VERSION 5.8 ;
BUSBITCHARS "[]" ;

UNITS
  DATABASE MICRONS 1000 ;
END UNITS

MANUFACTURINGGRID 0.005 ;

PROPERTYDEFINITIONS
  MACRO expanded_util REAL ;
END PROPERTYDEFINITIONS

LAYER POLY1
  TYPE MASTERSLICE ;
END POLY1

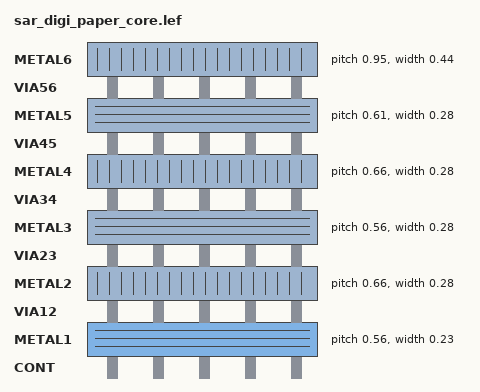
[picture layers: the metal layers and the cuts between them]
LAYER CONT
  TYPE CUT ;
END CONT

LAYER METAL1
  TYPE ROUTING ;
  DIRECTION HORIZONTAL ;
  PITCH 0.56 ;
  WIDTH 0.23 ;
  PROPERTY LEF58_WIDTH "WIDTH 0.23 WRONGDIRECTION ;" ;
END METAL1

LAYER VIA12
  TYPE CUT ;
END VIA12

LAYER METAL2
  TYPE ROUTING ;
  DIRECTION VERTICAL ;
  PITCH 0.66 ;
  WIDTH 0.28 ;
  PROPERTY LEF58_WIDTH "WIDTH 0.28 WRONGDIRECTION ;" ;
END METAL2

LAYER VIA23
  TYPE CUT ;
END VIA23

LAYER METAL3
  TYPE ROUTING ;
  DIRECTION HORIZONTAL ;
  PITCH 0.56 ;
  WIDTH 0.28 ;
  PROPERTY LEF58_WIDTH "WIDTH 0.28 WRONGDIRECTION ;" ;
END METAL3

LAYER VIA34
  TYPE CUT ;
END VIA34

LAYER METAL4
  TYPE ROUTING ;
  DIRECTION VERTICAL ;
  PITCH 0.66 ;
  WIDTH 0.28 ;
  PROPERTY LEF58_WIDTH "WIDTH 0.28 WRONGDIRECTION ;" ;
END METAL4

LAYER VIA45
  TYPE CUT ;
END VIA45

LAYER METAL5
  TYPE ROUTING ;
  DIRECTION HORIZONTAL ;
  PITCH 0.61 ;
  WIDTH 0.28 ;
  PROPERTY LEF58_WIDTH "WIDTH 0.28 WRONGDIRECTION ;" ;
END METAL5

LAYER VIA56
  TYPE CUT ;
END VIA56

LAYER METAL6
  TYPE ROUTING ;
  DIRECTION VERTICAL ;
  PITCH 0.95 ;
  WIDTH 0.44 ;
  PROPERTY LEF58_WIDTH "WIDTH 0.44 WRONGDIRECTION ;" ;
END METAL6

LAYER TEXT1
  TYPE MASTERSLICE ;
END TEXT1

LAYER TEXT2
  TYPE MASTERSLICE ;
END TEXT2

LAYER TEXT3
  TYPE MASTERSLICE ;
END TEXT3

LAYER TEXT4
  TYPE MASTERSLICE ;
END TEXT4

LAYER TEXT5
  TYPE MASTERSLICE ;
END TEXT5

LAYER TEXT6
  TYPE MASTERSLICE ;
END TEXT6

LAYER NWELL
  TYPE MASTERSLICE ;
END NWELL

LAYER PIMP
  TYPE MASTERSLICE ;
END PIMP

LAYER NIMP
  TYPE MASTERSLICE ;
END NIMP

LAYER DIFF
  TYPE MASTERSLICE ;
END DIFF

LAYER DIODE
  TYPE MASTERSLICE ;
END DIODE

LAYER PAD
  TYPE MASTERSLICE ;
END PAD

VIA CONT1
  LAYER POLY1 ;
    RECT -0.21 -0.21 0.21 0.21 ;
  LAYER CONT ;
    RECT -0.11 -0.11 0.11 0.11 ;
  LAYER METAL1 ;
    RECT -0.17 -0.12 0.17 0.12 ;
END CONT1

VIA via1
  LAYER METAL1 ;
    RECT -0.19 -0.14 0.19 0.14 ;
  LAYER VIA12 ;
    RECT -0.13 -0.13 0.13 0.13 ;
  LAYER METAL2 ;
    RECT -0.19 -0.14 0.19 0.14 ;
END via1

VIA via2
  LAYER METAL2 ;
    RECT -0.19 -0.14 0.19 0.14 ;
  LAYER VIA23 ;
    RECT -0.13 -0.13 0.13 0.13 ;
  LAYER METAL3 ;
    RECT -0.19 -0.14 0.19 0.14 ;
END via2

VIA via3
  LAYER METAL3 ;
    RECT -0.19 -0.14 0.19 0.14 ;
  LAYER VIA34 ;
    RECT -0.13 -0.13 0.13 0.13 ;
  LAYER METAL4 ;
    RECT -0.19 -0.14 0.19 0.14 ;
END via3

VIA via4
  LAYER METAL4 ;
    RECT -0.19 -0.14 0.19 0.14 ;
  LAYER VIA45 ;
    RECT -0.13 -0.13 0.13 0.13 ;
  LAYER METAL5 ;
    RECT -0.19 -0.14 0.19 0.14 ;
END via4

VIA via5
  LAYER METAL5 ;
    RECT -0.24 -0.19 0.24 0.19 ;
  LAYER VIA56 ;
    RECT -0.18 -0.18 0.18 0.18 ;
  LAYER METAL6 ;
    RECT -0.27 -0.27 0.27 0.27 ;
END via5

VIA via2ts
  LAYER METAL2 ;
    RECT -0.14 -0.37 0.14 0.37 ;
  LAYER VIA23 ;
    RECT -0.13 -0.13 0.13 0.13 ;
  LAYER METAL3 ;
    RECT -0.19 -0.14 0.19 0.14 ;
END via2ts

VIA via3ts
  LAYER METAL3 ;
    RECT -0.37 -0.14 0.37 0.14 ;
  LAYER VIA34 ;
    RECT -0.13 -0.13 0.13 0.13 ;
  LAYER METAL4 ;
    RECT -0.19 -0.14 0.19 0.14 ;
END via3ts

VIA via4ts
  LAYER METAL4 ;
    RECT -0.14 -0.37 0.14 0.37 ;
  LAYER VIA45 ;
    RECT -0.13 -0.13 0.13 0.13 ;
  LAYER METAL5 ;
    RECT -0.19 -0.14 0.19 0.14 ;
END via4ts

VIA via5ts
  LAYER METAL5 ;
    RECT -0.27 -0.19 0.27 0.19 ;
  LAYER VIA56 ;
    RECT -0.18 -0.18 0.18 0.18 ;
  LAYER METAL6 ;
    RECT -0.27 -0.27 0.27 0.27 ;
END via5ts

SITE unit
  CLASS CORE ;
  SYMMETRY Y ;
  SIZE 0.66 BY 5.04 ;
END unit

SITE smic18site
  CLASS CORE ;
  SYMMETRY Y ;
  SIZE 0.66 BY 5.04 ;
END smic18site

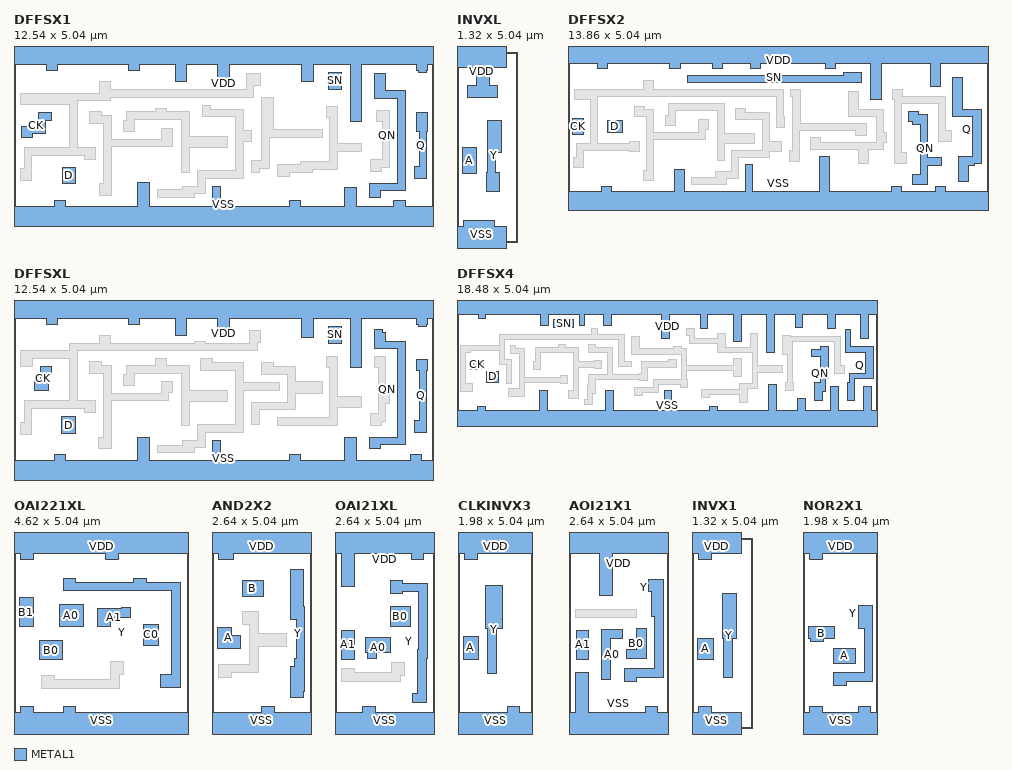
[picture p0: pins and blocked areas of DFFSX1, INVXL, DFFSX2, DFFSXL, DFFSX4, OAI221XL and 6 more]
MACRO DFFSX1
  CLASS CORE ;
  FOREIGN DFFSX1 ;
  ORIGIN 0 0 ;
  SIZE 12.54 BY 5.04 ;
  SYMMETRY X Y ;
  SITE unit ;
  PIN D
    DIRECTION INPUT ;
    USE SIGNAL ;
    PORT
      LAYER METAL1 ;
        RECT 1.435 1.08 1.845 1.58 ;
    END
  END D
  PIN CK
    DIRECTION INPUT ;
    USE SIGNAL ;
    PORT
      LAYER METAL1 ;
        POLYGON 1.105 3.195 1.105 2.965 0.955 2.965 0.955 2.575 0.555 2.575 0.555 2.465 0.215 2.465 0.215 2.805 0.725 2.805 0.725 3.195 ;
    END
  END CK
  PIN SN
    DIRECTION INPUT ;
    USE SIGNAL ;
    PORT
      LAYER METAL1 ;
        RECT 9.38 3.9 9.79 4.41 ;
    END
  END SN
  PIN Q
    DIRECTION OUTPUT ;
    USE SIGNAL ;
    PORT
      LAYER METAL1 ;
        POLYGON 12.36 3.21 12.36 2.63 12.325 2.63 12.325 1.25 11.96 1.25 11.96 1.59 12.095 1.59 12.095 2.63 12.02 2.63 12.02 3.21 ;
    END
  END Q
  PIN QN
    DIRECTION OUTPUT ;
    USE SIGNAL ;
    PORT
      LAYER METAL1 ;
        POLYGON 11.1 4.37 11.1 3.87 11.69 3.87 11.69 0.87 10.945 0.87 10.945 0.67 10.605 0.67 10.605 1.1 11.46 1.1 11.46 3.64 10.76 3.64 10.76 4.37 ;
    END
  END QN
  PIN VDD
    DIRECTION INPUT ;
    USE POWER ;
    PORT
      LAYER METAL1 ;
        POLYGON 12.54 5.44 12.54 4.64 12.36 4.64 12.36 4.465 12.305 4.465 12.305 4.41 12.075 4.41 12.075 4.465 12.02 4.465 12.02 4.64 10.38 4.64 10.38 2.94 10.04 2.94 10.04 4.64 8.93 4.64 8.93 4.14 8.59 4.14 8.59 4.64 6.42 4.64 6.42 4.14 6.08 4.14 6.08 4.64 5.16 4.64 5.16 4.14 4.82 4.14 4.82 4.64 3.76 4.64 3.76 4.465 3.42 4.465 3.42 4.64 1.3 4.64 1.3 4.465 0.96 4.465 0.96 4.64 0 4.64 0 5.44 ;
    END
  END VDD
  PIN VSS
    DIRECTION INPUT ;
    USE GROUND ;
    PORT
      LAYER METAL1 ;
        POLYGON 4.04 1.11 4.04 0.4 5.935 0.4 5.935 1.01 6.165 1.01 6.165 0.4 8.22 0.4 8.22 0.575 8.56 0.575 8.56 0.4 9.88 0.4 9.88 0.96 10.22 0.96 10.22 0.4 11.345 0.4 11.345 0.575 11.685 0.575 11.685 0.4 12.54 0.4 12.54 -0.4 0 -0.4 0 0.4 1.205 0.4 1.205 0.575 1.545 0.575 1.545 0.4 3.7 0.4 3.7 1.11 ;
    END
  END VSS
  OBS
    LAYER METAL1 ;
      POLYGON 7.37 4.36 7.37 4.02 7.165 4.02 7.165 3.67 2.88 3.67 2.88 3.56 1.905 3.56 1.905 2.16 2.445 2.16 2.445 1.82 2.105 1.82 2.105 1.93 0.53 1.93 0.53 1.19 0.19 1.19 0.19 1.53 0.3 1.53 0.3 2.16 1.655 2.16 1.655 3.45 0.195 3.45 0.195 3.79 2.54 3.79 2.54 4.14 2.88 4.14 2.88 3.9 6.935 3.9 6.935 4.36 ;
      POLYGON 7.74 3.65 7.74 2.695 9.2 2.695 9.2 2.465 7.63 2.465 7.63 1.54 7.325 1.54 7.325 1.43 7.095 1.43 7.095 1.77 7.4 1.77 7.4 3.65 ;
      POLYGON 5.865 3.42 5.865 3.31 6.84 3.31 6.84 2.675 7.1 2.675 7.1 2.335 6.84 2.335 6.84 1.24 5.705 1.24 5.705 0.78 5.385 0.78 5.385 0.675 5.38 0.675 5.38 0.67 5.04 0.67 5.04 0.675 4.27 0.675 4.27 0.905 5.04 0.905 5.04 1.01 5.475 1.01 5.475 1.47 6.61 1.47 6.61 3.08 5.635 3.08 5.635 3.42 ;
      POLYGON 9.66 3.4 9.66 2.27 10.37 2.27 10.37 2.04 9.66 2.04 9.66 1.52 8.9 1.52 8.9 1.405 8.22 1.405 8.22 1.305 7.88 1.305 7.88 1.645 8.56 1.645 8.56 1.75 9.43 1.75 9.43 3.06 9.32 3.06 9.32 3.4 ;
      POLYGON 4.56 3.34 4.56 3.23 5.245 3.23 5.245 2.505 6.375 2.505 6.375 2.165 5.245 2.165 5.245 1.42 5.015 1.42 5.015 3 3.6 3 3.6 2.64 3.26 2.64 3.26 2.98 3.37 2.98 3.37 3.23 4.22 3.23 4.22 3.34 ;
      POLYGON 11.225 3.28 11.225 1.57 10.985 1.57 10.985 1.46 10.645 1.46 10.645 1.8 10.995 1.8 10.995 2.94 10.815 2.94 10.815 3.28 ;
      POLYGON 2.6 3.225 2.6 3.115 2.91 3.115 2.91 2.41 4.39 2.41 4.39 2.735 4.73 2.735 4.73 2.395 4.725 2.395 4.725 2.18 2.91 2.18 2.91 0.74 2.565 0.74 2.565 1.08 2.68 1.08 2.68 2.885 2.26 2.885 2.26 3.225 ;
  END
END DFFSX1

MACRO INVXL
  CLASS CORE ;
  FOREIGN INVXL ;
  ORIGIN 0 0 ;
  SIZE 1.32 BY 5.04 ;
  SYMMETRY X Y ;
  SITE unit ;
  PIN A
    DIRECTION INPUT ;
    USE SIGNAL ;
    PORT
      LAYER METAL1 ;
        RECT 0.14 1.82 0.52 2.51 ;
    END
  END A
  PIN Y
    DIRECTION OUTPUT ;
    USE SIGNAL ;
    PORT
      LAYER METAL1 ;
        POLYGON 1.18 3.225 1.18 2.38 1.03 2.38 1.03 1.845 1.12 1.845 1.12 1.35 0.78 1.35 0.78 1.845 0.8 1.845 0.8 3.225 ;
    END
  END Y
  PIN VDD
    DIRECTION INPUT ;
    USE POWER ;
    PORT
      LAYER METAL1 ;
        POLYGON 1.32 5.44 1.32 4.64 0.85 4.64 0.85 4.16 1.085 4.16 1.085 3.82 0.275 3.82 0.275 4.16 0.51 4.16 0.51 4.64 0 4.64 0 5.44 ;
    END
  END VDD
  PIN VSS
    DIRECTION INPUT ;
    USE GROUND ;
    PORT
      LAYER METAL1 ;
        POLYGON 0.99 0.575 0.99 0.4 1.32 0.4 1.32 -0.4 0 -0.4 0 0.4 0.18 0.4 0.18 0.575 ;
    END
  END VSS
END INVXL

MACRO DFFSX2
  CLASS CORE ;
  FOREIGN DFFSX2 ;
  ORIGIN 0 0 ;
  SIZE 13.86 BY 5.04 ;
  SYMMETRY X Y ;
  SITE unit ;
  PIN D
    DIRECTION INPUT ;
    USE SIGNAL ;
    PORT
      LAYER METAL1 ;
        RECT 1.29 2.36 1.805 2.755 ;
    END
  END D
  PIN CK
    DIRECTION INPUT ;
    USE SIGNAL ;
    PORT
      LAYER METAL1 ;
        RECT 0.135 2.295 0.515 2.83 ;
    END
  END CK
  PIN SN
    DIRECTION INPUT ;
    USE SIGNAL ;
    PORT
      LAYER METAL1 ;
        POLYGON 9.685 4.355 9.685 4.005 3.93 4.005 3.93 4.235 9.085 4.235 9.085 4.355 ;
    END
  END SN
  PIN Q
    DIRECTION OUTPUT ;
    USE SIGNAL ;
    PORT
      LAYER METAL1 ;
        POLYGON 13.02 4.165 13.02 3.115 13.645 3.115 13.645 1.325 13.415 1.325 13.415 1.26 13.23 1.26 13.23 0.745 12.89 0.745 12.89 1.555 13.34 1.555 13.34 2.885 12.68 2.885 12.68 4.165 ;
    END
  END Q
  PIN QN
    DIRECTION OUTPUT ;
    USE SIGNAL ;
    PORT
      LAYER METAL1 ;
        POLYGON 11.58 3.05 11.58 2.94 11.86 2.94 11.86 1.54 12.325 1.54 12.325 1.26 11.86 1.26 11.86 0.63 11.37 0.63 11.37 0.97 11.63 0.97 11.63 2.635 11.36 2.635 11.36 2.71 11.24 2.71 11.24 3.05 ;
    END
  END QN
  PIN VDD
    DIRECTION INPUT ;
    USE POWER ;
    PORT
      LAYER METAL1 ;
        POLYGON 13.86 5.44 13.86 4.64 12.3 4.64 12.3 3.865 11.96 3.865 11.96 4.64 10.33 4.64 10.33 3.445 9.98 3.445 9.98 3.785 9.99 3.785 9.99 4.64 8.84 4.64 8.84 4.465 8.5 4.465 8.5 4.64 6.36 4.64 6.36 4.465 6.02 4.465 6.02 4.64 5.1 4.64 5.1 4.465 4.76 4.465 4.76 4.64 3.7 4.64 3.7 4.465 3.36 4.465 3.36 4.64 1.31 4.64 1.31 4.465 0.97 4.465 0.97 4.64 0 4.64 0 5.44 ;
    END
  END VDD
  PIN VSS
    DIRECTION INPUT ;
    USE GROUND ;
    PORT
      LAYER METAL1 ;
        POLYGON 8.63 1.565 8.63 0.4 10.67 0.4 10.67 0.575 11.01 0.575 11.01 0.4 12.13 0.4 12.13 0.575 12.47 0.575 12.47 0.4 13.86 0.4 13.86 -0.4 0 -0.4 0 0.4 1.11 0.4 1.11 0.575 1.45 0.575 1.45 0.4 3.52 0.4 3.52 1.13 3.86 1.13 3.86 0.4 5.855 0.4 5.855 1.3 6.085 1.3 6.085 0.4 8.29 0.4 8.29 1.565 ;
    END
  END VSS
  OBS
    LAYER METAL1 ;
      POLYGON 2.82 4.06 2.82 3.775 7.11 3.775 7.11 2.88 7.145 2.88 7.145 2.54 6.88 2.54 6.88 3.545 0.98 3.545 0.98 2.01 2.03 2.01 2.03 2.065 2.37 2.065 2.37 1.725 2.03 1.725 2.03 1.78 0.525 1.78 0.525 1.19 0.185 1.19 0.185 1.53 0.295 1.53 0.295 2.01 0.75 2.01 0.75 3.45 0.21 3.45 0.21 3.79 0.55 3.79 0.55 3.775 2.48 3.775 2.48 4.06 ;
      POLYGON 11.04 3.78 11.04 3.545 12.45 3.545 12.45 2.41 12.67 2.41 12.67 2.07 12.22 2.07 12.22 3.315 11.01 3.315 11.01 1.685 11.17 1.685 11.17 1.345 10.78 1.345 10.78 3.44 10.7 3.44 10.7 3.78 ;
      POLYGON 7.68 3.775 7.68 2.665 9.84 2.665 9.84 2.255 9.5 2.255 9.5 2.435 7.625 2.435 7.625 1.405 7.305 1.405 7.305 1.75 7.395 1.75 7.395 3.545 7.34 3.545 7.34 3.775 ;
      POLYGON 9.6 3.705 9.6 3.125 10.405 3.125 10.405 2.355 10.515 2.355 10.515 2.015 10.405 2.015 10.405 1.795 9.91 1.795 9.91 1.335 9.57 1.335 9.57 1.795 7.99 1.795 7.99 2.205 8.33 2.205 8.33 2.025 10.175 2.025 10.175 2.895 9.26 2.895 9.26 3.705 ;
      POLYGON 5.165 3.315 5.165 2.33 6.17 2.33 6.17 1.99 5.165 1.99 5.165 1.44 4.935 1.44 4.935 3.085 3.55 3.085 3.55 2.59 3.21 2.59 3.21 2.93 3.32 2.93 3.32 3.315 ;
      POLYGON 2.54 3.225 2.54 3.115 2.83 3.115 2.83 2.355 4.31 2.355 4.31 2.785 4.65 2.785 4.65 2.445 4.54 2.445 4.54 2.125 2.83 2.125 2.83 0.815 2.825 0.815 2.825 0.76 2.485 0.76 2.485 1.1 2.6 1.1 2.6 2.885 2.2 2.885 2.2 3.225 ;
      POLYGON 5.86 3.14 5.86 3.03 6.645 3.03 6.645 2.075 7.06 2.075 7.06 1.735 6.645 1.735 6.645 1.53 5.625 1.53 5.625 0.84 5.22 0.84 5.22 0.635 4.09 0.635 4.09 0.865 4.88 0.865 4.88 1.07 5.395 1.07 5.395 1.76 6.415 1.76 6.415 2.8 5.52 2.8 5.52 3.14 ;
  END
END DFFSX2

MACRO DFFSXL
  CLASS CORE ;
  FOREIGN DFFSXL ;
  ORIGIN 0 0 ;
  SIZE 12.54 BY 5.04 ;
  SYMMETRY X Y ;
  SITE unit ;
  PIN D
    DIRECTION INPUT ;
    USE SIGNAL ;
    PORT
      LAYER METAL1 ;
        RECT 1.425 1.205 1.835 1.705 ;
    END
  END D
  PIN CK
    DIRECTION INPUT ;
    USE SIGNAL ;
    PORT
      LAYER METAL1 ;
        POLYGON 1.105 3.195 1.105 2.965 1.03 2.965 1.03 2.48 0.605 2.48 0.605 2.82 0.8 2.82 0.8 3.195 ;
    END
  END CK
  PIN SN
    DIRECTION INPUT ;
    USE SIGNAL ;
    PORT
      LAYER METAL1 ;
        RECT 9.38 3.9 9.79 4.41 ;
    END
  END SN
  PIN Q
    DIRECTION OUTPUT ;
    USE SIGNAL ;
    PORT
      LAYER METAL1 ;
        POLYGON 12.36 3.43 12.36 3.09 12.325 3.09 12.325 1.25 11.96 1.25 11.96 1.59 12.095 1.59 12.095 3.09 12.02 3.09 12.02 3.43 ;
    END
  END Q
  PIN QN
    DIRECTION OUTPUT ;
    USE SIGNAL ;
    PORT
      LAYER METAL1 ;
        POLYGON 11.005 4.315 11.005 4.21 11.1 4.21 11.1 3.97 11.69 3.97 11.69 0.87 10.945 0.87 10.945 0.755 10.605 0.755 10.605 1.1 11.46 1.1 11.46 3.74 10.76 3.74 10.76 4.315 ;
    END
  END QN
  PIN VDD
    DIRECTION INPUT ;
    USE POWER ;
    PORT
      LAYER METAL1 ;
        POLYGON 12.54 5.44 12.54 4.64 12.36 4.64 12.36 4.465 12.305 4.465 12.305 4.41 12.075 4.41 12.075 4.465 12.02 4.465 12.02 4.64 10.38 4.64 10.38 3.17 10.04 3.17 10.04 4.64 8.93 4.64 8.93 4.08 8.59 4.08 8.59 4.64 6.42 4.64 6.42 4.135 6.08 4.135 6.08 4.64 5.16 4.64 5.16 4.135 4.82 4.135 4.82 4.64 3.76 4.64 3.76 4.465 3.42 4.465 3.42 4.64 1.3 4.64 1.3 4.465 0.96 4.465 0.96 4.64 0 4.64 0 5.44 ;
    END
  END VDD
  PIN VSS
    DIRECTION INPUT ;
    USE GROUND ;
    PORT
      LAYER METAL1 ;
        POLYGON 10.22 1.095 10.22 0.4 11.825 0.4 11.825 0.575 12.165 0.575 12.165 0.4 12.54 0.4 12.54 -0.4 0 -0.4 0 0.4 1.195 0.4 1.195 0.575 1.535 0.575 1.535 0.4 3.7 0.4 3.7 1.09 4.04 1.09 4.04 0.4 5.935 0.4 5.935 1.01 6.165 1.01 6.165 0.4 8.22 0.4 8.22 0.575 8.56 0.575 8.56 0.4 9.88 0.4 9.88 1.095 ;
    END
  END VSS
  OBS
    LAYER METAL1 ;
      POLYGON 7.37 4.27 7.37 3.93 7.26 3.93 7.26 3.675 1.905 3.675 1.905 2.19 2.435 2.19 2.435 1.85 2.095 1.85 2.095 1.96 0.53 1.96 0.53 1.19 0.19 1.19 0.19 1.53 0.3 1.53 0.3 2.19 1.655 2.19 1.655 3.45 0.54 3.45 0.54 3.22 0.2 3.22 0.2 3.68 1.655 3.68 1.655 3.905 2.54 3.905 2.54 4.14 2.88 4.14 2.88 3.905 5.39 3.905 5.39 3.945 5.73 3.945 5.73 3.905 7.03 3.905 7.03 4.27 ;
      POLYGON 11.1 3.51 11.1 2.45 11.225 2.45 11.225 2.11 11.1 2.11 11.1 1.57 10.985 1.57 10.985 1.46 10.645 1.46 10.645 1.8 10.87 1.8 10.87 3.17 10.76 3.17 10.76 3.51 ;
      POLYGON 9.66 3.51 9.66 2.325 10.37 2.325 10.37 1.985 9.66 1.985 9.66 1.455 7.88 1.455 7.88 1.685 9.43 1.685 9.43 3.17 9.32 3.17 9.32 3.51 ;
      POLYGON 5.92 3.44 5.92 3.33 6.84 3.33 6.84 2.73 7.93 2.73 7.93 2.5 6.84 2.5 6.84 1.24 5.705 1.24 5.705 0.78 5.385 0.78 5.385 0.63 4.27 0.63 4.27 0.86 5.04 0.86 5.04 1.01 5.475 1.01 5.475 1.47 6.61 1.47 6.61 3.1 5.58 3.1 5.58 3.44 ;
      POLYGON 4.56 3.44 4.56 3.235 5.245 3.235 5.245 2.505 6.375 2.505 6.375 2.165 5.245 2.165 5.245 1.46 5.015 1.46 5.015 3.005 3.6 3.005 3.6 2.64 3.26 2.64 3.26 2.98 3.37 2.98 3.37 3.235 4.22 3.235 4.22 3.44 ;
      POLYGON 2.6 3.35 2.6 3.24 2.9 3.24 2.9 2.41 4.39 2.41 4.39 2.77 4.73 2.77 4.73 2.43 4.62 2.43 4.62 2.18 2.91 2.18 2.91 0.76 2.9 0.76 2.9 0.75 2.515 0.75 2.515 1.09 2.67 1.09 2.67 3.01 2.26 3.01 2.26 3.35 ;
      POLYGON 7.74 3.32 7.74 3.21 8.39 3.21 8.39 2.75 9.2 2.75 9.2 2.41 8.39 2.41 8.39 1.915 7.325 1.915 7.325 1.47 7.095 1.47 7.095 2.145 8.16 2.145 8.16 2.98 7.4 2.98 7.4 3.32 ;
  END
END DFFSXL

MACRO DFFSX4
  CLASS CORE ;
  FOREIGN DFFSX4 ;
  ORIGIN 0 0 ;
  SIZE 18.48 BY 5.04 ;
  SYMMETRY X Y ;
  SITE unit ;
  PIN D
    DIRECTION INPUT ;
    USE SIGNAL ;
    PORT
      LAYER METAL1 ;
        POLYGON 1.84 2.14 1.84 2.1 1.845 2.1 1.845 1.82 1.84 1.82 1.84 1.67 1.305 1.67 1.305 2.14 ;
    END
  END D
  PIN CK
    DIRECTION INPUT ;
    USE SIGNAL ;
    PORT
      LAYER METAL1 ;
        POLYGON 1.18 2.66 1.18 2.38 0.945 2.38 0.945 2.21 0.605 2.21 0.605 2.66 ;
    END
  END CK
  PIN SN
    DIRECTION INPUT ;
    USE SIGNAL ;
    PORT
      LAYER METAL1 ;
        RECT 4.26 4.05 5.14 4.41 ;
    END
  END SN
  PIN Q
    DIRECTION OUTPUT ;
    USE SIGNAL ;
    PORT
      LAYER METAL1 ;
        POLYGON 17.325 3.975 17.325 3.215 17.96 3.215 17.96 3.22 18.34 3.22 18.34 1.82 17.5 1.82 17.5 0.855 17.16 0.855 17.16 1.665 17.27 1.665 17.27 2.05 17.96 2.05 17.96 2.985 17.095 2.985 17.095 3.975 ;
    END
  END Q
  PIN QN
    DIRECTION OUTPUT ;
    USE SIGNAL ;
    PORT
      LAYER METAL1 ;
        POLYGON 16.36 3.22 16.36 1.82 16.21 1.82 16.21 1.26 16.06 1.26 16.06 0.855 15.72 0.855 15.72 1.665 15.98 1.665 15.98 2.78 15.6 2.78 15.6 3.12 15.98 3.12 15.98 3.22 ;
    END
  END QN
  PIN VDD
    DIRECTION INPUT ;
    USE POWER ;
    PORT
      LAYER METAL1 ;
        POLYGON 18.48 5.44 18.48 4.64 18.1 4.64 18.1 3.605 17.76 3.605 17.76 4.64 16.66 4.64 16.66 4.03 16.32 4.03 16.32 4.64 15.22 4.64 15.22 4.09 14.88 4.09 14.88 4.64 13.96 4.64 13.96 2.975 13.62 2.975 13.62 4.64 12.52 4.64 12.52 3.435 12.18 3.435 12.18 4.64 11.04 4.64 11.04 4.04 10.7 4.04 10.7 4.64 9.33 4.64 9.33 3.6 8.99 3.6 8.99 4.64 6.78 4.64 6.78 4.14 6.44 4.14 6.44 4.64 5.6 4.64 5.6 4.14 5.37 4.14 5.37 4.64 4.03 4.64 4.03 4.15 3.69 4.15 3.69 4.64 1.265 4.64 1.265 4.465 0.925 4.465 0.925 4.64 0 4.64 0 5.44 ;
    END
  END VDD
  PIN VSS
    DIRECTION INPUT ;
    USE GROUND ;
    PORT
      LAYER METAL1 ;
        POLYGON 14.04 1.55 14.04 0.4 15 0.4 15 0.95 15.34 0.95 15.34 0.4 16.44 0.4 16.44 1.485 16.78 1.485 16.78 0.4 17.88 0.4 17.88 1.485 18.22 1.485 18.22 0.4 18.48 0.4 18.48 -0.4 0 -0.4 0 0.4 0.91 0.4 0.91 0.575 1.25 0.575 1.25 0.4 3.63 0.4 3.63 1.28 3.97 1.28 3.97 0.4 6.55 0.4 6.55 1.32 6.89 1.32 6.89 0.4 9.11 0.4 9.11 1.32 9.45 1.32 9.45 0.4 11.1 0.4 11.1 0.575 11.44 0.575 11.44 0.4 13.7 0.4 13.7 1.55 ;
    END
  END VSS
  OBS
    LAYER METAL1 ;
      POLYGON 10.45 4.04 10.45 3.595 11.46 3.595 11.46 3.785 11.8 3.785 11.8 3.205 12.9 3.205 12.9 3.785 13.24 3.785 13.24 2.42 14.3 2.42 14.3 2.08 13.24 2.08 13.24 1.375 12.76 1.375 12.76 0.79 12.42 0.79 12.42 1.11 11.11 1.11 11.11 1 10.77 1 10.77 1.34 12.42 1.34 12.42 1.605 13.01 1.605 13.01 2.975 11.46 2.975 11.46 3.365 10.22 3.365 10.22 3.7 10.11 3.7 10.11 4.04 ;
      POLYGON 6.165 4.025 6.165 3.78 7.355 3.78 7.355 2.595 7.69 2.595 7.69 2.365 7.125 2.365 7.125 3.55 2.105 3.55 2.105 2.66 2.405 2.66 2.405 1.61 2.175 1.61 2.175 2.43 1.875 2.43 1.875 3.07 0.61 3.07 0.61 2.96 0.375 2.96 0.375 1.595 0.69 1.595 0.69 1.255 0.145 1.255 0.145 3.3 1.875 3.3 1.875 3.78 5.935 3.78 5.935 4.025 ;
      POLYGON 14.68 3.71 14.68 3.685 16.86 3.685 16.86 2.38 17.03 2.38 17.03 2.04 16.63 2.04 16.63 3.455 14.76 3.455 14.76 1.65 14.8 1.65 14.8 1.31 14.46 1.31 14.46 1.65 14.53 1.65 14.53 2.9 14.34 2.9 14.34 3.71 ;
      POLYGON 8.01 3.675 8.01 3.13 9.54 3.13 9.54 3.24 9.88 3.24 9.88 3.13 10.105 3.13 10.105 2.415 12.18 2.415 12.18 2.705 12.52 2.705 12.52 1.895 12.18 1.895 12.18 2.185 10.105 2.185 10.105 1.77 10.16 1.77 10.16 1.43 9.82 1.43 9.82 1.55 8.875 1.55 8.875 1.19 8.17 1.19 8.17 1.08 7.83 1.08 7.83 1.42 8.645 1.42 8.645 1.78 9.875 1.78 9.875 2.9 8.01 2.9 8.01 2.865 7.67 2.865 7.67 3.675 ;
      POLYGON 6.11 3.32 6.11 3.21 6.835 3.21 6.835 2.005 8.02 2.005 8.02 2.06 8.13 2.06 8.13 2.56 9.305 2.56 9.305 2.67 9.645 2.67 9.645 2.33 8.36 2.33 8.36 1.72 8.02 1.72 8.02 1.775 6.835 1.775 6.835 1.765 6.09 1.765 6.09 1.16 5.98 1.16 5.98 0.685 5.6 0.685 5.6 0.915 5.75 0.915 5.75 1.5 5.805 1.5 5.805 2.005 6.605 2.005 6.605 2.98 5.77 2.98 5.77 3.32 ;
      POLYGON 4.79 3.32 4.79 3.21 5.34 3.21 5.34 2.555 6.035 2.555 6.035 2.61 6.375 2.61 6.375 2.27 6.035 2.27 6.035 2.325 5.34 2.325 5.34 0.955 4.91 0.955 4.91 1.3 5.11 1.3 5.11 2.98 3.695 2.98 3.695 2.325 3.69 2.325 3.69 2.215 3.35 2.215 3.35 2.555 3.465 2.555 3.465 3.21 4.45 3.21 4.45 3.32 ;
      POLYGON 2.565 3.3 2.565 3.135 2.98 3.135 2.98 1.89 4.54 1.89 4.54 1.945 4.88 1.945 4.88 1.605 4.54 1.605 4.54 1.66 2.98 1.66 2.98 1.04 2.27 1.04 2.27 1.38 2.75 1.38 2.75 2.905 2.335 2.905 2.335 3.3 ;
  END
END DFFSX4

MACRO OAI221XL
  CLASS CORE ;
  FOREIGN OAI221XL ;
  ORIGIN 0 0 ;
  SIZE 4.62 BY 5.04 ;
  SYMMETRY X Y ;
  SITE unit ;
  PIN A0
    DIRECTION INPUT ;
    USE SIGNAL ;
    PORT
      LAYER METAL1 ;
        POLYGON 1.845 3.27 1.845 2.695 1.835 2.695 1.835 2.69 1.495 2.69 1.495 2.695 1.195 2.695 1.195 3.27 ;
    END
  END A0
  PIN A1
    DIRECTION INPUT ;
    USE SIGNAL ;
    PORT
      LAYER METAL1 ;
        POLYGON 3.085 3.195 3.085 2.94 2.55 2.94 2.55 2.685 2.21 2.685 2.21 3.17 2.855 3.17 2.855 3.195 ;
    END
  END A1
  PIN B0
    DIRECTION INPUT ;
    USE SIGNAL ;
    PORT
      LAYER METAL1 ;
        RECT 0.665 1.82 1.275 2.31 ;
    END
  END B0
  PIN B1
    DIRECTION INPUT ;
    USE SIGNAL ;
    PORT
      LAYER METAL1 ;
        RECT 0.14 2.69 0.52 3.45 ;
    END
  END B1
  PIN C0
    DIRECTION INPUT ;
    USE SIGNAL ;
    PORT
      LAYER METAL1 ;
        RECT 3.44 2.19 3.82 2.745 ;
    END
  END C0
  PIN Y
    DIRECTION OUTPUT ;
    USE SIGNAL ;
    PORT
      LAYER METAL1 ;
        POLYGON 3.52 3.975 3.52 3.865 4.405 3.865 4.405 1.085 3.89 1.085 3.89 1.425 4.175 1.425 4.175 3.635 1.3 3.635 1.3 3.975 1.64 3.975 1.64 3.865 3.18 3.865 3.18 3.975 ;
    END
  END Y
  PIN VDD
    DIRECTION INPUT ;
    USE POWER ;
    PORT
      LAYER METAL1 ;
        POLYGON 4.62 5.44 4.62 4.64 2.76 4.64 2.76 4.465 2.42 4.465 2.42 4.64 0.52 4.64 0.52 4.465 0.18 4.465 0.18 4.64 0 4.64 0 5.44 ;
    END
  END VDD
  PIN VSS
    DIRECTION INPUT ;
    USE GROUND ;
    PORT
      LAYER METAL1 ;
        POLYGON 1.64 0.575 1.64 0.4 4.62 0.4 4.62 -0.4 0 -0.4 0 0.4 0.18 0.4 0.18 0.575 0.52 0.575 0.52 0.4 1.3 0.4 1.3 0.575 ;
    END
  END VSS
  OBS
    LAYER METAL1 ;
      POLYGON 2.905 1.765 2.905 1.425 2.795 1.425 2.795 1.06 0.74 1.06 0.74 1.4 1.08 1.4 1.08 1.29 2.565 1.29 2.565 1.765 ;
  END
END OAI221XL

MACRO AND2X2
  CLASS CORE ;
  FOREIGN AND2X2 ;
  ORIGIN 0 0 ;
  SIZE 2.64 BY 5.04 ;
  SYMMETRY X Y ;
  SITE unit ;
  PIN A
    DIRECTION INPUT ;
    USE SIGNAL ;
    PORT
      LAYER METAL1 ;
        POLYGON 0.52 2.66 0.52 2.455 0.76 2.455 0.76 2.115 0.14 2.115 0.14 2.66 ;
    END
  END A
  PIN B
    DIRECTION INPUT ;
    USE SIGNAL ;
    PORT
      LAYER METAL1 ;
        RECT 0.8 3.5 1.36 3.925 ;
    END
  END B
  PIN Y
    DIRECTION OUTPUT ;
    USE SIGNAL ;
    PORT
      LAYER METAL1 ;
        POLYGON 2.42 4.21 2.42 3.22 2.465 3.22 2.465 0.955 2.42 0.955 2.42 0.82 2.08 0.82 2.08 1.64 2.195 1.64 2.195 1.845 2.235 1.845 2.235 2.89 2.08 2.89 2.08 4.21 ;
    END
  END Y
  PIN VDD
    DIRECTION INPUT ;
    USE POWER ;
    PORT
      LAYER METAL1 ;
        POLYGON 2.64 5.44 2.64 4.64 0.57 4.64 0.57 4.465 0.18 4.465 0.18 4.64 0 4.64 0 5.44 ;
    END
  END VDD
  PIN VSS
    DIRECTION INPUT ;
    USE GROUND ;
    PORT
      LAYER METAL1 ;
        POLYGON 1.66 0.575 1.66 0.4 2.64 0.4 2.64 -0.4 0 -0.4 0 0.4 1.32 0.4 1.32 0.575 ;
    END
  END VSS
  OBS
    LAYER METAL1 ;
      POLYGON 1.225 3.095 1.225 2.495 1.965 2.495 1.965 2.15 1.225 2.15 1.225 1.46 0.52 1.46 0.52 1.35 0.18 1.35 0.18 1.69 0.995 1.69 0.995 2.745 0.815 2.745 0.815 3.095 ;
  END
END AND2X2

MACRO OAI21XL
  CLASS CORE ;
  FOREIGN OAI21XL ;
  ORIGIN 0 0 ;
  SIZE 2.64 BY 5.04 ;
  SYMMETRY X Y ;
  SITE unit ;
  PIN A0
    DIRECTION INPUT ;
    USE SIGNAL ;
    PORT
      LAYER METAL1 ;
        POLYGON 1.465 2.4 1.465 2.01 1.105 2.01 1.105 1.845 0.875 1.845 0.875 2.01 0.8 2.01 0.8 2.4 ;
    END
  END A0
  PIN A1
    DIRECTION INPUT ;
    USE SIGNAL ;
    PORT
      LAYER METAL1 ;
        RECT 0.18 1.82 0.52 2.595 ;
    END
  END A1
  PIN B0
    DIRECTION INPUT ;
    USE SIGNAL ;
    PORT
      LAYER METAL1 ;
        RECT 1.46 2.69 1.99 3.22 ;
    END
  END B0
  PIN Y
    DIRECTION OUTPUT ;
    USE SIGNAL ;
    PORT
      LAYER METAL1 ;
        POLYGON 1.8 3.9 1.8 3.845 2.45 3.845 2.45 1.845 2.425 1.845 2.425 0.675 2.06 0.675 2.06 0.905 2.195 0.905 2.195 2.075 2.22 2.075 2.22 3.615 1.8 3.615 1.8 3.56 1.46 3.56 1.46 3.9 ;
    END
  END Y
  PIN VDD
    DIRECTION INPUT ;
    USE POWER ;
    PORT
      LAYER METAL1 ;
        POLYGON 2.64 5.44 2.64 4.64 2.36 4.64 2.36 4.465 2.02 4.465 2.02 4.64 0.52 4.64 0.52 3.76 0.18 3.76 0.18 4.64 0 4.64 0 5.44 ;
    END
  END VDD
  PIN VSS
    DIRECTION INPUT ;
    USE GROUND ;
    PORT
      LAYER METAL1 ;
        POLYGON 1.08 0.575 1.08 0.4 2.64 0.4 2.64 -0.4 0 -0.4 0 0.4 0.74 0.4 0.74 0.575 ;
    END
  END VSS
  OBS
    LAYER METAL1 ;
      POLYGON 1.84 1.735 1.84 1.395 1.73 1.395 1.73 1.245 0.18 1.245 0.18 1.585 0.52 1.585 0.52 1.475 1.5 1.475 1.5 1.735 ;
  END
END OAI21XL

MACRO CLKINVX3
  CLASS CORE ;
  FOREIGN CLKINVX3 ;
  ORIGIN 0 0 ;
  SIZE 1.98 BY 5.04 ;
  SYMMETRY X Y ;
  SITE unit ;
  PIN A
    DIRECTION INPUT ;
    USE SIGNAL ;
    PORT
      LAYER METAL1 ;
        RECT 0.14 1.82 0.535 2.44 ;
    END
  END A
  PIN Y
    DIRECTION OUTPUT ;
    USE SIGNAL ;
    PORT
      LAYER METAL1 ;
        POLYGON 1.18 3.78 1.18 2.63 1.025 2.63 1.025 1.435 0.795 1.435 0.795 2.635 0.735 2.635 0.735 3.78 ;
    END
  END Y
  PIN VDD
    DIRECTION INPUT ;
    USE POWER ;
    PORT
      LAYER METAL1 ;
        POLYGON 1.98 5.44 1.98 4.64 0.52 4.64 0.52 4.465 0.18 4.465 0.18 4.64 0 4.64 0 5.44 ;
    END
  END VDD
  PIN VSS
    DIRECTION INPUT ;
    USE GROUND ;
    PORT
      LAYER METAL1 ;
        POLYGON 1.64 0.575 1.64 0.4 1.98 0.4 1.98 -0.4 0 -0.4 0 0.4 1.3 0.4 1.3 0.575 ;
    END
  END VSS
END CLKINVX3

MACRO AOI21X1
  CLASS CORE ;
  FOREIGN AOI21X1 ;
  ORIGIN 0 0 ;
  SIZE 2.64 BY 5.04 ;
  SYMMETRY X Y ;
  SITE unit ;
  PIN A0
    DIRECTION INPUT ;
    USE SIGNAL ;
    PORT
      LAYER METAL1 ;
        POLYGON 1.43 2.615 1.43 2.385 1.105 2.385 1.105 1.285 0.875 1.285 0.875 2.615 ;
    END
  END A0
  PIN A1
    DIRECTION INPUT ;
    USE SIGNAL ;
    PORT
      LAYER METAL1 ;
        POLYGON 0.53 2.585 0.53 2.065 0.52 2.065 0.52 1.82 0.19 1.82 0.19 2.585 ;
    END
  END A1
  PIN B0
    DIRECTION INPUT ;
    USE SIGNAL ;
    PORT
      LAYER METAL1 ;
        POLYGON 2.045 2.635 2.045 1.845 1.535 1.845 1.535 2.075 1.8 2.075 1.8 2.635 ;
    END
  END B0
  PIN Y
    DIRECTION OUTPUT ;
    USE SIGNAL ;
    PORT
      LAYER METAL1 ;
        POLYGON 2.505 3.95 2.505 1.35 1.8 1.35 1.8 1.24 1.46 1.24 1.46 1.58 2.275 1.58 2.275 2.965 2.195 2.965 2.195 3.61 2.1 3.61 2.1 3.95 ;
    END
  END Y
  PIN VDD
    DIRECTION INPUT ;
    USE POWER ;
    PORT
      LAYER METAL1 ;
        POLYGON 2.64 5.44 2.64 4.64 1.16 4.64 1.16 3.515 0.82 3.515 0.82 4.64 0 4.64 0 5.44 ;
    END
  END VDD
  PIN VSS
    DIRECTION INPUT ;
    USE GROUND ;
    PORT
      LAYER METAL1 ;
        POLYGON 0.52 1.465 0.52 0.4 2.02 0.4 2.02 0.575 2.36 0.575 2.36 0.4 2.64 0.4 2.64 -0.4 0 -0.4 0 0.4 0.18 0.4 0.18 1.465 ;
    END
  END VSS
  OBS
    LAYER METAL1 ;
      RECT 0.18 2.925 1.8 3.155 ;
  END
END AOI21X1

MACRO INVX1
  CLASS CORE ;
  FOREIGN INVX1 ;
  ORIGIN 0 0 ;
  SIZE 1.32 BY 5.04 ;
  SYMMETRY X Y ;
  SITE unit ;
  PIN A
    DIRECTION INPUT ;
    USE SIGNAL ;
    PORT
      LAYER METAL1 ;
        RECT 0.14 1.82 0.57 2.385 ;
    END
  END A
  PIN Y
    DIRECTION OUTPUT ;
    USE SIGNAL ;
    PORT
      LAYER METAL1 ;
        POLYGON 1.18 3.56 1.18 2.37 1.065 2.37 1.065 1.35 0.835 1.35 0.835 2.37 0.8 2.37 0.8 3.56 ;
    END
  END Y
  PIN VDD
    DIRECTION INPUT ;
    USE POWER ;
    PORT
      LAYER METAL1 ;
        POLYGON 1.32 5.44 1.32 4.64 0.52 4.64 0.52 4.465 0.18 4.465 0.18 4.64 0 4.64 0 5.44 ;
    END
  END VDD
  PIN VSS
    DIRECTION INPUT ;
    USE GROUND ;
    PORT
      LAYER METAL1 ;
        POLYGON 0.52 0.575 0.52 0.4 1.32 0.4 1.32 -0.4 0 -0.4 0 0.4 0.18 0.4 0.18 0.575 ;
    END
  END VSS
END INVX1

MACRO NOR2X1
  CLASS CORE ;
  FOREIGN NOR2X1 ;
  ORIGIN 0 0 ;
  SIZE 1.98 BY 5.04 ;
  SYMMETRY X Y ;
  SITE unit ;
  PIN A
    DIRECTION INPUT ;
    USE SIGNAL ;
    PORT
      LAYER METAL1 ;
        RECT 0.8 1.71 1.39 2.11 ;
    END
  END A
  PIN B
    DIRECTION INPUT ;
    USE SIGNAL ;
    PORT
      LAYER METAL1 ;
        POLYGON 0.84 2.7 0.84 2.38 0.54 2.38 0.54 2.3 0.2 2.3 0.2 2.38 0.14 2.38 0.14 2.7 ;
    END
  END B
  PIN Y
    DIRECTION OUTPUT ;
    USE SIGNAL ;
    PORT
      LAYER METAL1 ;
        POLYGON 1.85 3.25 1.85 1.24 1.16 1.24 1.16 1.13 0.82 1.13 0.82 1.47 1.62 1.47 1.62 2.63 1.46 2.63 1.46 3.25 ;
    END
  END Y
  PIN VDD
    DIRECTION INPUT ;
    USE POWER ;
    PORT
      LAYER METAL1 ;
        POLYGON 1.98 5.44 1.98 4.64 0.52 4.64 0.52 4.465 0.18 4.465 0.18 4.64 0 4.64 0 5.44 ;
    END
  END VDD
  PIN VSS
    DIRECTION INPUT ;
    USE GROUND ;
    PORT
      LAYER METAL1 ;
        POLYGON 1.8 0.575 1.8 0.4 1.98 0.4 1.98 -0.4 0 -0.4 0 0.4 0.18 0.4 0.18 0.575 0.52 0.575 0.52 0.4 1.46 0.4 1.46 0.575 ;
    END
  END VSS
END NOR2X1

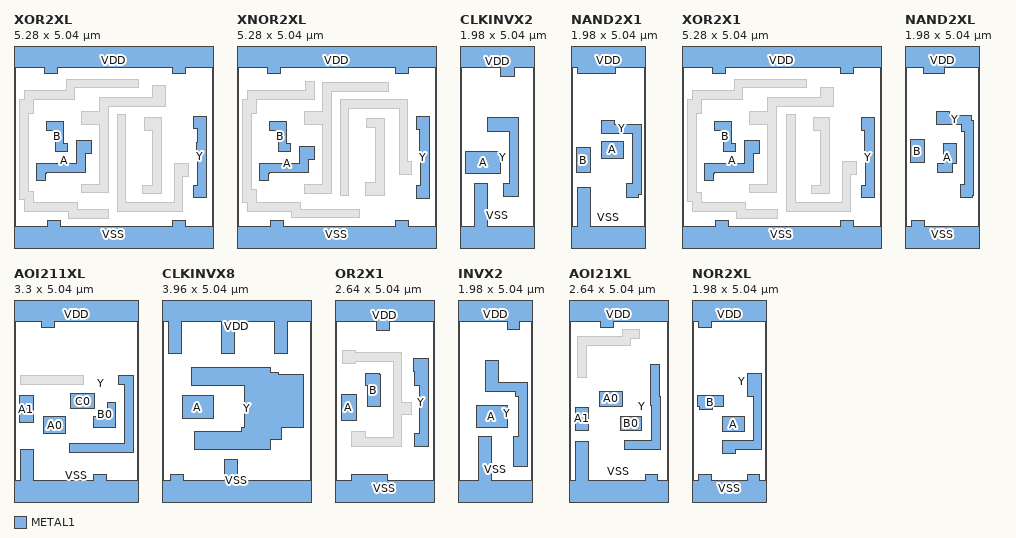
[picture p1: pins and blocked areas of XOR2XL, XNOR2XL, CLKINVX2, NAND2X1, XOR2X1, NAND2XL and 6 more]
MACRO XOR2XL
  CLASS CORE ;
  FOREIGN XOR2XL ;
  ORIGIN 0 0 ;
  SIZE 5.28 BY 5.04 ;
  SYMMETRY X Y ;
  SITE unit ;
  PIN A
    DIRECTION INPUT ;
    USE SIGNAL ;
    PORT
      LAYER METAL1 ;
        POLYGON 2.045 2.68 2.045 2.34 1.89 2.34 1.89 1.845 1.535 1.845 1.535 1.855 0.875 1.855 0.875 1.82 0.84 1.82 0.84 1.63 0.61 1.63 0.61 2.085 1.66 2.085 1.66 2.68 ;
    END
  END A
  PIN B
    DIRECTION INPUT ;
    USE SIGNAL ;
    PORT
      LAYER METAL1 ;
        POLYGON 1.32 3.195 1.32 2.625 1.43 2.625 1.43 2.395 1.09 2.395 1.09 2.965 0.875 2.965 0.875 3.195 ;
    END
  END B
  PIN Y
    DIRECTION OUTPUT ;
    USE SIGNAL ;
    PORT
      LAYER METAL1 ;
        POLYGON 5.1 3.34 5.1 1.17 4.76 1.17 4.76 1.51 4.87 1.51 4.87 2.405 4.835 2.405 4.835 2.635 4.87 2.635 4.87 3 4.76 3 4.76 3.34 ;
    END
  END Y
  PIN VDD
    DIRECTION INPUT ;
    USE POWER ;
    PORT
      LAYER METAL1 ;
        POLYGON 5.28 5.44 5.28 4.64 4.54 4.64 4.54 4.465 4.2 4.465 4.2 4.64 1.15 4.64 1.15 4.465 0.81 4.465 0.81 4.64 0 4.64 0 5.44 ;
    END
  END VDD
  PIN VSS
    DIRECTION INPUT ;
    USE GROUND ;
    PORT
      LAYER METAL1 ;
        POLYGON 4.54 0.575 4.54 0.4 5.28 0.4 5.28 -0.4 0 -0.4 0 0.4 0.885 0.4 0.885 0.575 1.225 0.575 1.225 0.4 4.2 0.4 4.2 0.575 ;
    END
  END VSS
  OBS
    LAYER METAL1 ;
      POLYGON 3.3 4.32 3.3 4.09 1.61 4.09 1.61 3.79 0.52 3.79 0.52 3.4 0.38 3.4 0.38 1.345 0.52 1.345 0.52 1.035 1.685 1.035 1.685 0.86 2.505 0.86 2.505 0.63 1.455 0.63 1.455 0.805 0.29 0.805 0.29 1.115 0.15 1.115 0.15 3.785 0.29 3.785 0.29 4.02 1.38 4.02 1.38 4.32 ;
      POLYGON 4.01 4.16 4.01 3.605 2.505 3.605 2.505 1.305 1.8 1.305 1.8 1.535 2.275 1.535 2.275 3.13 1.8 3.13 1.8 3.47 2.275 3.47 2.275 3.835 3.67 3.835 3.67 4.16 ;
      POLYGON 2.965 3.37 2.965 1.045 4.245 1.045 4.245 2.08 4.635 2.08 4.635 1.74 4.475 1.74 4.475 0.815 2.735 0.815 2.735 3.37 ;
      POLYGON 3.905 3.315 3.905 1.275 3.4 1.275 3.4 1.505 3.675 1.505 3.675 2.95 3.455 2.95 3.455 3.315 ;
  END
END XOR2XL

MACRO XNOR2XL
  CLASS CORE ;
  FOREIGN XNOR2XL ;
  ORIGIN 0 0 ;
  SIZE 5.28 BY 5.04 ;
  SYMMETRY X Y ;
  SITE unit ;
  PIN A
    DIRECTION INPUT ;
    USE SIGNAL ;
    PORT
      LAYER METAL1 ;
        POLYGON 2.045 2.54 2.045 2.18 1.89 2.18 1.89 1.845 1.535 1.845 1.535 1.855 0.875 1.855 0.875 1.82 0.84 1.82 0.84 1.63 0.61 1.63 0.61 2.085 1.66 2.085 1.66 2.54 ;
    END
  END A
  PIN B
    DIRECTION INPUT ;
    USE SIGNAL ;
    PORT
      LAYER METAL1 ;
        POLYGON 1.32 3.195 1.32 2.625 1.43 2.625 1.43 2.395 1.09 2.395 1.09 2.965 0.875 2.965 0.875 3.195 ;
    END
  END B
  PIN Y
    DIRECTION OUTPUT ;
    USE SIGNAL ;
    PORT
      LAYER METAL1 ;
        POLYGON 5.1 3.32 5.1 1.15 4.76 1.15 4.76 1.49 4.87 1.49 4.87 2.405 4.835 2.405 4.835 2.975 4.815 2.975 4.815 2.98 4.76 2.98 4.76 3.32 ;
    END
  END Y
  PIN VDD
    DIRECTION INPUT ;
    USE POWER ;
    PORT
      LAYER METAL1 ;
        POLYGON 5.28 5.44 5.28 4.64 4.54 4.64 4.54 4.465 4.2 4.465 4.2 4.64 1.15 4.64 1.15 4.465 0.81 4.465 0.81 4.64 0 4.64 0 5.44 ;
    END
  END VDD
  PIN VSS
    DIRECTION INPUT ;
    USE GROUND ;
    PORT
      LAYER METAL1 ;
        POLYGON 4.54 0.575 4.54 0.4 5.28 0.4 5.28 -0.4 0 -0.4 0 0.4 0.885 0.4 0.885 0.575 1.225 0.575 1.225 0.4 4.2 0.4 4.2 0.575 ;
    END
  END VSS
  OBS
    LAYER METAL1 ;
      POLYGON 2.045 4.27 2.045 3.79 0.52 3.79 0.52 3.4 0.38 3.4 0.38 1.4 0.52 1.4 0.52 1.035 1.685 1.035 1.685 0.875 3.26 0.875 3.26 0.645 1.455 0.645 1.455 0.805 0.29 0.805 0.29 1.06 0.15 1.06 0.15 3.785 0.29 3.785 0.29 4.02 1.815 4.02 1.815 4.27 ;
      POLYGON 4.01 4.235 4.01 4.005 2.505 4.005 2.505 1.295 1.8 1.295 1.8 1.525 2.275 1.525 2.275 3.13 1.8 3.13 1.8 3.47 2.275 3.47 2.275 4.235 ;
      POLYGON 4.53 3.775 4.53 2.13 4.635 2.13 4.635 1.79 4.3 1.79 4.3 3.545 2.965 3.545 2.965 1.225 2.735 1.225 2.735 3.775 ;
      POLYGON 3.905 3.265 3.905 1.24 3.4 1.24 3.4 1.58 3.675 1.58 3.675 3.035 3.44 3.035 3.44 3.265 ;
  END
END XNOR2XL

MACRO CLKINVX2
  CLASS CORE ;
  FOREIGN CLKINVX2 ;
  ORIGIN 0 0 ;
  SIZE 1.98 BY 5.04 ;
  SYMMETRY X Y ;
  SITE unit ;
  PIN A
    DIRECTION INPUT ;
    USE SIGNAL ;
    PORT
      LAYER METAL1 ;
        RECT 0.14 1.82 1.085 2.41 ;
    END
  END A
  PIN Y
    DIRECTION OUTPUT ;
    USE SIGNAL ;
    PORT
      LAYER METAL1 ;
        POLYGON 1.55 3.305 1.55 1.2 1.155 1.2 1.155 1.54 1.32 1.54 1.32 2.94 0.74 2.94 0.74 3.305 ;
    END
  END Y
  PIN VDD
    DIRECTION INPUT ;
    USE POWER ;
    PORT
      LAYER METAL1 ;
        POLYGON 1.98 5.44 1.98 4.64 1.45 4.64 1.45 4.395 1.07 4.395 1.07 4.64 0 4.64 0 5.44 ;
    END
  END VDD
  PIN VSS
    DIRECTION INPUT ;
    USE GROUND ;
    PORT
      LAYER METAL1 ;
        POLYGON 0.725 1.54 0.725 0.4 1.98 0.4 1.98 -0.4 0 -0.4 0 0.4 0.385 0.4 0.385 1.54 ;
    END
  END VSS
END CLKINVX2

MACRO NAND2X1
  CLASS CORE ;
  FOREIGN NAND2X1 ;
  ORIGIN 0 0 ;
  SIZE 1.98 BY 5.04 ;
  SYMMETRY X Y ;
  SITE unit ;
  PIN A
    DIRECTION INPUT ;
    USE SIGNAL ;
    PORT
      LAYER METAL1 ;
        RECT 0.8 2.225 1.39 2.66 ;
    END
  END A
  PIN B
    DIRECTION INPUT ;
    USE SIGNAL ;
    PORT
      LAYER METAL1 ;
        RECT 0.14 1.84 0.52 2.51 ;
    END
  END B
  PIN Y
    DIRECTION OUTPUT ;
    USE SIGNAL ;
    PORT
      LAYER METAL1 ;
        POLYGON 1.16 3.23 1.16 3.12 1.86 3.12 1.86 1.26 1.8 1.26 1.8 1.185 1.46 1.185 1.46 1.54 1.63 1.54 1.63 2.89 0.82 2.89 0.82 3.23 ;
    END
  END Y
  PIN VDD
    DIRECTION INPUT ;
    USE POWER ;
    PORT
      LAYER METAL1 ;
        POLYGON 1.98 5.44 1.98 4.64 1.185 4.64 1.185 4.465 0.18 4.465 0.18 4.64 0 4.64 0 5.44 ;
    END
  END VDD
  PIN VSS
    DIRECTION INPUT ;
    USE GROUND ;
    PORT
      LAYER METAL1 ;
        POLYGON 0.52 1.44 0.52 0.4 1.98 0.4 1.98 -0.4 0 -0.4 0 0.4 0.18 0.4 0.18 1.44 ;
    END
  END VSS
END NAND2X1

MACRO XOR2X1
  CLASS CORE ;
  FOREIGN XOR2X1 ;
  ORIGIN 0 0 ;
  SIZE 5.28 BY 5.04 ;
  SYMMETRY X Y ;
  SITE unit ;
  PIN A
    DIRECTION INPUT ;
    USE SIGNAL ;
    PORT
      LAYER METAL1 ;
        POLYGON 2.045 2.68 2.045 2.34 1.89 2.34 1.89 1.845 1.535 1.845 1.535 1.855 0.875 1.855 0.875 1.82 0.84 1.82 0.84 1.63 0.61 1.63 0.61 2.085 1.66 2.085 1.66 2.68 ;
    END
  END A
  PIN B
    DIRECTION INPUT ;
    USE SIGNAL ;
    PORT
      LAYER METAL1 ;
        POLYGON 1.32 3.195 1.32 2.625 1.43 2.625 1.43 2.395 1.09 2.395 1.09 2.965 0.875 2.965 0.875 3.195 ;
    END
  END B
  PIN Y
    DIRECTION OUTPUT ;
    USE SIGNAL ;
    PORT
      LAYER METAL1 ;
        POLYGON 5.1 3.31 5.1 1.17 4.76 1.17 4.76 1.51 4.87 1.51 4.87 2.405 4.835 2.405 4.835 2.97 4.76 2.97 4.76 3.31 ;
    END
  END Y
  PIN VDD
    DIRECTION INPUT ;
    USE POWER ;
    PORT
      LAYER METAL1 ;
        POLYGON 5.28 5.44 5.28 4.64 4.54 4.64 4.54 4.465 4.2 4.465 4.2 4.64 1.15 4.64 1.15 4.465 0.81 4.465 0.81 4.64 0 4.64 0 5.44 ;
    END
  END VDD
  PIN VSS
    DIRECTION INPUT ;
    USE GROUND ;
    PORT
      LAYER METAL1 ;
        POLYGON 4.54 0.575 4.54 0.4 5.28 0.4 5.28 -0.4 0 -0.4 0 0.4 0.885 0.4 0.885 0.575 1.225 0.575 1.225 0.4 4.2 0.4 4.2 0.575 ;
    END
  END VSS
  OBS
    LAYER METAL1 ;
      POLYGON 3.3 4.32 3.3 4.09 1.61 4.09 1.61 3.79 0.52 3.79 0.52 3.4 0.38 3.4 0.38 1.315 0.52 1.315 0.52 1.035 1.685 1.035 1.685 0.86 2.545 0.86 2.545 0.63 1.455 0.63 1.455 0.805 0.29 0.805 0.29 1.085 0.15 1.085 0.15 3.785 0.29 3.785 0.29 4.02 1.38 4.02 1.38 4.32 ;
      POLYGON 4.01 4.09 4.01 3.605 2.505 3.605 2.505 1.305 1.8 1.305 1.8 1.535 2.275 1.535 2.275 3.13 1.8 3.13 1.8 3.47 2.275 3.47 2.275 3.835 3.67 3.835 3.67 4.09 ;
      POLYGON 3.005 3.37 3.005 1.045 4.245 1.045 4.245 2.13 4.635 2.13 4.635 1.79 4.475 1.79 4.475 0.815 2.775 0.815 2.775 3.37 ;
      POLYGON 3.905 3.315 3.905 1.275 3.44 1.275 3.44 1.505 3.675 1.505 3.675 2.95 3.495 2.95 3.495 3.315 ;
  END
END XOR2X1

MACRO NAND2XL
  CLASS CORE ;
  FOREIGN NAND2XL ;
  ORIGIN 0 0 ;
  SIZE 1.98 BY 5.04 ;
  SYMMETRY X Y ;
  SITE unit ;
  PIN A
    DIRECTION INPUT ;
    USE SIGNAL ;
    PORT
      LAYER METAL1 ;
        POLYGON 1.36 2.62 1.36 2.075 1.25 2.075 1.25 1.845 0.875 1.845 0.875 2.075 1.02 2.075 1.02 2.62 ;
    END
  END A
  PIN B
    DIRECTION INPUT ;
    USE SIGNAL ;
    PORT
      LAYER METAL1 ;
        RECT 0.14 2.1 0.52 2.71 ;
    END
  END B
  PIN Y
    DIRECTION OUTPUT ;
    USE SIGNAL ;
    PORT
      LAYER METAL1 ;
        POLYGON 1.17 3.46 1.17 3.35 1.765 3.35 1.765 3.235 1.82 3.235 1.82 1.235 1.8 1.235 1.8 1.18 1.46 1.18 1.46 1.52 1.59 1.52 1.59 2.92 1.49 2.92 1.49 3.12 0.83 3.12 0.83 3.46 ;
    END
  END Y
  PIN VDD
    DIRECTION INPUT ;
    USE POWER ;
    PORT
      LAYER METAL1 ;
        POLYGON 1.98 5.44 1.98 4.64 1.06 4.64 1.06 4.465 0.49 4.465 0.49 4.64 0 4.64 0 5.44 ;
    END
  END VDD
  PIN VSS
    DIRECTION INPUT ;
    USE GROUND ;
    PORT
      LAYER METAL1 ;
        POLYGON 0.52 0.575 0.52 0.4 1.98 0.4 1.98 -0.4 0 -0.4 0 0.4 0.18 0.4 0.18 0.575 ;
    END
  END VSS
END NAND2XL

MACRO AOI211XL
  CLASS CORE ;
  FOREIGN AOI211XL ;
  ORIGIN 0 0 ;
  SIZE 3.3 BY 5.04 ;
  SYMMETRY X Y ;
  SITE unit ;
  PIN A0
    DIRECTION INPUT ;
    USE SIGNAL ;
    PORT
      LAYER METAL1 ;
        RECT 0.795 1.65 1.375 2.1 ;
    END
  END A0
  PIN A1
    DIRECTION INPUT ;
    USE SIGNAL ;
    PORT
      LAYER METAL1 ;
        RECT 0.14 1.955 0.52 2.66 ;
    END
  END A1
  PIN B0
    DIRECTION INPUT ;
    USE SIGNAL ;
    PORT
      LAYER METAL1 ;
        POLYGON 2.7 2.485 2.7 1.82 2.115 1.82 2.115 2.1 2.47 2.1 2.47 2.485 ;
    END
  END B0
  PIN C0
    DIRECTION INPUT ;
    USE SIGNAL ;
    PORT
      LAYER METAL1 ;
        RECT 1.51 2.33 2.125 2.71 ;
    END
  END C0
  PIN Y
    DIRECTION OUTPUT ;
    USE SIGNAL ;
    PORT
      LAYER METAL1 ;
        POLYGON 3.16 3.195 3.16 1.15 1.46 1.15 1.46 1.38 2.93 1.38 2.93 2.965 2.78 2.965 2.78 3.195 ;
    END
  END Y
  PIN VDD
    DIRECTION INPUT ;
    USE POWER ;
    PORT
      LAYER METAL1 ;
        POLYGON 3.3 5.44 3.3 4.64 1.08 4.64 1.08 4.465 0.74 4.465 0.74 4.64 0 4.64 0 5.44 ;
    END
  END VDD
  PIN VSS
    DIRECTION INPUT ;
    USE GROUND ;
    PORT
      LAYER METAL1 ;
        POLYGON 0.52 1.24 0.52 0.4 2.12 0.4 2.12 0.575 2.46 0.575 2.46 0.4 3.3 0.4 3.3 -0.4 0 -0.4 0 0.4 0.18 0.4 0.18 1.24 ;
    END
  END VSS
  OBS
    LAYER METAL1 ;
      RECT 0.18 2.955 1.84 3.185 ;
  END
END AOI211XL

MACRO CLKINVX8
  CLASS CORE ;
  FOREIGN CLKINVX8 ;
  ORIGIN 0 0 ;
  SIZE 3.96 BY 5.04 ;
  SYMMETRY X Y ;
  SITE unit ;
  PIN A
    DIRECTION INPUT ;
    USE SIGNAL ;
    PORT
      LAYER METAL1 ;
        RECT 0.54 2.045 1.355 2.66 ;
    END
  END A
  PIN Y
    DIRECTION OUTPUT ;
    USE SIGNAL ;
    PORT
      LAYER METAL1 ;
        POLYGON 2.88 3.41 2.88 3.275 3.085 3.275 3.085 3.22 3.745 3.22 3.745 1.82 3.16 1.82 3.16 1.51 2.88 1.51 2.88 1.235 0.87 1.235 0.87 1.715 2.12 1.715 2.12 1.82 2.195 1.82 2.195 2.93 0.78 2.93 0.78 3.41 ;
    END
  END Y
  PIN VDD
    DIRECTION INPUT ;
    USE POWER ;
    PORT
      LAYER METAL1 ;
        POLYGON 3.96 5.44 3.96 4.64 3.32 4.64 3.32 3.79 2.98 3.79 2.98 4.64 1.915 4.64 1.915 3.79 1.575 3.79 1.575 4.64 0.52 4.64 0.52 3.79 0.18 3.79 0.18 4.64 0 4.64 0 5.44 ;
    END
  END VDD
  PIN VSS
    DIRECTION INPUT ;
    USE GROUND ;
    PORT
      LAYER METAL1 ;
        POLYGON 2.005 0.98 2.005 0.4 3.96 0.4 3.96 -0.4 0 -0.4 0 0.4 0.22 0.4 0.22 0.575 0.56 0.575 0.56 0.4 1.665 0.4 1.665 0.98 ;
    END
  END VSS
END CLKINVX8

MACRO OR2X1
  CLASS CORE ;
  FOREIGN OR2X1 ;
  ORIGIN 0 0 ;
  SIZE 2.64 BY 5.04 ;
  SYMMETRY X Y ;
  SITE unit ;
  PIN A
    DIRECTION INPUT ;
    USE SIGNAL ;
    PORT
      LAYER METAL1 ;
        RECT 0.16 1.99 0.58 2.68 ;
    END
  END A
  PIN B
    DIRECTION INPUT ;
    USE SIGNAL ;
    PORT
      LAYER METAL1 ;
        POLYGON 1.18 3.24 1.18 3.22 1.22 3.22 1.22 2.38 0.86 2.38 0.86 2.94 0.8 2.94 0.8 3.24 ;
    END
  END B
  PIN Y
    DIRECTION OUTPUT ;
    USE SIGNAL ;
    PORT
      LAYER METAL1 ;
        POLYGON 2.48 3.64 2.48 1.32 2.12 1.32 2.12 1.66 2.25 1.66 2.25 2.92 2.12 2.92 2.12 3.3 2.085 3.3 2.085 3.64 ;
    END
  END Y
  PIN VDD
    DIRECTION INPUT ;
    USE POWER ;
    PORT
      LAYER METAL1 ;
        POLYGON 2.64 5.44 2.64 4.64 1.45 4.64 1.45 4.385 1.095 4.385 1.095 4.64 0 4.64 0 5.44 ;
    END
  END VDD
  PIN VSS
    DIRECTION INPUT ;
    USE GROUND ;
    PORT
      LAYER METAL1 ;
        POLYGON 1.39 0.575 1.39 0.4 2.64 0.4 2.64 -0.4 0 -0.4 0 0.4 0.45 0.4 0.45 0.575 ;
    END
  END VSS
  OBS
    LAYER METAL1 ;
      POLYGON 0.54 3.86 0.54 3.805 1.775 3.805 1.775 2.49 2.02 2.49 2.02 2.15 1.775 2.15 1.775 1.315 0.445 1.315 0.445 1.7 0.81 1.7 0.81 1.545 1.545 1.545 1.545 3.575 0.54 3.575 0.54 3.52 0.2 3.52 0.2 3.86 ;
  END
END OR2X1

MACRO INVX2
  CLASS CORE ;
  FOREIGN INVX2 ;
  ORIGIN 0 0 ;
  SIZE 1.98 BY 5.04 ;
  SYMMETRY X Y ;
  SITE unit ;
  PIN A
    DIRECTION INPUT ;
    USE SIGNAL ;
    PORT
      LAYER METAL1 ;
        RECT 0.495 1.82 1.305 2.41 ;
    END
  END A
  PIN Y
    DIRECTION OUTPUT ;
    USE SIGNAL ;
    PORT
      LAYER METAL1 ;
        POLYGON 1.08 3.585 1.08 3.005 1.84 3.005 1.84 0.77 1.46 0.77 1.46 1.58 1.61 1.58 1.61 2.635 1.535 2.635 1.535 2.775 0.74 2.775 0.74 3.585 ;
    END
  END Y
  PIN VDD
    DIRECTION INPUT ;
    USE POWER ;
    PORT
      LAYER METAL1 ;
        POLYGON 1.98 5.44 1.98 4.64 1.64 4.64 1.64 4.465 1.635 4.465 1.635 4.405 1.305 4.405 1.305 4.465 1.3 4.465 1.3 4.64 0 4.64 0 5.44 ;
    END
  END VDD
  PIN VSS
    DIRECTION INPUT ;
    USE GROUND ;
    PORT
      LAYER METAL1 ;
        POLYGON 0.88 1.58 0.88 0.4 1.98 0.4 1.98 -0.4 0 -0.4 0 0.4 0.54 0.4 0.54 1.58 ;
    END
  END VSS
END INVX2

MACRO AOI21XL
  CLASS CORE ;
  FOREIGN AOI21XL ;
  ORIGIN 0 0 ;
  SIZE 2.64 BY 5.04 ;
  SYMMETRY X Y ;
  SITE unit ;
  PIN A0
    DIRECTION INPUT ;
    USE SIGNAL ;
    PORT
      LAYER METAL1 ;
        RECT 0.8 2.38 1.43 2.78 ;
    END
  END A0
  PIN A1
    DIRECTION INPUT ;
    USE SIGNAL ;
    PORT
      LAYER METAL1 ;
        RECT 0.17 1.75 0.52 2.36 ;
    END
  END A1
  PIN B0
    DIRECTION INPUT ;
    USE SIGNAL ;
    PORT
      LAYER METAL1 ;
        RECT 1.365 1.725 1.935 2.1 ;
    END
  END B0
  PIN Y
    DIRECTION OUTPUT ;
    USE SIGNAL ;
    PORT
      LAYER METAL1 ;
        POLYGON 2.39 3.485 2.39 2.635 2.425 2.635 2.425 1.24 1.46 1.24 1.46 1.47 2.195 1.47 2.195 2.405 2.16 2.405 2.16 3.485 ;
    END
  END Y
  PIN VDD
    DIRECTION INPUT ;
    USE POWER ;
    PORT
      LAYER METAL1 ;
        POLYGON 2.64 5.44 2.64 4.64 1.18 4.64 1.18 4.465 0.84 4.465 0.84 4.64 0 4.64 0 5.44 ;
    END
  END VDD
  PIN VSS
    DIRECTION INPUT ;
    USE GROUND ;
    PORT
      LAYER METAL1 ;
        POLYGON 0.52 1.455 0.52 0.4 2.02 0.4 2.02 0.575 2.36 0.575 2.36 0.4 2.64 0.4 2.64 -0.4 0 -0.4 0 0.4 0.18 0.4 0.18 1.455 ;
    END
  END VSS
  OBS
    LAYER METAL1 ;
      POLYGON 1.88 4.41 1.88 4.18 1.64 4.18 1.64 4 0.465 4 0.465 3.145 0.235 3.145 0.235 4.23 1.41 4.23 1.41 4.41 ;
  END
END AOI21XL

MACRO NOR2XL
  CLASS CORE ;
  FOREIGN NOR2XL ;
  ORIGIN 0 0 ;
  SIZE 1.98 BY 5.04 ;
  SYMMETRY X Y ;
  SITE unit ;
  PIN A
    DIRECTION INPUT ;
    USE SIGNAL ;
    PORT
      LAYER METAL1 ;
        RECT 0.8 1.705 1.39 2.11 ;
    END
  END A
  PIN B
    DIRECTION INPUT ;
    USE SIGNAL ;
    PORT
      LAYER METAL1 ;
        POLYGON 0.84 2.66 0.84 2.38 0.54 2.38 0.54 2.3 0.2 2.3 0.2 2.38 0.14 2.38 0.14 2.66 ;
    END
  END B
  PIN Y
    DIRECTION OUTPUT ;
    USE SIGNAL ;
    PORT
      LAYER METAL1 ;
        POLYGON 1.85 3.25 1.85 1.24 1.16 1.24 1.16 1.13 0.82 1.13 0.82 1.47 1.62 1.47 1.62 2.63 1.46 2.63 1.46 3.25 ;
    END
  END Y
  PIN VDD
    DIRECTION INPUT ;
    USE POWER ;
    PORT
      LAYER METAL1 ;
        POLYGON 1.98 5.44 1.98 4.64 0.52 4.64 0.52 4.465 0.18 4.465 0.18 4.64 0 4.64 0 5.44 ;
    END
  END VDD
  PIN VSS
    DIRECTION INPUT ;
    USE GROUND ;
    PORT
      LAYER METAL1 ;
        POLYGON 1.8 0.575 1.8 0.4 1.98 0.4 1.98 -0.4 0 -0.4 0 0.4 0.18 0.4 0.18 0.575 0.52 0.575 0.52 0.4 1.46 0.4 1.46 0.575 ;
    END
  END VSS
END NOR2XL

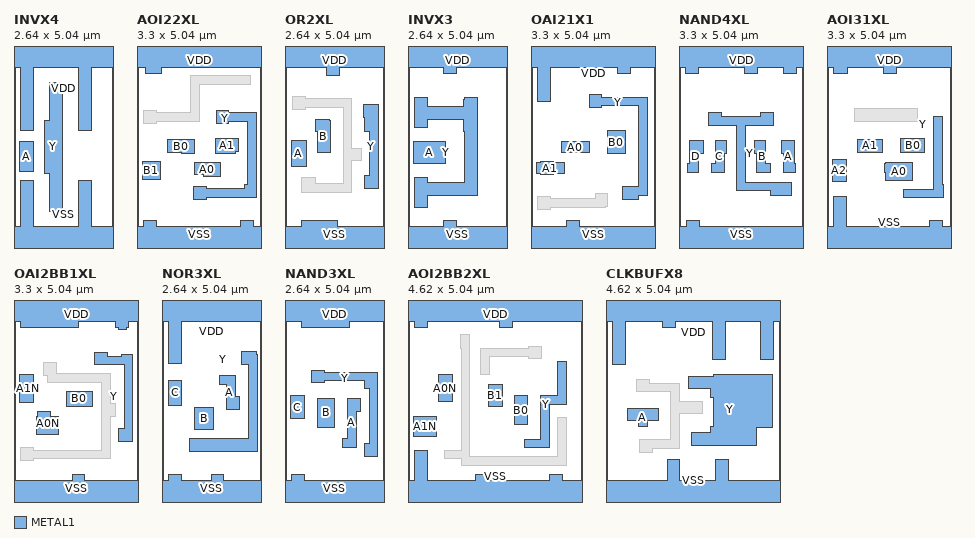
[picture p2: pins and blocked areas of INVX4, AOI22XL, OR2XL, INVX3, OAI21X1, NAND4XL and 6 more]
MACRO INVX4
  CLASS CORE ;
  FOREIGN INVX4 ;
  ORIGIN 0 0 ;
  SIZE 2.64 BY 5.04 ;
  SYMMETRY X Y ;
  SITE unit ;
  PIN A
    DIRECTION INPUT ;
    USE SIGNAL ;
    PORT
      LAYER METAL1 ;
        RECT 0.14 1.875 0.52 2.66 ;
    END
  END A
  PIN Y
    DIRECTION OUTPUT ;
    USE SIGNAL ;
    PORT
      LAYER METAL1 ;
        POLYGON 1.285 4.24 1.285 0.815 0.945 0.815 0.945 1.82 0.8 1.82 0.8 3.22 0.945 3.22 0.945 4.24 ;
    END
  END Y
  PIN VDD
    DIRECTION INPUT ;
    USE POWER ;
    PORT
      LAYER METAL1 ;
        POLYGON 2.64 5.44 2.64 4.64 2.045 4.64 2.045 2.96 1.705 2.96 1.705 4.64 0.52 4.64 0.52 2.96 0.18 2.96 0.18 4.64 0 4.64 0 5.44 ;
    END
  END VDD
  PIN VSS
    DIRECTION INPUT ;
    USE GROUND ;
    PORT
      LAYER METAL1 ;
        POLYGON 2.045 1.625 2.045 0.4 2.64 0.4 2.64 -0.4 0 -0.4 0 0.4 0.18 0.4 0.18 1.625 0.52 1.625 0.52 0.4 1.705 0.4 1.705 1.625 ;
    END
  END VSS
END INVX4

MACRO AOI22XL
  CLASS CORE ;
  FOREIGN AOI22XL ;
  ORIGIN 0 0 ;
  SIZE 3.3 BY 5.04 ;
  SYMMETRY X Y ;
  SITE unit ;
  PIN A0
    DIRECTION INPUT ;
    USE SIGNAL ;
    PORT
      LAYER METAL1 ;
        POLYGON 2.21 2.1 2.21 1.785 2.205 1.785 2.205 1.73 1.765 1.73 1.765 1.785 1.53 1.785 1.53 2.1 ;
    END
  END A0
  PIN A1
    DIRECTION INPUT ;
    USE SIGNAL ;
    PORT
      LAYER METAL1 ;
        POLYGON 2.68 2.74 2.68 2.4 2.625 2.4 2.625 2.36 2.08 2.36 2.08 2.74 ;
    END
  END A1
  PIN B0
    DIRECTION INPUT ;
    USE SIGNAL ;
    PORT
      LAYER METAL1 ;
        POLYGON 1.53 2.725 1.53 2.35 1.19 2.35 1.19 2.38 0.8 2.38 0.8 2.725 ;
    END
  END B0
  PIN B1
    DIRECTION INPUT ;
    USE SIGNAL ;
    PORT
      LAYER METAL1 ;
        RECT 0.14 1.665 0.62 2.145 ;
    END
  END B1
  PIN Y
    DIRECTION OUTPUT ;
    USE SIGNAL ;
    PORT
      LAYER METAL1 ;
        POLYGON 2.44 3.48 2.44 3.425 3.16 3.425 3.16 1.185 1.84 1.185 1.84 1.13 1.5 1.13 1.5 1.47 1.84 1.47 1.84 1.415 2.855 1.415 2.855 1.515 2.93 1.515 2.93 3.195 2.44 3.195 2.44 3.14 2.1 3.14 2.1 3.48 ;
    END
  END Y
  PIN VDD
    DIRECTION INPUT ;
    USE POWER ;
    PORT
      LAYER METAL1 ;
        POLYGON 3.3 5.44 3.3 4.64 0.645 4.64 0.645 4.465 0.23 4.465 0.23 4.64 0 4.64 0 5.44 ;
    END
  END VDD
  PIN VSS
    DIRECTION INPUT ;
    USE GROUND ;
    PORT
      LAYER METAL1 ;
        POLYGON 3.08 0.575 3.08 0.4 3.3 0.4 3.3 -0.4 0 -0.4 0 0.4 0.18 0.4 0.18 0.575 0.52 0.575 0.52 0.4 2.74 0.4 2.74 0.575 ;
    END
  END VSS
  OBS
    LAYER METAL1 ;
      POLYGON 3.01 4.405 3.01 4.175 1.66 4.175 1.66 3.2 0.52 3.2 0.52 3.145 0.18 3.145 0.18 3.485 0.52 3.485 0.52 3.43 1.43 3.43 1.43 4.405 ;
  END
END AOI22XL

MACRO OR2XL
  CLASS CORE ;
  FOREIGN OR2XL ;
  ORIGIN 0 0 ;
  SIZE 2.64 BY 5.04 ;
  SYMMETRY X Y ;
  SITE unit ;
  PIN A
    DIRECTION INPUT ;
    USE SIGNAL ;
    PORT
      LAYER METAL1 ;
        RECT 0.16 1.99 0.58 2.68 ;
    END
  END A
  PIN B
    DIRECTION INPUT ;
    USE SIGNAL ;
    PORT
      LAYER METAL1 ;
        POLYGON 1.18 3.24 1.18 3.22 1.22 3.22 1.22 2.38 0.86 2.38 0.86 2.94 0.8 2.94 0.8 3.24 ;
    END
  END B
  PIN Y
    DIRECTION OUTPUT ;
    USE SIGNAL ;
    PORT
      LAYER METAL1 ;
        POLYGON 2.48 3.64 2.48 1.43 2.12 1.43 2.12 1.77 2.25 1.77 2.25 2.92 2.12 2.92 2.12 3.3 2.085 3.3 2.085 3.64 ;
    END
  END Y
  PIN VDD
    DIRECTION INPUT ;
    USE POWER ;
    PORT
      LAYER METAL1 ;
        POLYGON 2.64 5.44 2.64 4.64 1.45 4.64 1.45 4.41 1.11 4.41 1.11 4.64 0 4.64 0 5.44 ;
    END
  END VDD
  PIN VSS
    DIRECTION INPUT ;
    USE GROUND ;
    PORT
      LAYER METAL1 ;
        POLYGON 1.39 0.575 1.39 0.4 2.64 0.4 2.64 -0.4 0 -0.4 0 0.4 0.45 0.4 0.45 0.575 ;
    END
  END VSS
  OBS
    LAYER METAL1 ;
      POLYGON 0.54 3.86 0.54 3.805 1.775 3.805 1.775 2.49 2.02 2.49 2.02 2.15 1.775 2.15 1.775 1.315 0.445 1.315 0.445 1.7 0.81 1.7 0.81 1.545 1.545 1.545 1.545 3.575 0.54 3.575 0.54 3.52 0.2 3.52 0.2 3.86 ;
  END
END OR2XL

MACRO INVX3
  CLASS CORE ;
  FOREIGN INVX3 ;
  ORIGIN 0 0 ;
  SIZE 2.64 BY 5.04 ;
  SYMMETRY X Y ;
  SITE unit ;
  PIN A
    DIRECTION INPUT ;
    USE SIGNAL ;
    PORT
      LAYER METAL1 ;
        RECT 0.14 2.07 1.005 2.66 ;
    END
  END A
  PIN Y
    DIRECTION OUTPUT ;
    USE SIGNAL ;
    PORT
      LAYER METAL1 ;
        POLYGON 1.845 3.835 1.845 1.24 0.525 1.24 0.525 0.905 0.185 0.905 0.185 1.715 0.525 1.715 0.525 1.58 1.505 1.58 1.505 2.94 1.46 2.94 1.46 3.245 0.525 3.245 0.525 3.025 0.185 3.025 0.185 3.835 0.525 3.835 0.525 3.585 1.46 3.585 1.46 3.78 1.505 3.78 1.505 3.835 ;
    END
  END Y
  PIN VDD
    DIRECTION INPUT ;
    USE POWER ;
    PORT
      LAYER METAL1 ;
        POLYGON 2.64 5.44 2.64 4.64 1.285 4.64 1.285 4.465 0.945 4.465 0.945 4.64 0 4.64 0 5.44 ;
    END
  END VDD
  PIN VSS
    DIRECTION INPUT ;
    USE GROUND ;
    PORT
      LAYER METAL1 ;
        POLYGON 1.285 0.575 1.285 0.4 2.64 0.4 2.64 -0.4 0 -0.4 0 0.4 0.945 0.4 0.945 0.575 ;
    END
  END VSS
END INVX3

MACRO OAI21X1
  CLASS CORE ;
  FOREIGN OAI21X1 ;
  ORIGIN 0 0 ;
  SIZE 3.3 BY 5.04 ;
  SYMMETRY X Y ;
  SITE unit ;
  PIN A0
    DIRECTION INPUT ;
    USE SIGNAL ;
    PORT
      LAYER METAL1 ;
        RECT 0.8 2.38 1.56 2.66 ;
    END
  END A0
  PIN A1
    DIRECTION INPUT ;
    USE SIGNAL ;
    PORT
      LAYER METAL1 ;
        POLYGON 0.6 2.13 0.6 2.1 0.88 2.1 0.88 1.82 0.6 1.82 0.6 1.79 0.26 1.79 0.26 1.82 0.14 1.82 0.14 2.1 0.26 2.1 0.26 2.13 ;
    END
  END A1
  PIN B0
    DIRECTION INPUT ;
    USE SIGNAL ;
    PORT
      LAYER METAL1 ;
        POLYGON 2.5 2.955 2.5 2.35 2.02 2.35 2.02 2.69 2.03 2.69 2.03 2.955 ;
    END
  END B0
  PIN Y
    DIRECTION OUTPUT ;
    USE SIGNAL ;
    PORT
      LAYER METAL1 ;
        POLYGON 1.88 3.9 1.88 3.845 3.085 3.845 3.085 1.235 2.86 1.235 2.86 1.125 2.42 1.125 2.42 1.465 2.855 1.465 2.855 3.615 1.88 3.615 1.88 3.56 1.54 3.56 1.54 3.9 ;
    END
  END Y
  PIN VDD
    DIRECTION INPUT ;
    USE POWER ;
    PORT
      LAYER METAL1 ;
        POLYGON 3.3 5.44 3.3 4.64 2.64 4.64 2.64 4.465 2.3 4.465 2.3 4.64 0.52 4.64 0.52 3.74 0.18 3.74 0.18 4.64 0 4.64 0 5.44 ;
    END
  END VDD
  PIN VSS
    DIRECTION INPUT ;
    USE GROUND ;
    PORT
      LAYER METAL1 ;
        POLYGON 1.28 0.575 1.28 0.4 3.3 0.4 3.3 -0.4 0 -0.4 0 0.4 0.94 0.4 0.94 0.575 ;
    END
  END VSS
  OBS
    LAYER METAL1 ;
      POLYGON 2.04 1.275 2.04 0.935 1.985 0.935 1.985 0.915 0.52 0.915 0.52 0.86 0.18 0.86 0.18 1.2 0.52 1.2 0.52 1.145 1.7 1.145 1.7 1.275 ;
  END
END OAI21X1

MACRO NAND4XL
  CLASS CORE ;
  FOREIGN NAND4XL ;
  ORIGIN 0 0 ;
  SIZE 3.3 BY 5.04 ;
  SYMMETRY X Y ;
  SITE unit ;
  PIN A
    DIRECTION INPUT ;
    USE SIGNAL ;
    PORT
      LAYER METAL1 ;
        POLYGON 3.07 2.685 3.07 2.075 3.085 2.075 3.085 1.845 2.78 1.845 2.78 2.345 2.73 2.345 2.73 2.685 ;
    END
  END A
  PIN B
    DIRECTION INPUT ;
    USE SIGNAL ;
    PORT
      LAYER METAL1 ;
        POLYGON 2.285 2.685 2.285 2.075 2.425 2.075 2.425 1.845 2.055 1.845 2.055 2.345 1.995 2.345 1.995 2.685 ;
    END
  END B
  PIN C
    DIRECTION INPUT ;
    USE SIGNAL ;
    PORT
      LAYER METAL1 ;
        POLYGON 1.27 2.685 1.27 2.345 1.21 2.345 1.21 1.845 0.875 1.845 0.875 2.075 0.98 2.075 0.98 2.685 ;
    END
  END C
  PIN D
    DIRECTION INPUT ;
    USE SIGNAL ;
    PORT
      LAYER METAL1 ;
        POLYGON 0.645 2.685 0.645 2.345 0.52 2.345 0.52 1.845 0.215 1.845 0.215 2.075 0.29 2.075 0.29 2.685 ;
    END
  END D
  PIN Y
    DIRECTION OUTPUT ;
    USE SIGNAL ;
    PORT
      LAYER METAL1 ;
        POLYGON 2.51 3.435 2.51 3.095 1.765 3.095 1.765 1.585 2.975 1.585 2.975 1.245 2.42 1.245 2.42 1.355 1.535 1.355 1.535 3.095 0.79 3.095 0.79 3.435 1.13 3.435 1.13 3.325 2.17 3.325 2.17 3.435 ;
    END
  END Y
  PIN VDD
    DIRECTION INPUT ;
    USE POWER ;
    PORT
      LAYER METAL1 ;
        POLYGON 3.3 5.44 3.3 4.64 3.12 4.64 3.12 4.465 2.78 4.465 2.78 4.64 2.085 4.64 2.085 4.465 1.73 4.465 1.73 4.64 0.52 4.64 0.52 4.465 0.18 4.465 0.18 4.64 0 4.64 0 5.44 ;
    END
  END VDD
  PIN VSS
    DIRECTION INPUT ;
    USE GROUND ;
    PORT
      LAYER METAL1 ;
        POLYGON 0.535 0.575 0.535 0.4 3.3 0.4 3.3 -0.4 0 -0.4 0 0.4 0.195 0.4 0.195 0.575 ;
    END
  END VSS
END NAND4XL

MACRO AOI31XL
  CLASS CORE ;
  FOREIGN AOI31XL ;
  ORIGIN 0 0 ;
  SIZE 3.3 BY 5.04 ;
  SYMMETRY X Y ;
  SITE unit ;
  PIN A0
    DIRECTION INPUT ;
    USE SIGNAL ;
    PORT
      LAYER METAL1 ;
        POLYGON 2.28 2.1 2.28 1.64 1.54 1.64 1.54 1.845 1.535 1.845 1.535 2.075 1.54 2.075 1.54 2.1 ;
    END
  END A0
  PIN A1
    DIRECTION INPUT ;
    USE SIGNAL ;
    PORT
      LAYER METAL1 ;
        RECT 0.8 2.38 1.485 2.73 ;
    END
  END A1
  PIN A2
    DIRECTION INPUT ;
    USE SIGNAL ;
    PORT
      LAYER METAL1 ;
        RECT 0.14 1.6 0.52 2.185 ;
    END
  END A2
  PIN B0
    DIRECTION INPUT ;
    USE SIGNAL ;
    PORT
      LAYER METAL1 ;
        POLYGON 2.585 2.755 2.585 2.375 2.355 2.375 2.355 2.38 1.96 2.38 1.96 2.755 ;
    END
  END B0
  PIN Y
    DIRECTION OUTPUT ;
    USE SIGNAL ;
    PORT
      LAYER METAL1 ;
        POLYGON 3.065 3.32 3.065 1.515 3.085 1.515 3.085 1.175 2.02 1.175 2.02 1.405 2.835 1.405 2.835 3.32 ;
    END
  END Y
  PIN VDD
    DIRECTION INPUT ;
    USE POWER ;
    PORT
      LAYER METAL1 ;
        POLYGON 3.3 5.44 3.3 4.64 1.84 4.64 1.84 4.465 1.5 4.465 1.5 4.64 0.545 4.64 0.545 4.465 0.175 4.465 0.175 4.64 0 4.64 0 5.44 ;
    END
  END VDD
  PIN VSS
    DIRECTION INPUT ;
    USE GROUND ;
    PORT
      LAYER METAL1 ;
        POLYGON 0.52 1.22 0.52 0.4 2.725 0.4 2.725 0.575 3.065 0.575 3.065 0.4 3.3 0.4 3.3 -0.4 0 -0.4 0 0.4 0.18 0.4 0.18 1.22 ;
    END
  END VSS
  OBS
    LAYER METAL1 ;
      RECT 0.74 3.19 2.4 3.53 ;
  END
END AOI31XL

MACRO OAI2BB1XL
  CLASS CORE ;
  FOREIGN OAI2BB1XL ;
  ORIGIN 0 0 ;
  SIZE 3.3 BY 5.04 ;
  SYMMETRY X Y ;
  SITE unit ;
  PIN A0N
    DIRECTION INPUT ;
    USE SIGNAL ;
    PORT
      LAYER METAL1 ;
        POLYGON 0.955 2.235 0.955 2.1 1.18 2.1 1.18 1.63 0.61 1.63 0.61 2.1 0.615 2.1 0.615 2.235 ;
    END
  END A0N
  PIN A1N
    DIRECTION INPUT ;
    USE SIGNAL ;
    PORT
      LAYER METAL1 ;
        RECT 0.14 2.485 0.52 3.225 ;
    END
  END A1N
  PIN B0
    DIRECTION INPUT ;
    USE SIGNAL ;
    PORT
      LAYER METAL1 ;
        RECT 1.385 2.38 2.075 2.78 ;
    END
  END B0
  PIN Y
    DIRECTION OUTPUT ;
    USE SIGNAL ;
    PORT
      LAYER METAL1 ;
        POLYGON 2.485 3.815 2.485 3.705 2.855 3.705 2.855 3.755 3.155 3.755 3.155 1.44 2.78 1.44 2.78 1.78 2.925 1.78 2.925 3.475 2.145 3.475 2.145 3.815 ;
    END
  END Y
  PIN VDD
    DIRECTION INPUT ;
    USE POWER ;
    PORT
      LAYER METAL1 ;
        POLYGON 3.3 5.44 3.3 4.64 3.045 4.64 3.045 4.465 2.99 4.465 2.99 4.41 2.76 4.41 2.76 4.465 2.705 4.465 2.705 4.64 1.72 4.64 1.72 4.465 0.18 4.465 0.18 4.64 0 4.64 0 5.44 ;
    END
  END VDD
  PIN VSS
    DIRECTION INPUT ;
    USE GROUND ;
    PORT
      LAYER METAL1 ;
        POLYGON 1.88 0.575 1.88 0.4 3.3 0.4 3.3 -0.4 0 -0.4 0 0.4 1.54 0.4 1.54 0.575 ;
    END
  END VSS
  OBS
    LAYER METAL1 ;
      POLYGON 1.12 3.54 1.12 3.24 2.55 3.24 2.55 2.45 2.695 2.45 2.695 2.1 2.55 2.1 2.55 0.985 0.52 0.985 0.52 0.935 0.18 0.935 0.18 1.275 0.52 1.275 0.52 1.215 2.32 1.215 2.32 3.01 0.89 3.01 0.89 3.2 0.78 3.2 0.78 3.54 ;
  END
END OAI2BB1XL

MACRO NOR3XL
  CLASS CORE ;
  FOREIGN NOR3XL ;
  ORIGIN 0 0 ;
  SIZE 2.64 BY 5.04 ;
  SYMMETRY X Y ;
  SITE unit ;
  PIN A
    DIRECTION INPUT ;
    USE SIGNAL ;
    PORT
      LAYER METAL1 ;
        POLYGON 1.95 3.195 1.95 2.645 2.06 2.645 2.06 2.305 1.72 2.305 1.72 2.965 1.535 2.965 1.535 3.195 ;
    END
  END A
  PIN B
    DIRECTION INPUT ;
    USE SIGNAL ;
    PORT
      LAYER METAL1 ;
        RECT 0.875 1.77 1.36 2.355 ;
    END
  END B
  PIN C
    DIRECTION INPUT ;
    USE SIGNAL ;
    PORT
      LAYER METAL1 ;
        RECT 0.18 2.405 0.52 3.07 ;
    END
  END C
  PIN Y
    DIRECTION OUTPUT ;
    USE SIGNAL ;
    PORT
      LAYER METAL1 ;
        POLYGON 2.51 3.835 2.51 3.755 2.52 3.755 2.52 1.185 0.74 1.185 0.74 1.525 2.29 1.525 2.29 3.48 2.1 3.48 2.1 3.835 ;
    END
  END Y
  PIN VDD
    DIRECTION INPUT ;
    USE POWER ;
    PORT
      LAYER METAL1 ;
        POLYGON 2.64 5.44 2.64 4.64 0.52 4.64 0.52 3.505 0.18 3.505 0.18 4.64 0 4.64 0 5.44 ;
    END
  END VDD
  PIN VSS
    DIRECTION INPUT ;
    USE GROUND ;
    PORT
      LAYER METAL1 ;
        POLYGON 1.64 0.575 1.64 0.4 2.64 0.4 2.64 -0.4 0 -0.4 0 0.4 0.18 0.4 0.18 0.575 0.52 0.575 0.52 0.4 1.3 0.4 1.3 0.575 ;
    END
  END VSS
END NOR3XL

MACRO NAND3XL
  CLASS CORE ;
  FOREIGN NAND3XL ;
  ORIGIN 0 0 ;
  SIZE 2.64 BY 5.04 ;
  SYMMETRY X Y ;
  SITE unit ;
  PIN A
    DIRECTION INPUT ;
    USE SIGNAL ;
    PORT
      LAYER METAL1 ;
        POLYGON 1.995 2.59 1.995 2.25 1.885 2.25 1.885 1.285 1.535 1.285 1.535 1.515 1.655 1.515 1.655 2.59 ;
    END
  END A
  PIN B
    DIRECTION INPUT ;
    USE SIGNAL ;
    PORT
      LAYER METAL1 ;
        RECT 0.875 1.82 1.315 2.59 ;
    END
  END B
  PIN C
    DIRECTION INPUT ;
    USE SIGNAL ;
    PORT
      LAYER METAL1 ;
        RECT 0.14 2.045 0.52 2.66 ;
    END
  END C
  PIN Y
    DIRECTION OUTPUT ;
    USE SIGNAL ;
    PORT
      LAYER METAL1 ;
        POLYGON 1.05 3.34 1.05 3.285 2.46 3.285 2.46 1.055 2.12 1.055 2.12 1.395 2.23 1.395 2.23 2.86 2.12 2.86 2.12 3.055 1.05 3.055 1.05 3 0.71 3 0.71 3.34 ;
    END
  END Y
  PIN VDD
    DIRECTION INPUT ;
    USE POWER ;
    PORT
      LAYER METAL1 ;
        POLYGON 2.64 5.44 2.64 4.64 1.72 4.64 1.72 4.465 0.45 4.465 0.45 4.64 0 4.64 0 5.44 ;
    END
  END VDD
  PIN VSS
    DIRECTION INPUT ;
    USE GROUND ;
    PORT
      LAYER METAL1 ;
        POLYGON 0.52 0.575 0.52 0.4 2.64 0.4 2.64 -0.4 0 -0.4 0 0.4 0.18 0.4 0.18 0.575 ;
    END
  END VSS
END NAND3XL

MACRO AOI2BB2XL
  CLASS CORE ;
  FOREIGN AOI2BB2XL ;
  ORIGIN 0 0 ;
  SIZE 4.62 BY 5.04 ;
  SYMMETRY X Y ;
  SITE unit ;
  PIN B0
    DIRECTION INPUT ;
    USE SIGNAL ;
    PORT
      LAYER METAL1 ;
        RECT 2.815 1.885 3.16 2.66 ;
    END
  END B0
  PIN B1
    DIRECTION INPUT ;
    USE SIGNAL ;
    PORT
      LAYER METAL1 ;
        RECT 2.135 2.38 2.5 2.965 ;
    END
  END B1
  PIN A0N
    DIRECTION INPUT ;
    USE SIGNAL ;
    PORT
      LAYER METAL1 ;
        RECT 0.8 2.495 1.18 3.22 ;
    END
  END A0N
  PIN A1N
    DIRECTION INPUT ;
    USE SIGNAL ;
    PORT
      LAYER METAL1 ;
        RECT 0.14 1.59 0.755 2.1 ;
    END
  END A1N
  PIN Y
    DIRECTION OUTPUT ;
    USE SIGNAL ;
    PORT
      LAYER METAL1 ;
        POLYGON 4.205 3.555 4.205 2.43 3.745 2.43 3.745 1.275 3.09 1.275 3.09 1.505 3.515 1.505 3.515 2.66 3.975 2.66 3.975 3.555 ;
    END
  END Y
  PIN VDD
    DIRECTION INPUT ;
    USE POWER ;
    PORT
      LAYER METAL1 ;
        POLYGON 4.62 5.44 4.62 4.64 2.78 4.64 2.78 4.465 2.44 4.465 2.44 4.64 0.52 4.64 0.52 4.465 0.18 4.465 0.18 4.64 0 4.64 0 5.44 ;
    END
  END VDD
  PIN VSS
    DIRECTION INPUT ;
    USE GROUND ;
    PORT
      LAYER METAL1 ;
        POLYGON 0.52 1.22 0.52 0.4 1.78 0.4 1.78 0.575 2.12 0.575 2.12 0.4 3.76 0.4 3.76 0.575 4.1 0.575 4.1 0.4 4.62 0.4 4.62 -0.4 0 -0.4 0 0.4 0.18 0.4 0.18 1.22 ;
    END
  END VSS
  OBS
    LAYER METAL1 ;
      POLYGON 1.64 4.28 1.64 1.04 3.975 1.04 3.975 2.095 4.205 2.095 4.205 0.81 1.41 0.81 1.41 0.99 0.98 0.99 0.98 1.22 1.41 1.22 1.41 3.92 1.395 3.92 1.395 4.28 ;
      POLYGON 3.54 3.975 3.54 3.635 3.2 3.635 3.2 3.69 2.165 3.69 2.165 3.215 1.935 3.215 1.935 3.92 3.2 3.92 3.2 3.975 ;
  END
END AOI2BB2XL

MACRO CLKBUFX8
  CLASS CORE ;
  FOREIGN CLKBUFX8 ;
  ORIGIN 0 0 ;
  SIZE 4.62 BY 5.04 ;
  SYMMETRY X Y ;
  SITE unit ;
  PIN A
    DIRECTION INPUT ;
    USE SIGNAL ;
    PORT
      LAYER METAL1 ;
        POLYGON 1.39 2.33 1.39 1.99 1.105 1.99 1.105 1.845 0.875 1.845 0.875 1.99 0.57 1.99 0.57 2.33 ;
    END
  END A
  PIN Y
    DIRECTION OUTPUT ;
    USE SIGNAL ;
    PORT
      LAYER METAL1 ;
        POLYGON 4.405 3.22 4.405 1.82 4 1.82 4 1.35 2.26 1.35 2.26 1.69 2.78 1.69 2.78 1.85 2.855 1.85 2.855 2.625 2.78 2.625 2.78 2.84 2.18 2.84 2.18 3.18 2.855 3.18 2.855 3.22 ;
    END
  END Y
  PIN VDD
    DIRECTION INPUT ;
    USE POWER ;
    PORT
      LAYER METAL1 ;
        POLYGON 4.62 5.44 4.62 4.64 4.44 4.64 4.44 3.62 4.1 3.62 4.1 4.64 3.16 4.64 3.16 3.62 2.82 3.62 2.82 4.64 1.84 4.64 1.84 4.465 1.5 4.465 1.5 4.64 0.52 4.64 0.52 3.48 0.18 3.48 0.18 4.64 0 4.64 0 5.44 ;
    END
  END VDD
  PIN VSS
    DIRECTION INPUT ;
    USE GROUND ;
    PORT
      LAYER METAL1 ;
        POLYGON 3.24 0.965 3.24 0.4 4.62 0.4 4.62 -0.4 0 -0.4 0 0.4 1.62 0.4 1.62 0.965 1.96 0.965 1.96 0.4 2.9 0.4 2.9 0.965 ;
    END
  END VSS
  OBS
    LAYER METAL1 ;
      POLYGON 1.16 3.1 1.16 2.99 1.95 2.99 1.95 2.52 2.55 2.52 2.55 2.18 1.95 2.18 1.95 1.26 1.24 1.26 1.24 1.15 0.9 1.15 0.9 1.49 1.72 1.49 1.72 2.76 0.82 2.76 0.82 3.1 ;
  END
END CLKBUFX8

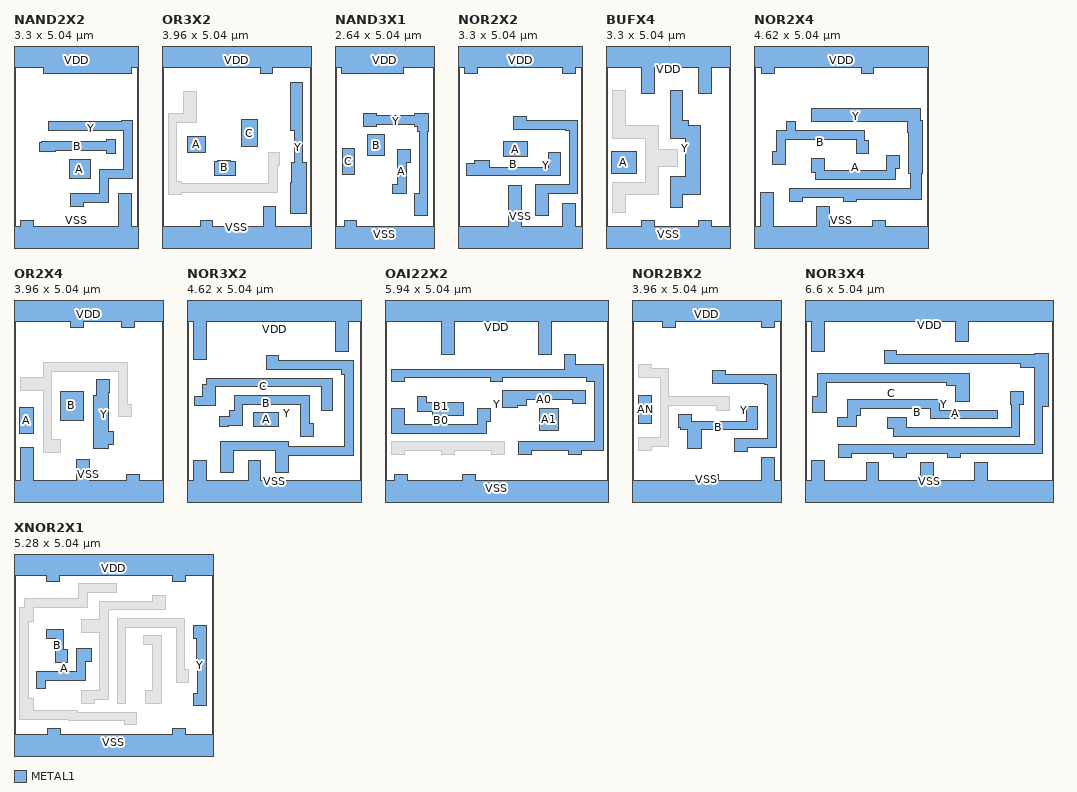
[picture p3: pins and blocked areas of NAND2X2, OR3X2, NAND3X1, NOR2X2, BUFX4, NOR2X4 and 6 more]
MACRO NAND2X2
  CLASS CORE ;
  FOREIGN NAND2X2 ;
  ORIGIN 0 0 ;
  SIZE 3.3 BY 5.04 ;
  SYMMETRY X Y ;
  SITE unit ;
  PIN A
    DIRECTION INPUT ;
    USE SIGNAL ;
    PORT
      LAYER METAL1 ;
        RECT 1.46 1.68 2.02 2.185 ;
    END
  END A
  PIN B
    DIRECTION INPUT ;
    USE SIGNAL ;
    PORT
      LAYER METAL1 ;
        POLYGON 2.68 2.71 2.68 2.345 2.45 2.345 2.45 2.425 1.105 2.425 1.105 2.405 0.68 2.405 0.68 2.635 0.735 2.635 0.735 2.655 2.45 2.655 2.45 2.71 ;
    END
  END B
  PIN Y
    DIRECTION OUTPUT ;
    USE SIGNAL ;
    PORT
      LAYER METAL1 ;
        POLYGON 3.145 3.235 3.145 1.69 2.495 1.69 2.495 1.045 1.84 1.045 1.84 0.935 1.5 0.935 1.5 1.275 2.195 1.275 2.195 1.285 2.265 1.285 2.265 1.92 2.915 1.92 2.915 2.955 0.92 2.955 0.92 3.185 2.855 3.185 2.855 3.235 ;
    END
  END Y
  PIN VDD
    DIRECTION INPUT ;
    USE POWER ;
    PORT
      LAYER METAL1 ;
        POLYGON 3.3 5.44 3.3 4.64 3.12 4.64 3.12 4.465 0.77 4.465 0.77 4.64 0 4.64 0 5.44 ;
    END
  END VDD
  PIN VSS
    DIRECTION INPUT ;
    USE GROUND ;
    PORT
      LAYER METAL1 ;
        POLYGON 3.12 1.275 3.12 0.4 3.3 0.4 3.3 -0.4 0 -0.4 0 0.4 0.18 0.4 0.18 0.575 0.52 0.575 0.52 0.4 2.78 0.4 2.78 1.275 ;
    END
  END VSS
END NAND2X2

MACRO OR3X2
  CLASS CORE ;
  FOREIGN OR3X2 ;
  ORIGIN 0 0 ;
  SIZE 3.96 BY 5.04 ;
  SYMMETRY X Y ;
  SITE unit ;
  PIN A
    DIRECTION INPUT ;
    USE SIGNAL ;
    PORT
      LAYER METAL1 ;
        RECT 0.67 2.38 1.16 2.805 ;
    END
  END A
  PIN B
    DIRECTION INPUT ;
    USE SIGNAL ;
    PORT
      LAYER METAL1 ;
        POLYGON 1.82 2.175 1.82 2.13 1.94 2.13 1.94 1.775 1.38 1.775 1.38 2.13 1.48 2.13 1.48 2.175 ;
    END
  END B
  PIN C
    DIRECTION INPUT ;
    USE SIGNAL ;
    PORT
      LAYER METAL1 ;
        RECT 2.11 2.525 2.52 3.255 ;
    END
  END C
  PIN Y
    DIRECTION OUTPUT ;
    USE SIGNAL ;
    PORT
      LAYER METAL1 ;
        POLYGON 3.74 4.24 3.74 2.1 3.82 2.1 3.82 0.765 3.4 0.765 3.4 1.575 3.44 1.575 3.44 2.1 3.51 2.1 3.51 2.96 3.4 2.96 3.4 4.24 ;
    END
  END Y
  PIN VDD
    DIRECTION INPUT ;
    USE POWER ;
    PORT
      LAYER METAL1 ;
        POLYGON 3.96 5.44 3.96 4.64 2.94 4.64 2.94 4.465 2.6 4.465 2.6 4.64 0 4.64 0 5.44 ;
    END
  END VDD
  PIN VSS
    DIRECTION INPUT ;
    USE GROUND ;
    PORT
      LAYER METAL1 ;
        POLYGON 3.02 0.95 3.02 0.4 3.96 0.4 3.96 -0.4 0 -0.4 0 0.4 1.01 0.4 1.01 0.575 1.35 0.575 1.35 0.4 2.68 0.4 2.68 0.95 ;
    END
  END VSS
  OBS
    LAYER METAL1 ;
      POLYGON 0.92 3.985 0.92 3.175 0.395 3.175 0.395 1.6 0.53 1.6 0.53 1.545 2.835 1.545 2.835 2.385 3.105 2.385 3.105 2.02 3.065 2.02 3.065 1.315 0.53 1.315 0.53 1.26 0.165 1.26 0.165 3.405 0.58 3.405 0.58 3.985 ;
  END
END OR3X2

MACRO NAND3X1
  CLASS CORE ;
  FOREIGN NAND3X1 ;
  ORIGIN 0 0 ;
  SIZE 2.64 BY 5.04 ;
  SYMMETRY X Y ;
  SITE unit ;
  PIN A
    DIRECTION INPUT ;
    USE SIGNAL ;
    PORT
      LAYER METAL1 ;
        POLYGON 1.995 2.445 1.995 2.105 1.885 2.105 1.885 1.285 1.535 1.285 1.535 1.515 1.655 1.515 1.655 2.445 ;
    END
  END A
  PIN B
    DIRECTION INPUT ;
    USE SIGNAL ;
    PORT
      LAYER METAL1 ;
        RECT 0.875 2.285 1.315 2.84 ;
    END
  END B
  PIN C
    DIRECTION INPUT ;
    USE SIGNAL ;
    PORT
      LAYER METAL1 ;
        RECT 0.19 1.785 0.53 2.48 ;
    END
  END C
  PIN Y
    DIRECTION OUTPUT ;
    USE SIGNAL ;
    PORT
      LAYER METAL1 ;
        POLYGON 2.47 3.41 2.47 2.92 2.46 2.92 2.46 0.7 2.12 0.7 2.12 1.29 2.23 1.29 2.23 2.92 2.19 2.92 2.19 3.07 2.12 3.07 2.12 3.125 1.105 3.125 1.105 3.07 0.765 3.07 0.765 3.41 1.105 3.41 1.105 3.355 2.12 3.355 2.12 3.41 ;
    END
  END Y
  PIN VDD
    DIRECTION INPUT ;
    USE POWER ;
    PORT
      LAYER METAL1 ;
        POLYGON 2.64 5.44 2.64 4.64 1.82 4.64 1.82 4.465 0.18 4.465 0.18 4.64 0 4.64 0 5.44 ;
    END
  END VDD
  PIN VSS
    DIRECTION INPUT ;
    USE GROUND ;
    PORT
      LAYER METAL1 ;
        POLYGON 0.58 0.575 0.58 0.4 2.64 0.4 2.64 -0.4 0 -0.4 0 0.4 0.24 0.4 0.24 0.575 ;
    END
  END VSS
END NAND3X1

MACRO NOR2X2
  CLASS CORE ;
  FOREIGN NOR2X2 ;
  ORIGIN 0 0 ;
  SIZE 3.3 BY 5.04 ;
  SYMMETRY X Y ;
  SITE unit ;
  PIN A
    DIRECTION INPUT ;
    USE SIGNAL ;
    PORT
      LAYER METAL1 ;
        RECT 1.2 2.26 1.84 2.66 ;
    END
  END A
  PIN B
    DIRECTION INPUT ;
    USE SIGNAL ;
    PORT
      LAYER METAL1 ;
        POLYGON 2.72 2.37 2.72 1.755 0.215 1.755 0.215 2.075 0.44 2.075 0.44 2.175 0.84 2.175 0.84 1.985 2.39 1.985 2.39 2.37 ;
    END
  END B
  PIN Y
    DIRECTION OUTPUT ;
    USE SIGNAL ;
    PORT
      LAYER METAL1 ;
        POLYGON 1.82 3.33 1.82 3.22 3.16 3.22 3.16 3.195 3.18 3.195 3.18 1.295 2.4 1.295 2.4 0.715 2.06 0.715 2.06 1.525 2.95 1.525 2.95 2.965 2.855 2.965 2.855 2.99 1.48 2.99 1.48 3.33 ;
    END
  END Y
  PIN VDD
    DIRECTION INPUT ;
    USE POWER ;
    PORT
      LAYER METAL1 ;
        POLYGON 3.3 5.44 3.3 4.64 3.12 4.64 3.12 4.465 2.78 4.465 2.78 4.64 0.52 4.64 0.52 4.465 0.18 4.465 0.18 4.64 0 4.64 0 5.44 ;
    END
  END VDD
  PIN VSS
    DIRECTION INPUT ;
    USE GROUND ;
    PORT
      LAYER METAL1 ;
        POLYGON 1.68 1.49 1.68 0.4 2.78 0.4 2.78 1.02 3.12 1.02 3.12 0.4 3.3 0.4 3.3 -0.4 0 -0.4 0 0.4 1.34 0.4 1.34 1.49 ;
    END
  END VSS
END NOR2X2

MACRO BUFX4
  CLASS CORE ;
  FOREIGN BUFX4 ;
  ORIGIN 0 0 ;
  SIZE 3.3 BY 5.04 ;
  SYMMETRY X Y ;
  SITE unit ;
  PIN A
    DIRECTION INPUT ;
    USE SIGNAL ;
    PORT
      LAYER METAL1 ;
        RECT 0.14 1.82 0.8 2.395 ;
    END
  END A
  PIN Y
    DIRECTION OUTPUT ;
    USE SIGNAL ;
    PORT
      LAYER METAL1 ;
        POLYGON 2.04 4.02 2.04 3.22 2.2 3.22 2.2 3.08 2.5 3.08 2.5 1.26 2.04 1.26 2.04 0.92 1.7 0.92 1.7 1.73 2.12 1.73 2.12 2.74 1.7 2.74 1.7 4.02 ;
    END
  END Y
  PIN VDD
    DIRECTION INPUT ;
    USE POWER ;
    PORT
      LAYER METAL1 ;
        POLYGON 3.3 5.44 3.3 4.64 2.8 4.64 2.8 3.94 2.46 3.94 2.46 4.64 1.28 4.64 1.28 3.94 0.94 3.94 0.94 4.64 0 4.64 0 5.44 ;
    END
  END VDD
  PIN VSS
    DIRECTION INPUT ;
    USE GROUND ;
    PORT
      LAYER METAL1 ;
        POLYGON 2.8 0.575 2.8 0.4 3.3 0.4 3.3 -0.4 0 -0.4 0 0.4 0.94 0.4 0.94 0.575 1.28 0.575 1.28 0.4 2.46 0.4 2.46 0.575 ;
    END
  END VSS
  OBS
    LAYER METAL1 ;
      POLYGON 0.52 4.02 0.52 3.08 1.38 3.08 1.38 2.455 1.89 2.455 1.89 2.005 1.38 2.005 1.38 1.25 0.52 1.25 0.52 0.78 0.18 0.78 0.18 1.59 1.04 1.59 1.04 2.74 0.18 2.74 0.18 4.02 ;
  END
END BUFX4

MACRO NOR2X4
  CLASS CORE ;
  FOREIGN NOR2X4 ;
  ORIGIN 0 0 ;
  SIZE 4.62 BY 5.04 ;
  SYMMETRY X Y ;
  SITE unit ;
  PIN A
    DIRECTION INPUT ;
    USE SIGNAL ;
    PORT
      LAYER METAL1 ;
        POLYGON 3.86 2.29 3.86 1.95 3.75 1.95 3.75 1.655 1.63 1.655 1.63 1.845 1.535 1.845 1.535 1.975 1.52 1.975 1.52 2.205 1.86 2.205 1.86 1.885 3.52 1.885 3.52 2.29 ;
    END
  END A
  PIN B
    DIRECTION INPUT ;
    USE SIGNAL ;
    PORT
      LAYER METAL1 ;
        POLYGON 1.105 3.195 1.105 2.96 2.94 2.96 2.94 2.695 3.05 2.695 3.05 2.355 2.71 2.355 2.71 2.73 0.83 2.73 0.83 2.065 0.49 2.065 0.49 2.405 0.6 2.405 0.6 2.97 0.875 2.97 0.875 3.195 ;
    END
  END B
  PIN Y
    DIRECTION OUTPUT ;
    USE SIGNAL ;
    PORT
      LAYER METAL1 ;
        POLYGON 4.42 3.53 4.42 3.22 4.48 3.22 4.48 1.82 4.44 1.82 4.44 1.115 2.72 1.115 2.72 1.075 2.38 1.075 2.38 1.185 1.28 1.185 1.28 1.075 0.94 1.075 0.94 1.415 4.14 1.415 4.14 1.82 4.1 1.82 4.1 2.91 4.08 2.91 4.08 3.19 1.52 3.19 1.52 3.53 ;
    END
  END Y
  PIN VDD
    DIRECTION INPUT ;
    USE POWER ;
    PORT
      LAYER METAL1 ;
        POLYGON 4.62 5.44 4.62 4.64 3.18 4.64 3.18 4.465 2.84 4.465 2.84 4.64 0.54 4.64 0.54 4.465 0.2 4.465 0.2 4.64 0 4.64 0 5.44 ;
    END
  END VDD
  PIN VSS
    DIRECTION INPUT ;
    USE GROUND ;
    PORT
      LAYER METAL1 ;
        POLYGON 0.52 1.315 0.52 0.4 1.66 0.4 1.66 0.95 2 0.95 2 0.4 3.14 0.4 3.14 0.575 3.48 0.575 3.48 0.4 4.62 0.4 4.62 -0.4 0 -0.4 0 0.4 0.18 0.4 0.18 1.315 ;
    END
  END VSS
END NOR2X4

MACRO OR2X4
  CLASS CORE ;
  FOREIGN OR2X4 ;
  ORIGIN 0 0 ;
  SIZE 3.96 BY 5.04 ;
  SYMMETRY X Y ;
  SITE unit ;
  PIN A
    DIRECTION INPUT ;
    USE SIGNAL ;
    PORT
      LAYER METAL1 ;
        RECT 0.14 1.645 0.52 2.335 ;
    END
  END A
  PIN B
    DIRECTION INPUT ;
    USE SIGNAL ;
    PORT
      LAYER METAL1 ;
        RECT 1.235 2.01 1.84 2.785 ;
    END
  END B
  PIN Y
    DIRECTION OUTPUT ;
    USE SIGNAL ;
    PORT
      LAYER METAL1 ;
        POLYGON 2.52 3.08 2.52 2.74 2.505 2.74 2.505 2.62 2.5 2.62 2.5 1.7 2.64 1.7 2.64 1.36 2.5 1.36 2.5 1.26 2.12 1.26 2.12 2.66 2.18 2.66 2.18 3.08 ;
    END
  END Y
  PIN VDD
    DIRECTION INPUT ;
    USE POWER ;
    PORT
      LAYER METAL1 ;
        POLYGON 3.96 5.44 3.96 4.64 3.2 4.64 3.2 4.465 2.86 4.465 2.86 4.64 1.84 4.64 1.84 4.465 1.5 4.465 1.5 4.64 0 4.64 0 5.44 ;
    END
  END VDD
  PIN VSS
    DIRECTION INPUT ;
    USE GROUND ;
    PORT
      LAYER METAL1 ;
        POLYGON 0.52 1.28 0.52 0.4 1.66 0.4 1.66 0.96 2 0.96 2 0.4 2.98 0.4 2.98 0.575 3.32 0.575 3.32 0.4 3.96 0.4 3.96 -0.4 0 -0.4 0 0.4 0.18 0.4 0.18 1.28 ;
    END
  END VSS
  OBS
    LAYER METAL1 ;
      POLYGON 3.01 3.54 3.01 2.44 3.12 2.44 3.12 2.1 2.78 2.1 2.78 3.31 1 3.31 1 1.5 1.24 1.5 1.24 1.16 0.77 1.16 0.77 2.81 0.18 2.81 0.18 3.15 0.77 3.15 0.77 3.54 ;
  END
END OR2X4

MACRO NOR3X2
  CLASS CORE ;
  FOREIGN NOR3X2 ;
  ORIGIN 0 0 ;
  SIZE 4.62 BY 5.04 ;
  SYMMETRY X Y ;
  SITE unit ;
  PIN A
    DIRECTION INPUT ;
    USE SIGNAL ;
    PORT
      LAYER METAL1 ;
        RECT 1.77 1.845 2.425 2.205 ;
    END
  END A
  PIN B
    DIRECTION INPUT ;
    USE SIGNAL ;
    PORT
      LAYER METAL1 ;
        POLYGON 3.245 2.665 3.245 1.925 3.35 1.925 3.35 1.585 3.01 1.585 3.01 1.925 3.015 1.925 3.015 2.435 1.48 2.435 1.48 1.925 1.475 1.925 1.475 1.87 1.105 1.87 1.105 1.845 0.875 1.845 0.875 2.1 1.14 2.1 1.14 2.265 1.25 2.265 1.25 2.665 ;
    END
  END B
  PIN C
    DIRECTION INPUT ;
    USE SIGNAL ;
    PORT
      LAYER METAL1 ;
        POLYGON 3.865 3.125 3.865 2.255 3.58 2.255 3.58 2.895 0.76 2.895 0.76 2.405 0.205 2.405 0.205 2.635 0.42 2.635 0.42 2.97 0.53 2.97 0.53 3.125 ;
    END
  END C
  PIN Y
    DIRECTION OUTPUT ;
    USE SIGNAL ;
    PORT
      LAYER METAL1 ;
        POLYGON 2.44 3.74 2.44 3.59 4.405 3.59 4.405 1.07 2.68 1.07 2.68 0.635 2.34 0.635 2.34 1.215 1.24 1.215 1.24 0.635 0.9 0.635 0.9 1.445 2.68 1.445 2.68 1.3 4.175 1.3 4.175 3.22 4.1 3.22 4.1 3.36 2.1 3.36 2.1 3.74 ;
    END
  END Y
  PIN VDD
    DIRECTION INPUT ;
    USE POWER ;
    PORT
      LAYER METAL1 ;
        POLYGON 4.62 5.44 4.62 4.64 4.28 4.64 4.28 3.82 3.94 3.82 3.94 4.64 0.52 4.64 0.52 3.615 0.18 3.615 0.18 4.64 0 4.64 0 5.44 ;
    END
  END VDD
  PIN VSS
    DIRECTION INPUT ;
    USE GROUND ;
    PORT
      LAYER METAL1 ;
        POLYGON 1.96 0.95 1.96 0.4 4.62 0.4 4.62 -0.4 0 -0.4 0 0.4 0.18 0.4 0.18 0.95 0.52 0.95 0.52 0.4 1.62 0.4 1.62 0.95 ;
    END
  END VSS
END NOR3X2

MACRO OAI22X2
  CLASS CORE ;
  FOREIGN OAI22X2 ;
  ORIGIN 0 0 ;
  SIZE 5.94 BY 5.04 ;
  SYMMETRY X Y ;
  SITE unit ;
  PIN A0
    DIRECTION INPUT ;
    USE SIGNAL ;
    PORT
      LAYER METAL1 ;
        POLYGON 5.325 2.79 5.325 2.45 4.985 2.45 4.985 2.56 3.745 2.56 3.745 2.405 3.52 2.405 3.52 2.35 3.13 2.35 3.13 2.79 ;
    END
  END A0
  PIN A1
    DIRECTION INPUT ;
    USE SIGNAL ;
    PORT
      LAYER METAL1 ;
        RECT 4.1 1.73 4.6 2.325 ;
    END
  END A1
  PIN B0
    DIRECTION INPUT ;
    USE SIGNAL ;
    PORT
      LAYER METAL1 ;
        POLYGON 2.8 2.325 2.8 1.985 2.685 1.985 2.685 1.67 0.18 1.67 0.18 2.325 0.52 2.325 0.52 1.9 2.455 1.9 2.455 2.27 2.46 2.27 2.46 2.325 ;
    END
  END B0
  PIN B1
    DIRECTION INPUT ;
    USE SIGNAL ;
    PORT
      LAYER METAL1 ;
        POLYGON 1.105 2.635 1.105 2.475 2.07 2.475 2.07 2.135 1.26 2.135 1.26 2.245 0.875 2.245 0.875 2.635 ;
    END
  END B1
  PIN Y
    DIRECTION OUTPUT ;
    USE SIGNAL ;
    PORT
      LAYER METAL1 ;
        POLYGON 5.065 3.755 5.065 3.5 5.785 3.5 5.785 1.21 5.2 1.21 5.2 1.1 4.86 1.1 4.86 1.21 3.88 1.21 3.88 1.1 3.54 1.1 3.54 1.44 5.555 1.44 5.555 3.025 5.35 3.025 5.35 3.135 3.13 3.135 3.13 3.025 2.79 3.025 2.79 3.135 0.52 3.135 0.52 3.025 0.18 3.025 0.18 3.365 4.76 3.365 4.76 3.755 ;
    END
  END Y
  PIN VDD
    DIRECTION INPUT ;
    USE POWER ;
    PORT
      LAYER METAL1 ;
        POLYGON 5.94 5.44 5.94 4.64 4.41 4.64 4.41 3.765 4.07 3.765 4.07 4.64 1.84 4.64 1.84 3.765 1.5 3.765 1.5 4.64 0 4.64 0 5.44 ;
    END
  END VDD
  PIN VSS
    DIRECTION INPUT ;
    USE GROUND ;
    PORT
      LAYER METAL1 ;
        POLYGON 2.4 0.575 2.4 0.4 5.94 0.4 5.94 -0.4 0 -0.4 0 0.4 0.26 0.4 0.26 0.575 0.6 0.575 0.6 0.4 2.06 0.4 2.06 0.575 ;
    END
  END VSS
  OBS
    LAYER METAL1 ;
      POLYGON 3.16 1.435 3.16 1.095 2.82 1.095 2.82 1.205 1.84 1.205 1.84 1.095 1.5 1.095 1.5 1.205 0.52 1.205 0.52 1.095 0.18 1.095 0.18 1.435 ;
  END
END OAI22X2

MACRO NOR2BX2
  CLASS CORE ;
  FOREIGN NOR2BX2 ;
  ORIGIN 0 0 ;
  SIZE 3.96 BY 5.04 ;
  SYMMETRY X Y ;
  SITE unit ;
  PIN AN
    DIRECTION INPUT ;
    USE SIGNAL ;
    PORT
      LAYER METAL1 ;
        RECT 0.18 1.92 0.52 2.66 ;
    END
  END AN
  PIN B
    DIRECTION INPUT ;
    USE SIGNAL ;
    PORT
      LAYER METAL1 ;
        POLYGON 3.34 2.375 3.34 1.755 1.84 1.755 1.84 1.26 1.46 1.26 1.46 1.755 1.285 1.755 1.285 1.82 1.23 1.82 1.23 2.16 1.57 2.16 1.57 1.985 3.05 1.985 3.05 2.375 ;
    END
  END B
  PIN Y
    DIRECTION OUTPUT ;
    USE SIGNAL ;
    PORT
      LAYER METAL1 ;
        POLYGON 2.48 3.33 2.48 3.22 3.82 3.22 3.82 1.295 3.06 1.295 3.06 1.185 2.72 1.185 2.72 1.525 3.59 1.525 3.59 2.965 3.515 2.965 3.515 2.99 2.14 2.99 2.14 3.33 ;
    END
  END Y
  PIN VDD
    DIRECTION INPUT ;
    USE POWER ;
    PORT
      LAYER METAL1 ;
        POLYGON 3.96 5.44 3.96 4.64 3.78 4.64 3.78 4.465 3.44 4.465 3.44 4.64 1.16 4.64 1.16 4.465 0.82 4.465 0.82 4.64 0 4.64 0 5.44 ;
    END
  END VDD
  PIN VSS
    DIRECTION INPUT ;
    USE GROUND ;
    PORT
      LAYER METAL1 ;
        POLYGON 3.78 1.02 3.78 0.4 3.96 0.4 3.96 -0.4 0 -0.4 0 0.4 1.95 0.4 1.95 0.575 2.29 0.575 2.29 0.4 3.44 0.4 3.44 1.02 ;
    END
  END VSS
  OBS
    LAYER METAL1 ;
      POLYGON 0.52 3.48 0.52 3.37 0.98 3.37 0.98 2.63 2.58 2.63 2.58 2.26 2.24 2.26 2.24 2.4 0.98 2.4 0.98 1.31 0.52 1.31 0.52 1.2 0.18 1.2 0.18 1.54 0.75 1.54 0.75 3.14 0.18 3.14 0.18 3.48 ;
  END
END NOR2BX2

MACRO NOR3X4
  CLASS CORE ;
  FOREIGN NOR3X4 ;
  ORIGIN 0 0 ;
  SIZE 6.6 BY 5.04 ;
  SYMMETRY X Y ;
  SITE unit ;
  PIN A
    DIRECTION INPUT ;
    USE SIGNAL ;
    PORT
      LAYER METAL1 ;
        POLYGON 5.8 2.78 5.8 2.44 5.695 2.44 5.695 1.59 2.34 1.59 2.34 1.8 2.195 1.8 2.195 2.075 2.34 2.075 2.34 2.085 2.68 2.085 2.68 1.82 5.465 1.82 5.465 2.44 5.46 2.44 5.46 2.78 ;
    END
  END A
  PIN B
    DIRECTION INPUT ;
    USE SIGNAL ;
    PORT
      LAYER METAL1 ;
        POLYGON 3.56 2.56 3.56 2.28 5.095 2.28 5.095 2.05 3.33 2.05 3.33 2.33 1.48 2.33 1.48 2.13 1.37 2.13 1.37 1.845 0.875 1.845 0.875 2.075 1.14 2.075 1.14 2.56 ;
    END
  END B
  PIN C
    DIRECTION INPUT ;
    USE SIGNAL ;
    PORT
      LAYER METAL1 ;
        POLYGON 4.36 3.25 4.36 2.51 4.005 2.51 4.005 2.94 3.745 2.94 3.745 3.02 0.56 3.02 0.56 2.21 0.205 2.21 0.205 2.635 0.33 2.635 0.33 3.25 ;
    END
  END C
  PIN Y
    DIRECTION OUTPUT ;
    USE SIGNAL ;
    PORT
      LAYER METAL1 ;
        POLYGON 2.44 3.855 2.44 3.745 6.08 3.745 6.08 3.78 6.46 3.78 6.46 2.38 6.31 2.38 6.31 1.125 4.12 1.125 4.12 1.015 3.78 1.015 3.78 1.125 2.68 1.125 2.68 1.015 2.34 1.015 2.34 1.125 1.24 1.125 1.24 1.015 0.9 1.015 0.9 1.355 6.08 1.355 6.08 3.4 5.725 3.4 5.725 3.515 2.1 3.515 2.1 3.855 ;
    END
  END Y
  PIN VDD
    DIRECTION INPUT ;
    USE POWER ;
    PORT
      LAYER METAL1 ;
        POLYGON 6.6 5.44 6.6 4.64 4.33 4.64 4.33 4.09 3.99 4.09 3.99 4.64 0.52 4.64 0.52 3.84 0.18 3.84 0.18 4.64 0 4.64 0 5.44 ;
    END
  END VDD
  PIN VSS
    DIRECTION INPUT ;
    USE GROUND ;
    PORT
      LAYER METAL1 ;
        POLYGON 0.52 0.95 0.52 0.4 1.62 0.4 1.62 0.895 1.96 0.895 1.96 0.4 3.06 0.4 3.06 0.895 3.4 0.895 3.4 0.4 4.5 0.4 4.5 0.895 4.84 0.895 4.84 0.4 6.6 0.4 6.6 -0.4 0 -0.4 0 0.4 0.18 0.4 0.18 0.95 ;
    END
  END VSS
END NOR3X4

MACRO XNOR2X1
  CLASS CORE ;
  FOREIGN XNOR2X1 ;
  ORIGIN 0 0 ;
  SIZE 5.28 BY 5.04 ;
  SYMMETRY X Y ;
  SITE unit ;
  PIN A
    DIRECTION INPUT ;
    USE SIGNAL ;
    PORT
      LAYER METAL1 ;
        POLYGON 2.045 2.68 2.045 2.34 1.89 2.34 1.89 1.845 1.535 1.845 1.535 1.855 0.875 1.855 0.875 1.845 0.84 1.845 0.84 1.63 0.61 1.63 0.61 2.085 1.66 2.085 1.66 2.68 ;
    END
  END A
  PIN B
    DIRECTION INPUT ;
    USE SIGNAL ;
    PORT
      LAYER METAL1 ;
        POLYGON 1.32 3.195 1.32 2.67 1.43 2.67 1.43 2.33 1.09 2.33 1.09 2.965 0.875 2.965 0.875 3.195 ;
    END
  END B
  PIN Y
    DIRECTION OUTPUT ;
    USE SIGNAL ;
    PORT
      LAYER METAL1 ;
        POLYGON 5.1 3.31 5.1 1.17 4.76 1.17 4.76 1.51 4.87 1.51 4.87 2.405 4.835 2.405 4.835 2.97 4.76 2.97 4.76 3.31 ;
    END
  END Y
  PIN VDD
    DIRECTION INPUT ;
    USE POWER ;
    PORT
      LAYER METAL1 ;
        POLYGON 5.28 5.44 5.28 4.64 4.54 4.64 4.54 4.465 4.2 4.465 4.2 4.64 1.2 4.64 1.2 4.465 0.86 4.465 0.86 4.64 0 4.64 0 5.44 ;
    END
  END VDD
  PIN VSS
    DIRECTION INPUT ;
    USE GROUND ;
    PORT
      LAYER METAL1 ;
        POLYGON 4.54 0.575 4.54 0.4 5.28 0.4 5.28 -0.4 0 -0.4 0 0.4 0.885 0.4 0.885 0.575 1.225 0.575 1.225 0.4 4.2 0.4 4.2 0.575 ;
    END
  END VSS
  OBS
    LAYER METAL1 ;
      POLYGON 2.71 4.41 2.71 4.18 1.945 4.18 1.945 3.79 0.52 3.79 0.52 3.4 0.38 3.4 0.38 1.37 0.52 1.37 0.52 1.035 1.685 1.035 1.685 1.005 3.26 1.005 3.26 0.665 2.92 0.665 2.92 0.775 1.455 0.775 1.455 0.805 0.15 0.805 0.15 3.785 0.29 3.785 0.29 4.02 1.715 4.02 1.715 4.41 ;
      POLYGON 4.01 4.09 4.01 3.72 2.505 3.72 2.505 1.35 2.14 1.35 2.14 1.24 1.8 1.24 1.8 1.58 2.275 1.58 2.275 3.13 1.8 3.13 1.8 3.47 2.275 3.47 2.275 3.95 3.67 3.95 3.67 4.09 ;
      POLYGON 4.53 3.49 4.53 2.13 4.635 2.13 4.635 1.79 4.3 1.79 4.3 3.26 2.965 3.26 2.965 1.24 2.735 1.24 2.735 3.49 ;
      POLYGON 3.905 3.025 3.905 1.24 3.495 1.24 3.495 1.58 3.675 1.58 3.675 2.795 3.44 2.795 3.44 3.025 ;
  END
END XNOR2X1

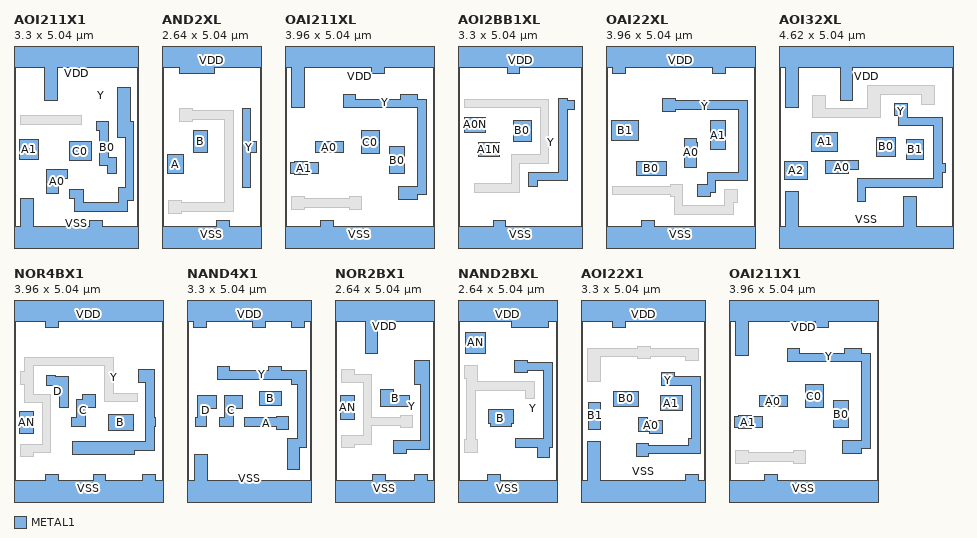
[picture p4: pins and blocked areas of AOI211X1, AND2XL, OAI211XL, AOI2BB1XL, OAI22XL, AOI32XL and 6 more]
MACRO AOI211X1
  CLASS CORE ;
  FOREIGN AOI211X1 ;
  ORIGIN 0 0 ;
  SIZE 3.3 BY 5.04 ;
  SYMMETRY X Y ;
  SITE unit ;
  PIN A0
    DIRECTION INPUT ;
    USE SIGNAL ;
    PORT
      LAYER METAL1 ;
        POLYGON 1.43 1.91 1.43 1.68 1.18 1.68 1.18 1.285 0.875 1.285 0.875 1.91 ;
    END
  END A0
  PIN A1
    DIRECTION INPUT ;
    USE SIGNAL ;
    PORT
      LAYER METAL1 ;
        RECT 0.14 2.2 0.645 2.71 ;
    END
  END A1
  PIN B0
    DIRECTION INPUT ;
    USE SIGNAL ;
    PORT
      LAYER METAL1 ;
        POLYGON 2.51 3.195 2.51 2.25 2.72 2.25 2.72 1.83 2.49 1.83 2.49 2.02 2.28 2.02 2.28 2.965 2.195 2.965 2.195 3.195 ;
    END
  END B0
  PIN C0
    DIRECTION INPUT ;
    USE SIGNAL ;
    PORT
      LAYER METAL1 ;
        RECT 1.46 2.165 2.045 2.66 ;
    END
  END C0
  PIN Y
    DIRECTION OUTPUT ;
    USE SIGNAL ;
    PORT
      LAYER METAL1 ;
        POLYGON 3.08 4.095 3.08 3.195 3.18 3.195 3.18 1.095 3.01 1.095 3.01 0.805 1.605 0.805 1.605 1.15 1.46 1.15 1.46 1.38 1.835 1.38 1.835 1.035 2.78 1.035 2.78 1.435 2.95 1.435 2.95 2.775 2.74 2.775 2.74 4.095 ;
    END
  END Y
  PIN VDD
    DIRECTION INPUT ;
    USE POWER ;
    PORT
      LAYER METAL1 ;
        POLYGON 3.3 5.44 3.3 4.64 1.16 4.64 1.16 3.755 0.82 3.755 0.82 4.64 0 4.64 0 5.44 ;
    END
  END VDD
  PIN VSS
    DIRECTION INPUT ;
    USE GROUND ;
    PORT
      LAYER METAL1 ;
        POLYGON 0.52 1.155 0.52 0.4 2.005 0.4 2.005 0.575 2.345 0.575 2.345 0.4 3.3 0.4 3.3 -0.4 0 -0.4 0 0.4 0.18 0.4 0.18 1.155 ;
    END
  END VSS
  OBS
    LAYER METAL1 ;
      RECT 0.18 3.115 1.8 3.345 ;
  END
END AOI211X1

MACRO AND2XL
  CLASS CORE ;
  FOREIGN AND2XL ;
  ORIGIN 0 0 ;
  SIZE 2.64 BY 5.04 ;
  SYMMETRY X Y ;
  SITE unit ;
  PIN A
    DIRECTION INPUT ;
    USE SIGNAL ;
    PORT
      LAYER METAL1 ;
        RECT 0.15 1.82 0.565 2.315 ;
    END
  END A
  PIN B
    DIRECTION INPUT ;
    USE SIGNAL ;
    PORT
      LAYER METAL1 ;
        RECT 0.825 2.37 1.205 2.95 ;
    END
  END B
  PIN Y
    DIRECTION OUTPUT ;
    USE SIGNAL ;
    PORT
      LAYER METAL1 ;
        POLYGON 2.355 3.55 2.355 2.66 2.5 2.66 2.5 2.38 2.355 2.38 2.355 1.445 2.125 1.445 2.125 3.55 ;
    END
  END Y
  PIN VDD
    DIRECTION INPUT ;
    USE POWER ;
    PORT
      LAYER METAL1 ;
        POLYGON 2.64 5.44 2.64 4.64 1.4 4.64 1.4 4.465 0.46 4.465 0.46 4.64 0 4.64 0 5.44 ;
    END
  END VDD
  PIN VSS
    DIRECTION INPUT ;
    USE GROUND ;
    PORT
      LAYER METAL1 ;
        POLYGON 1.79 0.575 1.79 0.4 2.64 0.4 2.64 -0.4 0 -0.4 0 0.4 1.45 0.4 1.45 0.575 ;
    END
  END VSS
  OBS
    LAYER METAL1 ;
      POLYGON 0.8 3.53 0.8 3.475 1.89 3.475 1.89 0.82 0.52 0.82 0.52 0.765 0.18 0.765 0.18 1.105 0.52 1.105 0.52 1.05 1.66 1.05 1.66 3.245 0.8 3.245 0.8 3.19 0.46 3.19 0.46 3.53 ;
  END
END AND2XL

MACRO OAI211XL
  CLASS CORE ;
  FOREIGN OAI211XL ;
  ORIGIN 0 0 ;
  SIZE 3.96 BY 5.04 ;
  SYMMETRY X Y ;
  SITE unit ;
  PIN A0
    DIRECTION INPUT ;
    USE SIGNAL ;
    PORT
      LAYER METAL1 ;
        RECT 0.8 2.38 1.56 2.66 ;
    END
  END A0
  PIN A1
    DIRECTION INPUT ;
    USE SIGNAL ;
    PORT
      LAYER METAL1 ;
        POLYGON 0.6 2.13 0.6 2.1 0.88 2.1 0.88 1.82 0.6 1.82 0.6 1.79 0.26 1.79 0.26 1.82 0.14 1.82 0.14 2.1 0.26 2.1 0.26 2.13 ;
    END
  END A1
  PIN B0
    DIRECTION INPUT ;
    USE SIGNAL ;
    PORT
      LAYER METAL1 ;
        RECT 2.78 1.82 3.16 2.53 ;
    END
  END B0
  PIN C0
    DIRECTION INPUT ;
    USE SIGNAL ;
    PORT
      LAYER METAL1 ;
        POLYGON 2.5 2.955 2.5 2.35 2.02 2.35 2.02 2.69 2.03 2.69 2.03 2.955 ;
    END
  END C0
  PIN Y
    DIRECTION OUTPUT ;
    USE SIGNAL ;
    PORT
      LAYER METAL1 ;
        POLYGON 3.52 3.9 3.52 3.79 3.745 3.79 3.745 1.25 3.52 1.25 3.52 1.14 3.02 1.14 3.02 1.48 3.515 1.48 3.515 3.56 1.54 3.56 1.54 3.9 1.88 3.9 1.88 3.79 3.06 3.79 3.06 3.9 ;
    END
  END Y
  PIN VDD
    DIRECTION INPUT ;
    USE POWER ;
    PORT
      LAYER METAL1 ;
        POLYGON 3.96 5.44 3.96 4.64 2.64 4.64 2.64 4.465 2.3 4.465 2.3 4.64 0.52 4.64 0.52 3.56 0.18 3.56 0.18 4.64 0 4.64 0 5.44 ;
    END
  END VDD
  PIN VSS
    DIRECTION INPUT ;
    USE GROUND ;
    PORT
      LAYER METAL1 ;
        POLYGON 1.28 0.575 1.28 0.4 3.96 0.4 3.96 -0.4 0 -0.4 0 0.4 0.94 0.4 0.94 0.575 ;
    END
  END VSS
  OBS
    LAYER METAL1 ;
      POLYGON 2.04 1.2 2.04 0.86 1.7 0.86 1.7 0.915 0.52 0.915 0.52 0.86 0.18 0.86 0.18 1.2 0.52 1.2 0.52 1.145 1.7 1.145 1.7 1.2 ;
  END
END OAI211XL

MACRO AOI2BB1XL
  CLASS CORE ;
  FOREIGN AOI2BB1XL ;
  ORIGIN 0 0 ;
  SIZE 3.3 BY 5.04 ;
  SYMMETRY X Y ;
  SITE unit ;
  PIN A0N
    DIRECTION INPUT ;
    USE SIGNAL ;
    PORT
      LAYER METAL1 ;
        RECT 0.175 2.895 0.73 3.315 ;
    END
  END A0N
  PIN A1N
    DIRECTION INPUT ;
    USE SIGNAL ;
    PORT
      LAYER METAL1 ;
        RECT 0.54 2.26 1.105 2.635 ;
    END
  END A1N
  PIN B0
    DIRECTION INPUT ;
    USE SIGNAL ;
    PORT
      LAYER METAL1 ;
        RECT 1.46 2.67 1.95 3.22 ;
    END
  END B0
  PIN Y
    DIRECTION OUTPUT ;
    USE SIGNAL ;
    PORT
      LAYER METAL1 ;
        POLYGON 2.905 3.81 2.905 3.755 3.085 3.755 3.085 3.525 2.905 3.525 2.905 1.62 2.105 1.62 2.105 1.46 1.875 1.46 1.875 1.85 2.675 1.85 2.675 3.81 ;
    END
  END Y
  PIN VDD
    DIRECTION INPUT ;
    USE POWER ;
    PORT
      LAYER METAL1 ;
        POLYGON 3.3 5.44 3.3 4.64 1.64 4.64 1.64 4.465 1.3 4.465 1.3 4.64 0 4.64 0 5.44 ;
    END
  END VDD
  PIN VSS
    DIRECTION INPUT ;
    USE GROUND ;
    PORT
      LAYER METAL1 ;
        POLYGON 1.27 0.575 1.27 0.4 3.3 0.4 3.3 -0.4 0 -0.4 0 0.4 0.93 0.4 0.93 0.575 ;
    END
  END VSS
  OBS
    LAYER METAL1 ;
      POLYGON 2.41 3.785 2.41 2.085 1.64 2.085 1.64 1.315 0.45 1.315 0.45 1.545 1.41 1.545 1.41 2.315 2.18 2.315 2.18 3.555 0.18 3.555 0.18 3.785 ;
  END
END AOI2BB1XL

MACRO OAI22XL
  CLASS CORE ;
  FOREIGN OAI22XL ;
  ORIGIN 0 0 ;
  SIZE 3.96 BY 5.04 ;
  SYMMETRY X Y ;
  SITE unit ;
  PIN A0
    DIRECTION INPUT ;
    USE SIGNAL ;
    PORT
      LAYER METAL1 ;
        POLYGON 2.41 2.74 2.41 2.635 2.425 2.635 2.425 2.405 2.41 2.405 2.41 1.985 2.07 1.985 2.07 2.74 ;
    END
  END A0
  PIN A1
    DIRECTION INPUT ;
    USE SIGNAL ;
    PORT
      LAYER METAL1 ;
        RECT 2.78 2.455 3.16 3.22 ;
    END
  END A1
  PIN B0
    DIRECTION INPUT ;
    USE SIGNAL ;
    PORT
      LAYER METAL1 ;
        RECT 0.8 1.765 1.6 2.13 ;
    END
  END B0
  PIN B1
    DIRECTION INPUT ;
    USE SIGNAL ;
    PORT
      LAYER METAL1 ;
        RECT 0.14 2.685 0.855 3.22 ;
    END
  END B1
  PIN Y
    DIRECTION OUTPUT ;
    USE SIGNAL ;
    PORT
      LAYER METAL1 ;
        POLYGON 1.84 3.81 1.84 3.755 3.745 3.755 3.745 1.625 2.91 1.625 2.91 1.305 2.76 1.305 2.76 1.195 2.42 1.195 2.42 1.535 2.68 1.535 2.68 1.855 3.515 1.855 3.515 3.525 1.84 3.525 1.84 3.47 1.5 3.47 1.5 3.81 ;
    END
  END Y
  PIN VDD
    DIRECTION INPUT ;
    USE POWER ;
    PORT
      LAYER METAL1 ;
        POLYGON 3.96 5.44 3.96 4.64 3.16 4.64 3.16 4.465 2.82 4.465 2.82 4.64 0.52 4.64 0.52 4.465 0.18 4.465 0.18 4.64 0 4.64 0 5.44 ;
    END
  END VDD
  PIN VSS
    DIRECTION INPUT ;
    USE GROUND ;
    PORT
      LAYER METAL1 ;
        POLYGON 1.28 0.575 1.28 0.4 3.96 0.4 3.96 -0.4 0 -0.4 0 0.4 0.94 0.4 0.94 0.575 ;
    END
  END VSS
  OBS
    LAYER METAL1 ;
      POLYGON 2.04 1.535 2.04 0.965 3.14 0.965 3.14 1.395 3.48 1.395 3.48 1.055 3.37 1.055 3.37 0.735 1.81 0.735 1.81 1.195 1.7 1.195 1.7 1.25 0.18 1.25 0.18 1.48 1.7 1.48 1.7 1.535 ;
  END
END OAI22XL

MACRO AOI32XL
  CLASS CORE ;
  FOREIGN AOI32XL ;
  ORIGIN 0 0 ;
  SIZE 4.62 BY 5.04 ;
  SYMMETRY X Y ;
  SITE unit ;
  PIN A0
    DIRECTION INPUT ;
    USE SIGNAL ;
    PORT
      LAYER METAL1 ;
        POLYGON 2.12 2.15 2.12 1.92 1.84 1.92 1.84 1.82 1.24 1.82 1.24 2.15 ;
    END
  END A0
  PIN A1
    DIRECTION INPUT ;
    USE SIGNAL ;
    PORT
      LAYER METAL1 ;
        RECT 0.875 2.405 1.56 2.91 ;
    END
  END A1
  PIN A2
    DIRECTION INPUT ;
    USE SIGNAL ;
    PORT
      LAYER METAL1 ;
        RECT 0.14 1.66 0.76 2.13 ;
    END
  END A2
  PIN B0
    DIRECTION INPUT ;
    USE SIGNAL ;
    PORT
      LAYER METAL1 ;
        RECT 2.58 2.265 3.085 2.785 ;
    END
  END B0
  PIN B1
    DIRECTION INPUT ;
    USE SIGNAL ;
    PORT
      LAYER METAL1 ;
        RECT 3.39 2.185 3.82 2.72 ;
    END
  END B1
  PIN Y
    DIRECTION OUTPUT ;
    USE SIGNAL ;
    PORT
      LAYER METAL1 ;
        POLYGON 3.4 3.685 3.4 3.315 4.33 3.315 4.33 2.075 4.405 2.075 4.405 1.845 4.33 1.845 4.33 1.455 2.305 1.455 2.305 1.075 2.075 1.075 2.075 1.685 4.1 1.685 4.1 3.085 3.17 3.085 3.17 3.345 3.06 3.345 3.06 3.685 ;
    END
  END Y
  PIN VDD
    DIRECTION INPUT ;
    USE POWER ;
    PORT
      LAYER METAL1 ;
        POLYGON 4.62 5.44 4.62 4.64 1.96 4.64 1.96 3.765 1.62 3.765 1.62 4.64 0.52 4.64 0.52 3.555 0.18 3.555 0.18 4.64 0 4.64 0 5.44 ;
    END
  END VDD
  PIN VSS
    DIRECTION INPUT ;
    USE GROUND ;
    PORT
      LAYER METAL1 ;
        POLYGON 0.52 1.34 0.52 0.4 3.3 0.4 3.3 1.22 3.64 1.22 3.64 0.4 4.62 0.4 4.62 -0.4 0 -0.4 0 0.4 0.18 0.4 0.18 1.34 ;
    END
  END VSS
  OBS
    LAYER METAL1 ;
      POLYGON 4.12 4.145 4.12 3.64 3.78 3.64 3.78 3.915 2.68 3.915 2.68 3.3 0.9 3.3 0.9 3.895 1.24 3.895 1.24 3.53 2.34 3.53 2.34 4.145 ;
  END
END AOI32XL

MACRO NOR4BX1
  CLASS CORE ;
  FOREIGN NOR4BX1 ;
  ORIGIN 0 0 ;
  SIZE 3.96 BY 5.04 ;
  SYMMETRY X Y ;
  SITE unit ;
  PIN AN
    DIRECTION INPUT ;
    USE SIGNAL ;
    PORT
      LAYER METAL1 ;
        POLYGON 0.515 2.235 0.515 2.23 0.52 2.23 0.52 1.66 0.135 1.66 0.135 2.23 0.175 2.23 0.175 2.235 ;
    END
  END AN
  PIN B
    DIRECTION INPUT ;
    USE SIGNAL ;
    PORT
      LAYER METAL1 ;
        RECT 2.51 1.735 3.16 2.155 ;
    END
  END B
  PIN C
    DIRECTION INPUT ;
    USE SIGNAL ;
    PORT
      LAYER METAL1 ;
        POLYGON 2.17 2.68 2.17 2.34 1.9 2.34 1.9 1.845 1.535 1.845 1.535 2.075 1.67 2.075 1.67 2.57 1.83 2.57 1.83 2.68 ;
    END
  END C
  PIN D
    DIRECTION INPUT ;
    USE SIGNAL ;
    PORT
      LAYER METAL1 ;
        POLYGON 1.105 3.195 1.105 3.17 1.44 3.17 1.44 2.335 1.21 2.335 1.21 2.94 0.875 2.94 0.875 3.195 ;
    END
  END D
  PIN Y
    DIRECTION OUTPUT ;
    USE SIGNAL ;
    PORT
      LAYER METAL1 ;
        POLYGON 3.73 3.355 3.73 2.075 3.745 2.075 3.745 1.845 3.73 1.845 3.73 1.21 3.2 1.21 3.2 1.1 1.54 1.1 1.54 1.44 3.5 1.44 3.5 3.015 3.3 3.015 3.3 3.355 ;
    END
  END Y
  PIN VDD
    DIRECTION INPUT ;
    USE POWER ;
    PORT
      LAYER METAL1 ;
        POLYGON 3.96 5.44 3.96 4.64 1.18 4.64 1.18 4.465 0.84 4.465 0.84 4.64 0 4.64 0 5.44 ;
    END
  END VDD
  PIN VSS
    DIRECTION INPUT ;
    USE GROUND ;
    PORT
      LAYER METAL1 ;
        POLYGON 3.76 0.575 3.76 0.4 3.96 0.4 3.96 -0.4 0 -0.4 0 0.4 0.84 0.4 0.84 0.575 1.18 0.575 1.18 0.4 2.1 0.4 2.1 0.575 2.44 0.575 2.44 0.4 3.42 0.4 3.42 0.575 ;
    END
  END VSS
  OBS
    LAYER METAL1 ;
      POLYGON 2.63 3.68 2.63 2.725 3.27 2.725 3.27 2.495 2.4 2.495 2.4 3.45 0.52 3.45 0.52 2.7 0.98 2.7 0.98 1.145 0.52 1.145 0.52 1.035 0.18 1.035 0.18 1.375 0.75 1.375 0.75 2.47 0.29 2.47 0.29 2.97 0.18 2.97 0.18 3.31 0.29 3.31 0.29 3.68 ;
  END
END NOR4BX1

MACRO NAND4X1
  CLASS CORE ;
  FOREIGN NAND4X1 ;
  ORIGIN 0 0 ;
  SIZE 3.3 BY 5.04 ;
  SYMMETRY X Y ;
  SITE unit ;
  PIN A
    DIRECTION INPUT ;
    USE SIGNAL ;
    PORT
      LAYER METAL1 ;
        POLYGON 2.705 2.1 2.705 1.76 2.365 1.76 2.365 1.845 1.535 1.845 1.535 2.075 2.365 2.075 2.365 2.1 ;
    END
  END A
  PIN B
    DIRECTION INPUT ;
    USE SIGNAL ;
    PORT
      LAYER METAL1 ;
        RECT 1.91 2.405 2.5 2.78 ;
    END
  END B
  PIN C
    DIRECTION INPUT ;
    USE SIGNAL ;
    PORT
      LAYER METAL1 ;
        POLYGON 1.485 2.67 1.485 2.33 1.23 2.33 1.23 1.845 0.875 1.845 0.875 2.075 1 2.075 1 2.67 ;
    END
  END C
  PIN D
    DIRECTION INPUT ;
    USE SIGNAL ;
    PORT
      LAYER METAL1 ;
        POLYGON 0.77 2.67 0.77 2.33 0.52 2.33 0.52 1.845 0.215 1.845 0.215 2.075 0.29 2.075 0.29 2.67 ;
    END
  END D
  PIN Y
    DIRECTION OUTPUT ;
    USE SIGNAL ;
    PORT
      LAYER METAL1 ;
        POLYGON 2.5 3.435 2.5 3.325 3.17 3.325 3.17 1.295 2.995 1.295 2.995 0.715 2.655 0.715 2.655 1.525 2.94 1.525 2.94 2.965 2.78 2.965 2.78 3.095 0.8 3.095 0.8 3.435 1.14 3.435 1.14 3.325 2.16 3.325 2.16 3.435 ;
    END
  END Y
  PIN VDD
    DIRECTION INPUT ;
    USE POWER ;
    PORT
      LAYER METAL1 ;
        POLYGON 3.3 5.44 3.3 4.64 3.12 4.64 3.12 4.465 2.78 4.465 2.78 4.64 2.08 4.64 2.08 4.465 1.74 4.465 1.74 4.64 0.52 4.64 0.52 4.465 0.18 4.465 0.18 4.64 0 4.64 0 5.44 ;
    END
  END VDD
  PIN VSS
    DIRECTION INPUT ;
    USE GROUND ;
    PORT
      LAYER METAL1 ;
        POLYGON 0.535 1.1 0.535 0.4 3.3 0.4 3.3 -0.4 0 -0.4 0 0.4 0.195 0.4 0.195 1.1 ;
    END
  END VSS
END NAND4X1

MACRO NOR2BX1
  CLASS CORE ;
  FOREIGN NOR2BX1 ;
  ORIGIN 0 0 ;
  SIZE 2.64 BY 5.04 ;
  SYMMETRY X Y ;
  SITE unit ;
  PIN AN
    DIRECTION INPUT ;
    USE SIGNAL ;
    PORT
      LAYER METAL1 ;
        RECT 0.14 2.04 0.52 2.66 ;
    END
  END AN
  PIN B
    DIRECTION INPUT ;
    USE SIGNAL ;
    PORT
      LAYER METAL1 ;
        POLYGON 1.55 2.815 1.55 2.66 1.98 2.66 1.98 2.38 1.21 2.38 1.21 2.815 ;
    END
  END B
  PIN Y
    DIRECTION OUTPUT ;
    USE SIGNAL ;
    PORT
      LAYER METAL1 ;
        POLYGON 2.51 3.605 2.51 1.24 1.89 1.24 1.89 1.13 1.55 1.13 1.55 1.47 2.28 1.47 2.28 2.965 2.12 2.965 2.12 3.605 ;
    END
  END Y
  PIN VDD
    DIRECTION INPUT ;
    USE POWER ;
    PORT
      LAYER METAL1 ;
        POLYGON 2.64 5.44 2.64 4.64 1.14 4.64 1.14 3.785 0.8 3.785 0.8 4.64 0 4.64 0 5.44 ;
    END
  END VDD
  PIN VSS
    DIRECTION INPUT ;
    USE GROUND ;
    PORT
      LAYER METAL1 ;
        POLYGON 2.46 0.575 2.46 0.4 2.64 0.4 2.64 -0.4 0 -0.4 0 0.4 0.99 0.4 0.99 0.575 1.33 0.575 1.33 0.4 2.12 0.4 2.12 0.575 ;
    END
  END VSS
  OBS
    LAYER METAL1 ;
      POLYGON 0.52 3.345 0.52 3.235 0.98 3.235 0.98 2.09 1.74 2.09 1.74 2.145 2.05 2.145 2.05 1.805 1.74 1.805 1.74 1.86 0.98 1.86 0.98 1.355 0.52 1.355 0.52 1.275 0.18 1.275 0.18 1.615 0.75 1.615 0.75 3.005 0.18 3.005 0.18 3.345 ;
  END
END NOR2BX1

MACRO NAND2BXL
  CLASS CORE ;
  FOREIGN NAND2BXL ;
  ORIGIN 0 0 ;
  SIZE 2.64 BY 5.04 ;
  SYMMETRY X Y ;
  SITE unit ;
  PIN AN
    DIRECTION INPUT ;
    USE SIGNAL ;
    PORT
      LAYER METAL1 ;
        RECT 0.21 3.785 0.74 4.34 ;
    END
  END AN
  PIN B
    DIRECTION INPUT ;
    USE SIGNAL ;
    PORT
      LAYER METAL1 ;
        POLYGON 1.475 2.285 1.475 1.93 1.42 1.93 1.42 1.845 0.875 1.845 0.875 1.93 0.8 1.93 0.8 2.285 ;
    END
  END B
  PIN Y
    DIRECTION OUTPUT ;
    USE SIGNAL ;
    PORT
      LAYER METAL1 ;
        POLYGON 1.84 3.605 1.84 3.55 2.495 3.55 2.495 1.285 2.44 1.285 2.44 1.03 2.1 1.03 2.1 1.285 1.535 1.285 1.535 1.515 2.265 1.515 2.265 3.32 1.84 3.32 1.84 3.265 1.5 3.265 1.5 3.605 ;
    END
  END Y
  PIN VDD
    DIRECTION INPUT ;
    USE POWER ;
    PORT
      LAYER METAL1 ;
        POLYGON 2.64 5.44 2.64 4.64 2.4 4.64 2.4 4.465 1.42 4.465 1.42 4.64 0 4.64 0 5.44 ;
    END
  END VDD
  PIN VSS
    DIRECTION INPUT ;
    USE GROUND ;
    PORT
      LAYER METAL1 ;
        POLYGON 1.12 0.575 1.12 0.4 2.64 0.4 2.64 -0.4 0 -0.4 0 0.4 0.78 0.4 0.78 0.575 ;
    END
  END VSS
  OBS
    LAYER METAL1 ;
      POLYGON 0.52 3.45 0.52 3.035 2.025 3.035 2.025 2.575 1.795 2.575 1.795 2.805 0.465 2.805 0.465 1.49 0.52 1.49 0.52 1.15 0.18 1.15 0.18 1.49 0.235 1.49 0.235 3.11 0.18 3.11 0.18 3.45 ;
  END
END NAND2BXL

MACRO AOI22X1
  CLASS CORE ;
  FOREIGN AOI22X1 ;
  ORIGIN 0 0 ;
  SIZE 3.3 BY 5.04 ;
  SYMMETRY X Y ;
  SITE unit ;
  PIN A0
    DIRECTION INPUT ;
    USE SIGNAL ;
    PORT
      LAYER METAL1 ;
        POLYGON 1.765 2.075 1.765 1.995 2.17 1.995 2.17 1.655 1.83 1.655 1.83 1.71 1.535 1.71 1.535 2.075 ;
    END
  END A0
  PIN A1
    DIRECTION INPUT ;
    USE SIGNAL ;
    PORT
      LAYER METAL1 ;
        RECT 2.115 2.26 2.68 2.66 ;
    END
  END A1
  PIN B0
    DIRECTION INPUT ;
    USE SIGNAL ;
    PORT
      LAYER METAL1 ;
        RECT 0.875 2.38 1.52 2.785 ;
    END
  END B0
  PIN B1
    DIRECTION INPUT ;
    USE SIGNAL ;
    PORT
      LAYER METAL1 ;
        RECT 0.19 1.77 0.53 2.475 ;
    END
  END B1
  PIN Y
    DIRECTION OUTPUT ;
    USE SIGNAL ;
    PORT
      LAYER METAL1 ;
        POLYGON 2.48 3.275 2.48 3.165 3.16 3.165 3.16 1.115 1.8 1.115 1.8 1.06 1.46 1.06 1.46 1.4 1.8 1.4 1.8 1.345 2.855 1.345 2.855 1.515 2.93 1.515 2.93 2.935 2.14 2.935 2.14 3.275 ;
    END
  END Y
  PIN VDD
    DIRECTION INPUT ;
    USE POWER ;
    PORT
      LAYER METAL1 ;
        POLYGON 3.3 5.44 3.3 4.64 1.18 4.64 1.18 4.465 0.84 4.465 0.84 4.64 0 4.64 0 5.44 ;
    END
  END VDD
  PIN VSS
    DIRECTION INPUT ;
    USE GROUND ;
    PORT
      LAYER METAL1 ;
        POLYGON 0.52 1.45 0.52 0.4 2.78 0.4 2.78 0.575 3.12 0.575 3.12 0.4 3.3 0.4 3.3 -0.4 0 -0.4 0 0.4 0.18 0.4 0.18 1.45 ;
    END
  END VSS
  OBS
    LAYER METAL1 ;
      POLYGON 1.84 3.975 1.84 3.925 3.12 3.925 3.12 3.585 2.78 3.585 2.78 3.695 1.84 3.695 1.84 3.635 1.5 3.635 1.5 3.69 0.52 3.69 0.52 3.05 0.18 3.05 0.18 3.92 1.5 3.92 1.5 3.975 ;
  END
END AOI22X1

MACRO OAI211X1
  CLASS CORE ;
  FOREIGN OAI211X1 ;
  ORIGIN 0 0 ;
  SIZE 3.96 BY 5.04 ;
  SYMMETRY X Y ;
  SITE unit ;
  PIN A0
    DIRECTION INPUT ;
    USE SIGNAL ;
    PORT
      LAYER METAL1 ;
        RECT 0.8 2.38 1.56 2.66 ;
    END
  END A0
  PIN A1
    DIRECTION INPUT ;
    USE SIGNAL ;
    PORT
      LAYER METAL1 ;
        POLYGON 0.6 2.13 0.6 2.1 0.88 2.1 0.88 1.82 0.6 1.82 0.6 1.79 0.26 1.79 0.26 1.82 0.14 1.82 0.14 2.1 0.26 2.1 0.26 2.13 ;
    END
  END A1
  PIN B0
    DIRECTION INPUT ;
    USE SIGNAL ;
    PORT
      LAYER METAL1 ;
        RECT 2.78 1.82 3.16 2.53 ;
    END
  END B0
  PIN C0
    DIRECTION INPUT ;
    USE SIGNAL ;
    PORT
      LAYER METAL1 ;
        POLYGON 2.5 2.955 2.5 2.35 2.02 2.35 2.02 2.69 2.03 2.69 2.03 2.955 ;
    END
  END C0
  PIN Y
    DIRECTION OUTPUT ;
    USE SIGNAL ;
    PORT
      LAYER METAL1 ;
        POLYGON 3.52 3.9 3.52 3.79 3.745 3.79 3.745 1.25 3.52 1.25 3.52 1.14 3.02 1.14 3.02 1.48 3.515 1.48 3.515 3.56 1.54 3.56 1.54 3.9 1.88 3.9 1.88 3.79 3.06 3.79 3.06 3.9 ;
    END
  END Y
  PIN VDD
    DIRECTION INPUT ;
    USE POWER ;
    PORT
      LAYER METAL1 ;
        POLYGON 3.96 5.44 3.96 4.64 2.64 4.64 2.64 4.465 2.3 4.465 2.3 4.64 0.52 4.64 0.52 3.74 0.18 3.74 0.18 4.64 0 4.64 0 5.44 ;
    END
  END VDD
  PIN VSS
    DIRECTION INPUT ;
    USE GROUND ;
    PORT
      LAYER METAL1 ;
        POLYGON 1.28 0.575 1.28 0.4 3.96 0.4 3.96 -0.4 0 -0.4 0 0.4 0.94 0.4 0.94 0.575 ;
    END
  END VSS
  OBS
    LAYER METAL1 ;
      POLYGON 2.04 1.2 2.04 0.86 1.7 0.86 1.7 0.915 0.52 0.915 0.52 0.86 0.18 0.86 0.18 1.2 0.52 1.2 0.52 1.145 1.7 1.145 1.7 1.2 ;
  END
END OAI211X1

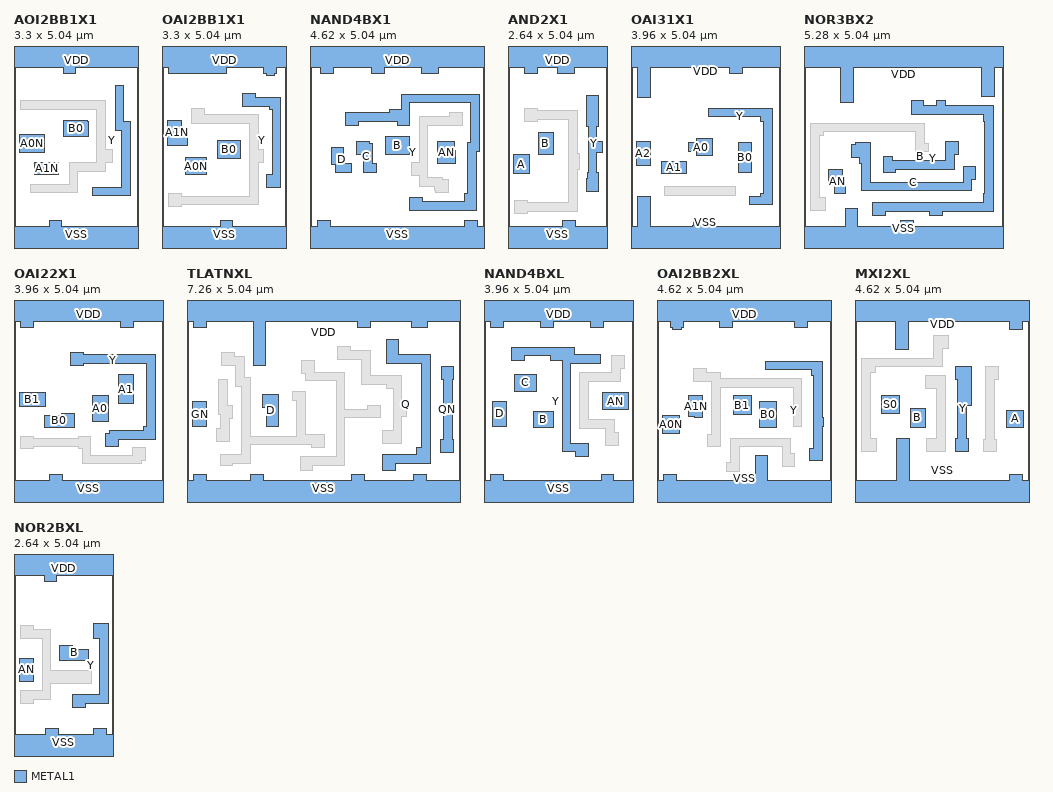
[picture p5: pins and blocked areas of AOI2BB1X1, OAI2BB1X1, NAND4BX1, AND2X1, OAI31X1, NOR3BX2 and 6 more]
MACRO AOI2BB1X1
  CLASS CORE ;
  FOREIGN AOI2BB1X1 ;
  ORIGIN 0 0 ;
  SIZE 3.3 BY 5.04 ;
  SYMMETRY X Y ;
  SITE unit ;
  PIN A0N
    DIRECTION INPUT ;
    USE SIGNAL ;
    PORT
      LAYER METAL1 ;
        RECT 0.14 2.38 0.8 2.85 ;
    END
  END A0N
  PIN A1N
    DIRECTION INPUT ;
    USE SIGNAL ;
    PORT
      LAYER METAL1 ;
        RECT 0.55 1.78 1.18 2.12 ;
    END
  END A1N
  PIN B0
    DIRECTION INPUT ;
    USE SIGNAL ;
    PORT
      LAYER METAL1 ;
        POLYGON 1.96 3.22 1.96 3.195 1.965 3.195 1.965 2.795 1.315 2.795 1.315 3.22 ;
    END
  END B0
  PIN Y
    DIRECTION OUTPUT ;
    USE SIGNAL ;
    PORT
      LAYER METAL1 ;
        POLYGON 2.91 4.14 2.91 3.195 3.085 3.195 3.085 1.225 2.09 1.225 2.09 1.455 2.855 1.455 2.855 2.965 2.68 2.965 2.68 4.14 ;
    END
  END Y
  PIN VDD
    DIRECTION INPUT ;
    USE POWER ;
    PORT
      LAYER METAL1 ;
        POLYGON 3.3 5.44 3.3 4.64 1.64 4.64 1.64 4.465 1.3 4.465 1.3 4.64 0 4.64 0 5.44 ;
    END
  END VDD
  PIN VSS
    DIRECTION INPUT ;
    USE GROUND ;
    PORT
      LAYER METAL1 ;
        POLYGON 1.27 0.575 1.27 0.4 3.3 0.4 3.3 -0.4 0 -0.4 0 0.4 0.93 0.4 0.93 0.575 ;
    END
  END VSS
  OBS
    LAYER METAL1 ;
      POLYGON 2.43 3.755 2.43 2.465 2.62 2.465 2.62 2.105 2.43 2.105 2.43 1.875 1.695 1.875 1.695 1.305 0.45 1.305 0.45 1.535 1.465 1.535 1.465 2.105 2.2 2.105 2.2 3.525 0.18 3.525 0.18 3.755 ;
  END
END AOI2BB1X1

MACRO OAI2BB1X1
  CLASS CORE ;
  FOREIGN OAI2BB1X1 ;
  ORIGIN 0 0 ;
  SIZE 3.3 BY 5.04 ;
  SYMMETRY X Y ;
  SITE unit ;
  PIN A0N
    DIRECTION INPUT ;
    USE SIGNAL ;
    PORT
      LAYER METAL1 ;
        RECT 0.625 1.78 1.18 2.235 ;
    END
  END A0N
  PIN A1N
    DIRECTION INPUT ;
    USE SIGNAL ;
    PORT
      LAYER METAL1 ;
        POLYGON 0.52 3.22 0.52 2.91 0.68 2.91 0.68 2.57 0.14 2.57 0.14 3.22 ;
    END
  END A1N
  PIN B0
    DIRECTION INPUT ;
    USE SIGNAL ;
    PORT
      LAYER METAL1 ;
        RECT 1.46 2.21 2.075 2.69 ;
    END
  END B0
  PIN Y
    DIRECTION OUTPUT ;
    USE SIGNAL ;
    PORT
      LAYER METAL1 ;
        POLYGON 2.485 3.945 2.485 3.835 3.155 3.835 3.155 1.44 2.78 1.44 2.78 1.78 2.925 1.78 2.925 3.525 2.855 3.525 2.855 3.605 2.145 3.605 2.145 3.945 ;
    END
  END Y
  PIN VDD
    DIRECTION INPUT ;
    USE POWER ;
    PORT
      LAYER METAL1 ;
        POLYGON 3.3 5.44 3.3 4.64 3.045 4.64 3.045 4.465 2.99 4.465 2.99 4.41 2.76 4.41 2.76 4.465 2.705 4.465 2.705 4.64 1.72 4.64 1.72 4.465 0.18 4.465 0.18 4.64 0 4.64 0 5.44 ;
    END
  END VDD
  PIN VSS
    DIRECTION INPUT ;
    USE GROUND ;
    PORT
      LAYER METAL1 ;
        POLYGON 1.88 0.575 1.88 0.4 3.3 0.4 3.3 -0.4 0 -0.4 0 0.4 1.54 0.4 1.54 0.575 ;
    END
  END VSS
  OBS
    LAYER METAL1 ;
      POLYGON 1.12 3.54 1.12 3.375 2.55 3.375 2.55 2.45 2.695 2.45 2.695 2.1 2.55 2.1 2.55 0.985 0.52 0.985 0.52 0.935 0.18 0.935 0.18 1.275 0.52 1.275 0.52 1.215 2.32 1.215 2.32 3.145 0.78 3.145 0.78 3.54 ;
  END
END OAI2BB1X1

MACRO NAND4BX1
  CLASS CORE ;
  FOREIGN NAND4BX1 ;
  ORIGIN 0 0 ;
  SIZE 4.62 BY 5.04 ;
  SYMMETRY X Y ;
  SITE unit ;
  PIN AN
    DIRECTION INPUT ;
    USE SIGNAL ;
    PORT
      LAYER METAL1 ;
        POLYGON 3.82 2.66 3.82 2.43 3.87 2.43 3.87 2.09 3.375 2.09 3.375 2.66 ;
    END
  END AN
  PIN B
    DIRECTION INPUT ;
    USE SIGNAL ;
    PORT
      LAYER METAL1 ;
        RECT 2.015 2.33 2.64 2.795 ;
    END
  END B
  PIN C
    DIRECTION INPUT ;
    USE SIGNAL ;
    PORT
      LAYER METAL1 ;
        POLYGON 1.575 2.67 1.575 2.615 1.655 2.615 1.655 2.075 1.765 2.075 1.765 1.845 1.425 1.845 1.425 2.33 1.235 2.33 1.235 2.67 ;
    END
  END C
  PIN D
    DIRECTION INPUT ;
    USE SIGNAL ;
    PORT
      LAYER METAL1 ;
        POLYGON 0.895 2.52 0.895 2.075 1.105 2.075 1.105 1.845 0.665 1.845 0.665 2.065 0.575 2.065 0.575 2.52 ;
    END
  END D
  PIN Y
    DIRECTION OUTPUT ;
    USE SIGNAL ;
    PORT
      LAYER METAL1 ;
        POLYGON 4.495 3.92 4.495 2.405 4.405 2.405 4.405 0.845 2.635 0.845 2.635 1.185 2.975 1.185 2.975 1.075 4.1 1.075 4.1 1.285 4.175 1.285 4.175 2.635 4.265 2.635 4.265 3.69 2.65 3.69 2.65 3.095 2.31 3.095 2.31 3.205 1.29 3.205 1.29 3.095 0.95 3.095 0.95 3.435 2.12 3.435 2.12 3.525 2.42 3.525 2.42 3.92 ;
    END
  END Y
  PIN VDD
    DIRECTION INPUT ;
    USE POWER ;
    PORT
      LAYER METAL1 ;
        POLYGON 4.62 5.44 4.62 4.64 3.4 4.64 3.4 4.465 2.95 4.465 2.95 4.64 1.97 4.64 1.97 4.465 1.63 4.465 1.63 4.64 0.62 4.64 0.62 4.465 0.28 4.465 0.28 4.64 0 4.64 0 5.44 ;
    END
  END VDD
  PIN VSS
    DIRECTION INPUT ;
    USE GROUND ;
    PORT
      LAYER METAL1 ;
        POLYGON 4.44 0.575 4.44 0.4 4.62 0.4 4.62 -0.4 0 -0.4 0 0.4 0.195 0.4 0.195 0.575 0.535 0.575 0.535 0.4 4.1 0.4 4.1 0.575 ;
    END
  END VSS
  OBS
    LAYER METAL1 ;
      POLYGON 4.035 3.435 4.035 3.095 3.13 3.095 3.13 1.7 3.525 1.7 3.525 1.645 3.675 1.645 3.675 1.305 3.335 1.305 3.335 1.36 3.295 1.36 3.295 1.47 2.9 1.47 2.9 1.76 2.695 1.76 2.695 2.1 2.9 2.1 2.9 3.325 3.695 3.325 3.695 3.435 ;
  END
END NAND4BX1

MACRO AND2X1
  CLASS CORE ;
  FOREIGN AND2X1 ;
  ORIGIN 0 0 ;
  SIZE 2.64 BY 5.04 ;
  SYMMETRY X Y ;
  SITE unit ;
  PIN A
    DIRECTION INPUT ;
    USE SIGNAL ;
    PORT
      LAYER METAL1 ;
        RECT 0.15 1.82 0.565 2.315 ;
    END
  END A
  PIN B
    DIRECTION INPUT ;
    USE SIGNAL ;
    PORT
      LAYER METAL1 ;
        RECT 0.8 2.315 1.215 2.895 ;
    END
  END B
  PIN Y
    DIRECTION OUTPUT ;
    USE SIGNAL ;
    PORT
      LAYER METAL1 ;
        POLYGON 2.41 3.895 2.41 3.075 2.355 3.075 2.355 2.66 2.5 2.66 2.5 2.38 2.355 2.38 2.355 1.845 2.41 1.845 2.41 1.345 2.07 1.345 2.07 1.685 2.12 1.685 2.12 1.845 2.125 1.845 2.125 3.075 2.07 3.075 2.07 3.895 ;
    END
  END Y
  PIN VDD
    DIRECTION INPUT ;
    USE POWER ;
    PORT
      LAYER METAL1 ;
        POLYGON 2.64 5.44 2.64 4.64 1.755 4.64 1.755 4.465 1.31 4.465 1.31 4.64 0.79 4.64 0.79 4.465 0.45 4.465 0.45 4.64 0 4.64 0 5.44 ;
    END
  END VDD
  PIN VSS
    DIRECTION INPUT ;
    USE GROUND ;
    PORT
      LAYER METAL1 ;
        POLYGON 1.79 0.575 1.79 0.4 2.64 0.4 2.64 -0.4 0 -0.4 0 0.4 1.45 0.4 1.45 0.575 ;
    END
  END VSS
  OBS
    LAYER METAL1 ;
      POLYGON 0.79 3.53 0.79 3.475 1.835 3.475 1.835 2.355 1.885 2.355 1.885 1.935 1.835 1.935 1.835 0.82 0.52 0.82 0.52 0.765 0.18 0.765 0.18 1.105 0.52 1.105 0.52 1.05 1.605 1.05 1.605 1.935 1.595 1.935 1.595 2.355 1.605 2.355 1.605 3.245 0.79 3.245 0.79 3.19 0.45 3.19 0.45 3.53 ;
  END
END AND2X1

MACRO OAI31X1
  CLASS CORE ;
  FOREIGN OAI31X1 ;
  ORIGIN 0 0 ;
  SIZE 3.96 BY 5.04 ;
  SYMMETRY X Y ;
  SITE unit ;
  PIN A0
    DIRECTION INPUT ;
    USE SIGNAL ;
    PORT
      LAYER METAL1 ;
        POLYGON 2.17 2.735 2.17 2.305 1.75 2.305 1.75 2.395 1.535 2.395 1.535 2.635 1.75 2.635 1.75 2.735 ;
    END
  END A0
  PIN A1
    DIRECTION INPUT ;
    USE SIGNAL ;
    PORT
      LAYER METAL1 ;
        RECT 0.8 1.82 1.48 2.13 ;
    END
  END A1
  PIN A2
    DIRECTION INPUT ;
    USE SIGNAL ;
    PORT
      LAYER METAL1 ;
        RECT 0.14 2.02 0.52 2.66 ;
    END
  END A2
  PIN B0
    DIRECTION INPUT ;
    USE SIGNAL ;
    PORT
      LAYER METAL1 ;
        RECT 2.855 1.85 3.185 2.635 ;
    END
  END B0
  PIN Y
    DIRECTION OUTPUT ;
    USE SIGNAL ;
    PORT
      LAYER METAL1 ;
        POLYGON 3.745 3.55 3.745 0.99 3.14 0.99 3.14 1.22 3.44 1.22 3.44 1.285 3.515 1.285 3.515 3.195 3.44 3.195 3.44 3.32 2.06 3.32 2.06 3.55 ;
    END
  END Y
  PIN VDD
    DIRECTION INPUT ;
    USE POWER ;
    PORT
      LAYER METAL1 ;
        POLYGON 3.96 5.44 3.96 4.64 2.96 4.64 2.96 4.465 2.62 4.465 2.62 4.64 0.52 4.64 0.52 3.82 0.18 3.82 0.18 4.64 0 4.64 0 5.44 ;
    END
  END VDD
  PIN VSS
    DIRECTION INPUT ;
    USE GROUND ;
    PORT
      LAYER METAL1 ;
        POLYGON 0.52 1.22 0.52 0.4 1.62 0.4 1.62 0.43 1.66 0.43 1.66 0.575 2 0.575 2 0.43 2.04 0.43 2.04 0.4 3.96 0.4 3.96 -0.4 0 -0.4 0 0.4 0.18 0.4 0.18 1.22 ;
    END
  END VSS
  OBS
    LAYER METAL1 ;
      RECT 0.9 1.245 2.76 1.475 ;
  END
END OAI31X1

MACRO NOR3BX2
  CLASS CORE ;
  FOREIGN NOR3BX2 ;
  ORIGIN 0 0 ;
  SIZE 5.28 BY 5.04 ;
  SYMMETRY X Y ;
  SITE unit ;
  PIN AN
    DIRECTION INPUT ;
    USE SIGNAL ;
    PORT
      LAYER METAL1 ;
        POLYGON 1.03 1.92 1.03 1.515 1.105 1.515 1.105 1.285 0.8 1.285 0.8 1.58 0.655 1.58 0.655 1.92 ;
    END
  END AN
  PIN B
    DIRECTION INPUT ;
    USE SIGNAL ;
    PORT
      LAYER METAL1 ;
        POLYGON 4.095 2.67 4.095 2.33 3.985 2.33 3.985 1.935 2.425 1.935 2.425 1.845 2.105 1.845 2.105 2.275 2.335 2.275 2.335 2.165 3.755 2.165 3.755 2.67 ;
    END
  END B
  PIN C
    DIRECTION INPUT ;
    USE SIGNAL ;
    PORT
      LAYER METAL1 ;
        POLYGON 1.765 2.635 1.765 2.405 1.76 2.405 1.76 1.59 4.22 1.59 4.22 1.995 4.56 1.995 4.56 1.655 4.45 1.655 4.45 1.36 1.53 1.36 1.53 2.075 1.46 2.075 1.46 2.25 1.265 2.25 1.265 2.59 1.375 2.59 1.375 2.635 ;
    END
  END C
  PIN Y
    DIRECTION OUTPUT ;
    USE SIGNAL ;
    PORT
      LAYER METAL1 ;
        POLYGON 3.18 3.76 3.18 3.615 3.515 3.615 3.515 3.755 3.745 3.755 3.745 3.615 5.02 3.615 5.02 0.805 3.67 0.805 3.67 0.695 3.33 0.695 3.33 0.805 2.15 0.805 2.15 0.695 1.81 0.695 1.81 1.035 4.76 1.035 4.76 1.285 4.79 1.285 4.79 3.195 4.76 3.195 4.76 3.385 2.84 3.385 2.84 3.76 ;
    END
  END Y
  PIN VDD
    DIRECTION INPUT ;
    USE POWER ;
    PORT
      LAYER METAL1 ;
        POLYGON 5.28 5.44 5.28 4.64 5.04 4.64 5.04 3.85 4.7 3.85 4.7 4.64 1.3 4.64 1.3 3.705 0.96 3.705 0.96 4.64 0 4.64 0 5.44 ;
    END
  END VDD
  PIN VSS
    DIRECTION INPUT ;
    USE GROUND ;
    PORT
      LAYER METAL1 ;
        POLYGON 1.43 0.895 1.43 0.4 2.57 0.4 2.57 0.575 2.91 0.575 2.91 0.4 5.28 0.4 5.28 -0.4 0 -0.4 0 0.4 1.09 0.4 1.09 0.895 ;
    END
  END VSS
  OBS
    LAYER METAL1 ;
      POLYGON 3.19 3.155 3.19 2.625 3.3 2.625 3.3 2.395 2.96 2.395 2.96 2.925 0.52 2.925 0.52 2.815 0.41 2.815 0.41 1.185 0.57 1.185 0.57 0.83 0.18 0.83 0.18 3.155 ;
  END
END NOR3BX2

MACRO OAI22X1
  CLASS CORE ;
  FOREIGN OAI22X1 ;
  ORIGIN 0 0 ;
  SIZE 3.96 BY 5.04 ;
  SYMMETRY X Y ;
  SITE unit ;
  PIN A0
    DIRECTION INPUT ;
    USE SIGNAL ;
    PORT
      LAYER METAL1 ;
        RECT 2.07 1.985 2.5 2.66 ;
    END
  END A0
  PIN A1
    DIRECTION INPUT ;
    USE SIGNAL ;
    PORT
      LAYER METAL1 ;
        RECT 2.78 2.455 3.16 3.22 ;
    END
  END A1
  PIN B0
    DIRECTION INPUT ;
    USE SIGNAL ;
    PORT
      LAYER METAL1 ;
        POLYGON 1.6 2.185 1.6 1.82 0.8 1.82 0.8 2.145 1.26 2.145 1.26 2.185 ;
    END
  END B0
  PIN B1
    DIRECTION INPUT ;
    USE SIGNAL ;
    PORT
      LAYER METAL1 ;
        RECT 0.14 2.38 0.84 2.75 ;
    END
  END B1
  PIN Y
    DIRECTION OUTPUT ;
    USE SIGNAL ;
    PORT
      LAYER METAL1 ;
        POLYGON 1.84 3.81 1.84 3.755 3.745 3.755 3.745 1.505 2.76 1.505 2.76 1.315 2.42 1.315 2.42 1.655 2.53 1.655 2.53 1.735 3.44 1.735 3.44 1.845 3.515 1.845 3.515 3.525 1.84 3.525 1.84 3.47 1.5 3.47 1.5 3.81 ;
    END
  END Y
  PIN VDD
    DIRECTION INPUT ;
    USE POWER ;
    PORT
      LAYER METAL1 ;
        POLYGON 3.96 5.44 3.96 4.64 3.16 4.64 3.16 4.465 2.82 4.465 2.82 4.64 0.52 4.64 0.52 4.465 0.18 4.465 0.18 4.64 0 4.64 0 5.44 ;
    END
  END VDD
  PIN VSS
    DIRECTION INPUT ;
    USE GROUND ;
    PORT
      LAYER METAL1 ;
        POLYGON 1.28 0.575 1.28 0.4 3.96 0.4 3.96 -0.4 0 -0.4 0 0.4 0.94 0.4 0.94 0.575 ;
    END
  END VSS
  OBS
    LAYER METAL1 ;
      POLYGON 2.04 1.59 2.04 1.085 3.14 1.085 3.14 1.275 3.48 1.275 3.48 0.935 3.37 0.935 3.37 0.855 1.81 0.855 1.81 1.25 1.7 1.25 1.7 1.305 0.52 1.305 0.52 1.25 0.18 1.25 0.18 1.59 0.52 1.59 0.52 1.535 1.7 1.535 1.7 1.59 ;
  END
END OAI22X1

MACRO TLATNXL
  CLASS CORE ;
  FOREIGN TLATNXL ;
  ORIGIN 0 0 ;
  SIZE 7.26 BY 5.04 ;
  SYMMETRY X Y ;
  SITE unit ;
  PIN D
    DIRECTION INPUT ;
    USE SIGNAL ;
    PORT
      LAYER METAL1 ;
        POLYGON 2.425 2.69 2.425 1.845 2.12 1.845 2.12 2.35 1.995 2.35 1.995 2.69 ;
    END
  END D
  PIN GN
    DIRECTION INPUT ;
    USE SIGNAL ;
    PORT
      LAYER METAL1 ;
        RECT 0.14 1.845 0.53 2.495 ;
    END
  END GN
  PIN Q
    DIRECTION OUTPUT ;
    USE SIGNAL ;
    PORT
      LAYER METAL1 ;
        POLYGON 5.62 4.15 5.62 3.755 6.455 3.755 6.455 0.865 5.53 0.865 5.53 0.685 5.175 0.685 5.175 1.095 6.08 1.095 6.08 1.285 6.225 1.285 6.225 3.525 5.28 3.525 5.28 4.15 ;
    END
  END Q
  PIN QN
    DIRECTION OUTPUT ;
    USE SIGNAL ;
    PORT
      LAYER METAL1 ;
        POLYGON 7.08 3.43 7.08 3.09 7.045 3.09 7.045 1.5 7.06 1.5 7.06 1.16 6.72 1.16 6.72 1.5 6.815 1.5 6.815 3.09 6.74 3.09 6.74 3.43 ;
    END
  END QN
  PIN VDD
    DIRECTION INPUT ;
    USE POWER ;
    PORT
      LAYER METAL1 ;
        POLYGON 7.26 5.44 7.26 4.64 6.375 4.64 6.375 4.465 5.96 4.465 5.96 4.64 4.86 4.64 4.86 4.465 4.52 4.465 4.52 4.64 2.095 4.64 2.095 3.46 1.755 3.46 1.755 4.64 0.52 4.64 0.52 4.465 0.18 4.465 0.18 4.64 0 4.64 0 5.44 ;
    END
  END VDD
  PIN VSS
    DIRECTION INPUT ;
    USE GROUND ;
    PORT
      LAYER METAL1 ;
        POLYGON 6.35 0.575 6.35 0.4 7.26 0.4 7.26 -0.4 0 -0.4 0 0.4 0.18 0.4 0.18 0.575 0.52 0.575 0.52 0.4 1.68 0.4 1.68 0.575 2.02 0.575 2.02 0.4 4.36 0.4 4.36 0.575 4.7 0.575 4.7 0.4 6.01 0.4 6.01 0.575 ;
    END
  END VSS
  OBS
    LAYER METAL1 ;
      POLYGON 4.325 3.96 4.325 3.85 4.855 3.85 4.855 3.19 5.7 3.19 5.7 2.44 5.81 2.44 5.81 2.1 5.7 2.1 5.7 1.4 5.19 1.4 5.19 1.74 5.47 1.74 5.47 2.85 5.28 2.85 5.28 2.96 4.625 2.96 4.625 3.62 3.985 3.62 3.985 3.96 ;
      POLYGON 1.26 3.8 1.26 3.69 1.525 3.69 1.525 3.135 1.675 3.135 1.675 1.59 2.905 1.59 2.905 2.535 2.795 2.535 2.795 2.765 3.135 2.765 3.135 1.62 3.645 1.62 3.645 1.28 3.305 1.28 3.305 1.36 1.675 1.36 1.675 0.865 1.22 0.865 1.22 0.805 0.88 0.805 0.88 1.095 1.445 1.095 1.445 2.905 1.295 2.905 1.295 3.46 0.92 3.46 0.92 3.8 ;
      POLYGON 3.375 3.59 3.375 3.285 4.185 3.285 4.185 2.3 4.8 2.3 4.8 2.41 5.14 2.41 5.14 2.07 4.185 2.07 4.185 0.805 3.34 0.805 3.34 0.68 3 0.68 3 1.035 3.955 1.035 3.955 3.055 3.14 3.055 3.14 3.25 3.035 3.25 3.035 3.59 ;
      POLYGON 1.065 3.08 1.065 2.405 1.215 2.405 1.215 2.06 1.12 2.06 1.12 1.45 0.78 1.45 0.78 1.79 0.89 1.79 0.89 2.175 0.835 2.175 0.835 3.08 ;
  END
END TLATNXL

MACRO NAND4BXL
  CLASS CORE ;
  FOREIGN NAND4BXL ;
  ORIGIN 0 0 ;
  SIZE 3.96 BY 5.04 ;
  SYMMETRY X Y ;
  SITE unit ;
  PIN AN
    DIRECTION INPUT ;
    USE SIGNAL ;
    PORT
      LAYER METAL1 ;
        RECT 3.145 2.295 3.82 2.74 ;
    END
  END AN
  PIN B
    DIRECTION INPUT ;
    USE SIGNAL ;
    PORT
      LAYER METAL1 ;
        RECT 1.325 1.82 1.84 2.235 ;
    END
  END B
  PIN C
    DIRECTION INPUT ;
    USE SIGNAL ;
    PORT
      LAYER METAL1 ;
        RECT 0.8 2.775 1.38 3.22 ;
    END
  END C
  PIN D
    DIRECTION INPUT ;
    USE SIGNAL ;
    PORT
      LAYER METAL1 ;
        POLYGON 0.6 2.52 0.6 1.845 0.215 1.845 0.215 2.515 0.28 2.515 0.28 2.52 ;
    END
  END D
  PIN Y
    DIRECTION OUTPUT ;
    USE SIGNAL ;
    PORT
      LAYER METAL1 ;
        POLYGON 2.405 3.945 2.405 3.755 3.085 3.755 3.085 3.525 2.3 3.525 2.3 1.4 2.76 1.4 2.76 1.06 2.42 1.06 2.42 1.17 2.07 1.17 2.07 3.605 1.765 3.605 1.765 3.715 1.08 3.715 1.08 3.605 0.74 3.605 0.74 3.945 ;
    END
  END Y
  PIN VDD
    DIRECTION INPUT ;
    USE POWER ;
    PORT
      LAYER METAL1 ;
        POLYGON 3.96 5.44 3.96 4.64 3.175 4.64 3.175 4.465 2.835 4.465 2.835 4.64 1.84 4.64 1.84 4.465 1.5 4.465 1.5 4.64 0.52 4.64 0.52 4.465 0.18 4.465 0.18 4.64 0 4.64 0 5.44 ;
    END
  END VDD
  PIN VSS
    DIRECTION INPUT ;
    USE GROUND ;
    PORT
      LAYER METAL1 ;
        POLYGON 3.445 0.575 3.445 0.4 3.96 0.4 3.96 -0.4 0 -0.4 0 0.4 0.18 0.4 0.18 0.575 0.52 0.575 0.52 0.4 3.105 0.4 3.105 0.575 ;
    END
  END VSS
  OBS
    LAYER METAL1 ;
      POLYGON 3.735 3.725 3.735 3.385 3.625 3.385 3.625 3.04 2.77 3.04 2.77 2.025 3.455 2.025 3.455 1.685 3.565 1.685 3.565 1.345 3.225 1.345 3.225 1.795 2.54 1.795 2.54 3.27 3.395 3.27 3.395 3.725 ;
  END
END NAND4BXL

MACRO OAI2BB2XL
  CLASS CORE ;
  FOREIGN OAI2BB2XL ;
  ORIGIN 0 0 ;
  SIZE 4.62 BY 5.04 ;
  SYMMETRY X Y ;
  SITE unit ;
  PIN B0
    DIRECTION INPUT ;
    USE SIGNAL ;
    PORT
      LAYER METAL1 ;
        RECT 2.73 1.82 3.16 2.5 ;
    END
  END B0
  PIN B1
    DIRECTION INPUT ;
    USE SIGNAL ;
    PORT
      LAYER METAL1 ;
        RECT 2.025 2.16 2.5 2.66 ;
    END
  END B1
  PIN A0N
    DIRECTION INPUT ;
    USE SIGNAL ;
    PORT
      LAYER METAL1 ;
        RECT 0.14 1.645 0.6 2.13 ;
    END
  END A0N
  PIN A1N
    DIRECTION INPUT ;
    USE SIGNAL ;
    PORT
      LAYER METAL1 ;
        POLYGON 1.215 2.66 1.215 2.09 0.985 2.09 0.985 2.1 0.83 2.1 0.83 2.66 ;
    END
  END A1N
  PIN Y
    DIRECTION OUTPUT ;
    USE SIGNAL ;
    PORT
      LAYER METAL1 ;
        POLYGON 4.38 3.58 4.38 2.075 4.405 2.075 4.405 1.845 4.38 1.845 4.38 0.93 4.04 0.93 4.04 1.27 4.15 1.27 4.15 3.195 4.1 3.195 4.1 3.35 2.88 3.35 2.88 3.58 ;
    END
  END Y
  PIN VDD
    DIRECTION INPUT ;
    USE POWER ;
    PORT
      LAYER METAL1 ;
        POLYGON 4.62 5.44 4.62 4.64 3.98 4.64 3.98 4.465 3.64 4.465 3.64 4.64 2 4.64 2 4.465 1.66 4.465 1.66 4.64 0.7 4.64 0.7 4.465 0.645 4.465 0.645 4.41 0.415 4.41 0.415 4.465 0.36 4.465 0.36 4.64 0 4.64 0 5.44 ;
    END
  END VDD
  PIN VSS
    DIRECTION INPUT ;
    USE GROUND ;
    PORT
      LAYER METAL1 ;
        POLYGON 2.94 1.075 2.94 0.4 4.62 0.4 4.62 -0.4 0 -0.4 0 0.4 0.18 0.4 0.18 0.575 0.52 0.575 0.52 0.4 2.6 0.4 2.6 1.075 ;
    END
  END VSS
  OBS
    LAYER METAL1 ;
      POLYGON 1.3 3.39 1.3 3.28 1.675 3.28 1.675 3.12 3.845 3.12 3.845 1.84 3.615 1.84 3.615 2.89 1.675 2.89 1.675 1.64 1.68 1.64 1.68 1.3 1.34 1.3 1.34 1.64 1.445 1.64 1.445 3.05 0.96 3.05 0.96 3.39 ;
      POLYGON 3.55 1.535 3.55 1.13 3.66 1.13 3.66 0.79 3.32 0.79 3.32 1.305 2.18 1.305 2.18 0.655 1.84 0.655 1.84 0.885 1.95 0.885 1.95 1.535 ;
  END
END OAI2BB2XL

MACRO MXI2XL
  CLASS CORE ;
  FOREIGN MXI2XL ;
  ORIGIN 0 0 ;
  SIZE 4.62 BY 5.04 ;
  SYMMETRY X Y ;
  SITE unit ;
  PIN A
    DIRECTION INPUT ;
    USE SIGNAL ;
    PORT
      LAYER METAL1 ;
        RECT 4.01 1.82 4.48 2.28 ;
    END
  END A
  PIN B
    DIRECTION INPUT ;
    USE SIGNAL ;
    PORT
      LAYER METAL1 ;
        RECT 1.46 1.82 1.88 2.33 ;
    END
  END B
  PIN S0
    DIRECTION INPUT ;
    USE SIGNAL ;
    PORT
      LAYER METAL1 ;
        RECT 0.705 2.2 1.18 2.66 ;
    END
  END S0
  PIN Y
    DIRECTION OUTPUT ;
    USE SIGNAL ;
    PORT
      LAYER METAL1 ;
        POLYGON 3.085 3.44 3.085 2.405 2.945 2.405 2.945 1.52 3 1.52 3 1.18 2.66 1.18 2.66 1.52 2.715 1.52 2.715 3.1 2.66 3.1 2.66 3.44 ;
    END
  END Y
  PIN VDD
    DIRECTION INPUT ;
    USE POWER ;
    PORT
      LAYER METAL1 ;
        POLYGON 4.62 5.44 4.62 4.64 4.445 4.64 4.445 4.405 4.095 4.405 4.095 4.64 1.42 4.64 1.42 3.89 1.08 3.89 1.08 4.64 0 4.64 0 5.44 ;
    END
  END VDD
  PIN VSS
    DIRECTION INPUT ;
    USE GROUND ;
    PORT
      LAYER METAL1 ;
        POLYGON 1.435 1.52 1.435 0.4 4.09 0.4 4.09 0.575 4.43 0.575 4.43 0.4 4.62 0.4 4.62 -0.4 0 -0.4 0 0.4 1.095 0.4 1.095 1.52 ;
    END
  END VSS
  OBS
    LAYER METAL1 ;
      POLYGON 2.48 4.245 2.48 3.905 2.325 3.905 2.325 3.425 0.54 3.425 0.54 3.27 0.405 3.27 0.405 1.52 0.58 1.52 0.58 1.18 0.175 1.18 0.175 3.655 2.095 3.655 2.095 4.245 ;
      POLYGON 3.8 3.44 3.8 3.1 3.695 3.1 3.695 1.51 3.76 1.51 3.76 1.17 3.42 1.17 3.42 1.51 3.465 1.51 3.465 3.1 3.46 3.1 3.46 3.44 ;
      POLYGON 2.405 3.19 2.405 1.18 1.9 1.18 1.9 1.52 2.175 1.52 2.175 2.85 1.88 2.85 1.88 3.19 ;
  END
END MXI2XL

MACRO NOR2BXL
  CLASS CORE ;
  FOREIGN NOR2BXL ;
  ORIGIN 0 0 ;
  SIZE 2.64 BY 5.04 ;
  SYMMETRY X Y ;
  SITE unit ;
  PIN AN
    DIRECTION INPUT ;
    USE SIGNAL ;
    PORT
      LAYER METAL1 ;
        RECT 0.14 1.82 0.52 2.44 ;
    END
  END AN
  PIN B
    DIRECTION INPUT ;
    USE SIGNAL ;
    PORT
      LAYER METAL1 ;
        POLYGON 1.55 2.78 1.55 2.66 1.98 2.66 1.98 2.38 1.21 2.38 1.21 2.78 ;
    END
  END B
  PIN Y
    DIRECTION OUTPUT ;
    USE SIGNAL ;
    PORT
      LAYER METAL1 ;
        POLYGON 2.51 3.35 2.51 1.24 1.89 1.24 1.89 1.13 1.55 1.13 1.55 1.47 2.28 1.47 2.28 2.965 2.12 2.965 2.12 3.35 ;
    END
  END Y
  PIN VDD
    DIRECTION INPUT ;
    USE POWER ;
    PORT
      LAYER METAL1 ;
        POLYGON 2.64 5.44 2.64 4.64 1.14 4.64 1.14 4.465 0.8 4.465 0.8 4.64 0 4.64 0 5.44 ;
    END
  END VDD
  PIN VSS
    DIRECTION INPUT ;
    USE GROUND ;
    PORT
      LAYER METAL1 ;
        POLYGON 2.46 0.575 2.46 0.4 2.64 0.4 2.64 -0.4 0 -0.4 0 0.4 0.84 0.4 0.84 0.575 1.18 0.575 1.18 0.4 2.12 0.4 2.12 0.575 ;
    END
  END VSS
  OBS
    LAYER METAL1 ;
      POLYGON 0.52 3.31 0.52 3.2 0.98 3.2 0.98 2.11 2.05 2.11 2.05 1.77 0.98 1.77 0.98 1.35 0.52 1.35 0.52 1.24 0.18 1.24 0.18 1.58 0.75 1.58 0.75 2.97 0.18 2.97 0.18 3.31 ;
  END
END NOR2BXL

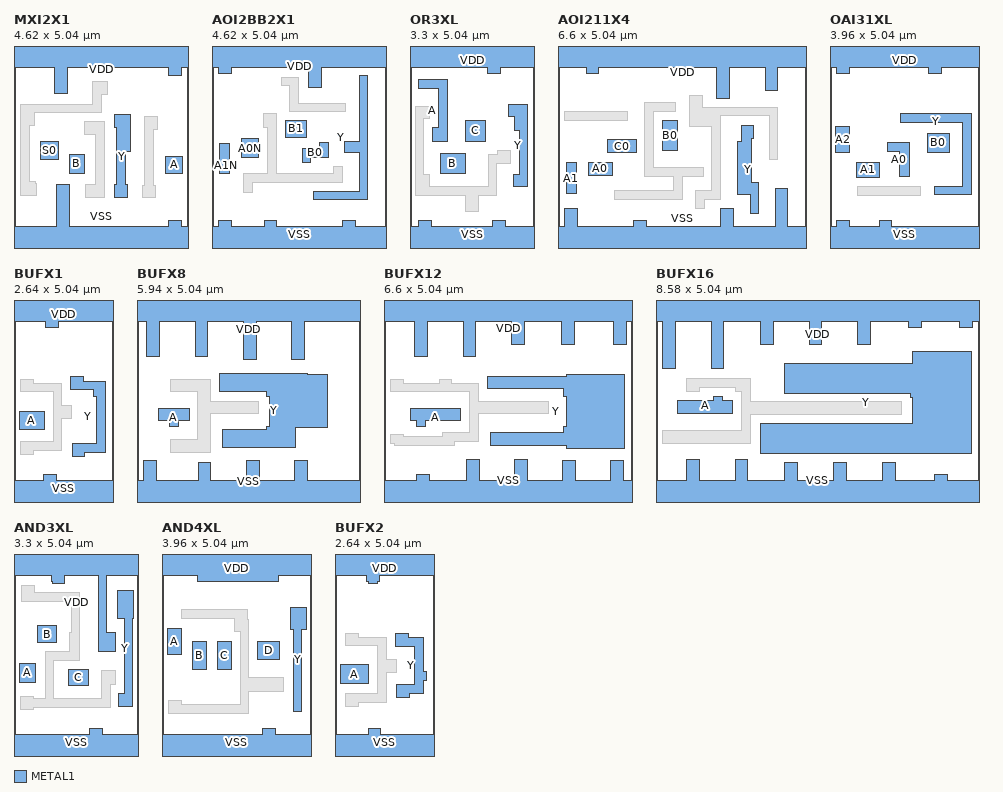
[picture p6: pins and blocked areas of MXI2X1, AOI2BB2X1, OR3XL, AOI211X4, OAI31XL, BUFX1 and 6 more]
MACRO MXI2X1
  CLASS CORE ;
  FOREIGN MXI2X1 ;
  ORIGIN 0 0 ;
  SIZE 4.62 BY 5.04 ;
  SYMMETRY X Y ;
  SITE unit ;
  PIN A
    DIRECTION INPUT ;
    USE SIGNAL ;
    PORT
      LAYER METAL1 ;
        RECT 4.01 1.82 4.48 2.28 ;
    END
  END A
  PIN B
    DIRECTION INPUT ;
    USE SIGNAL ;
    PORT
      LAYER METAL1 ;
        RECT 1.46 1.82 1.88 2.33 ;
    END
  END B
  PIN S0
    DIRECTION INPUT ;
    USE SIGNAL ;
    PORT
      LAYER METAL1 ;
        RECT 0.705 2.2 1.18 2.66 ;
    END
  END S0
  PIN Y
    DIRECTION OUTPUT ;
    USE SIGNAL ;
    PORT
      LAYER METAL1 ;
        POLYGON 3.085 3.38 3.085 2.405 2.945 2.405 2.945 1.52 3 1.52 3 1.18 2.66 1.18 2.66 1.52 2.715 1.52 2.715 3.04 2.66 3.04 2.66 3.38 ;
    END
  END Y
  PIN VDD
    DIRECTION INPUT ;
    USE POWER ;
    PORT
      LAYER METAL1 ;
        POLYGON 4.62 5.44 4.62 4.64 4.445 4.64 4.445 4.405 4.095 4.405 4.095 4.64 1.42 4.64 1.42 3.945 1.08 3.945 1.08 4.64 0 4.64 0 5.44 ;
    END
  END VDD
  PIN VSS
    DIRECTION INPUT ;
    USE GROUND ;
    PORT
      LAYER METAL1 ;
        POLYGON 1.46 1.52 1.46 0.4 4.09 0.4 4.09 0.575 4.43 0.575 4.43 0.4 4.62 0.4 4.62 -0.4 0 -0.4 0 0.4 1.12 0.4 1.12 1.52 ;
    END
  END VSS
  OBS
    LAYER METAL1 ;
      POLYGON 2.48 4.26 2.48 3.92 2.325 3.92 2.325 3.425 0.54 3.425 0.54 3.09 0.405 3.09 0.405 1.6 0.58 1.6 0.58 1.545 0.585 1.545 0.585 1.225 0.175 1.225 0.175 3.655 2.095 3.655 2.095 4.26 ;
      POLYGON 3.8 3.32 3.8 2.98 3.695 2.98 3.695 1.51 3.76 1.51 3.76 1.17 3.42 1.17 3.42 1.51 3.465 1.51 3.465 2.98 3.46 2.98 3.46 3.32 ;
      POLYGON 2.405 3.19 2.405 1.18 1.9 1.18 1.9 1.52 2.175 1.52 2.175 2.85 1.88 2.85 1.88 3.19 ;
  END
END MXI2X1

MACRO AOI2BB2X1
  CLASS CORE ;
  FOREIGN AOI2BB2X1 ;
  ORIGIN 0 0 ;
  SIZE 4.62 BY 5.04 ;
  SYMMETRY X Y ;
  SITE unit ;
  PIN B0
    DIRECTION INPUT ;
    USE SIGNAL ;
    PORT
      LAYER METAL1 ;
        POLYGON 3.085 2.635 3.085 2.25 2.62 2.25 2.62 2.105 2.39 2.105 2.39 2.48 2.855 2.48 2.855 2.635 ;
    END
  END B0
  PIN B1
    DIRECTION INPUT ;
    USE SIGNAL ;
    PORT
      LAYER METAL1 ;
        RECT 1.955 2.775 2.5 3.22 ;
    END
  END B1
  PIN A0N
    DIRECTION INPUT ;
    USE SIGNAL ;
    PORT
      LAYER METAL1 ;
        RECT 0.795 2.25 1.235 2.735 ;
    END
  END A0N
  PIN A1N
    DIRECTION INPUT ;
    USE SIGNAL ;
    PORT
      LAYER METAL1 ;
        RECT 0.19 1.82 0.475 2.605 ;
    END
  END A1N
  PIN Y
    DIRECTION OUTPUT ;
    USE SIGNAL ;
    PORT
      LAYER METAL1 ;
        POLYGON 4.13 4.405 4.13 1.115 2.7 1.115 2.7 1.345 3.9 1.345 3.9 2.38 3.515 2.38 3.515 2.66 3.9 2.66 3.9 4.405 ;
    END
  END Y
  PIN VDD
    DIRECTION INPUT ;
    USE POWER ;
    PORT
      LAYER METAL1 ;
        POLYGON 4.62 5.44 4.62 4.64 2.9 4.64 2.9 4.09 2.56 4.09 2.56 4.64 0.52 4.64 0.52 4.465 0.18 4.465 0.18 4.64 0 4.64 0 5.44 ;
    END
  END VDD
  PIN VSS
    DIRECTION INPUT ;
    USE GROUND ;
    PORT
      LAYER METAL1 ;
        POLYGON 3.8 0.575 3.8 0.4 4.62 0.4 4.62 -0.4 0 -0.4 0 0.4 0.18 0.4 0.18 0.575 0.52 0.575 0.52 0.4 1.38 0.4 1.38 0.575 1.72 0.575 1.72 0.4 3.46 0.4 3.46 0.575 ;
    END
  END VSS
  OBS
    LAYER METAL1 ;
      POLYGON 2.29 4.375 2.29 3.68 3.54 3.68 3.54 3.45 2.06 3.45 2.06 4.145 1.84 4.145 1.84 4.375 ;
      POLYGON 1.7 3.42 1.7 1.805 3.235 1.805 3.235 1.99 3.465 1.99 3.465 1.575 1.065 1.575 1.065 1.315 0.835 1.315 0.835 1.805 1.47 1.805 1.47 3.05 1.355 3.05 1.355 3.42 ;
  END
END AOI2BB2X1

MACRO OR3XL
  CLASS CORE ;
  FOREIGN OR3XL ;
  ORIGIN 0 0 ;
  SIZE 3.3 BY 5.04 ;
  SYMMETRY X Y ;
  SITE unit ;
  PIN A
    DIRECTION INPUT ;
    USE SIGNAL ;
    PORT
      LAYER METAL1 ;
        POLYGON 0.985 4.315 0.985 2.67 0.6 2.67 0.6 3.03 0.755 3.03 0.755 4.085 0.215 4.085 0.215 4.315 ;
    END
  END A
  PIN B
    DIRECTION INPUT ;
    USE SIGNAL ;
    PORT
      LAYER METAL1 ;
        RECT 0.8 1.82 1.475 2.335 ;
    END
  END B
  PIN C
    DIRECTION INPUT ;
    USE SIGNAL ;
    PORT
      LAYER METAL1 ;
        RECT 1.46 2.675 2 3.22 ;
    END
  END C
  PIN Y
    DIRECTION OUTPUT ;
    USE SIGNAL ;
    PORT
      LAYER METAL1 ;
        POLYGON 3.13 3.66 3.13 1.46 2.745 1.46 2.745 1.8 2.9 1.8 2.9 2.965 2.78 2.965 2.78 3.32 2.62 3.32 2.62 3.66 ;
    END
  END Y
  PIN VDD
    DIRECTION INPUT ;
    USE POWER ;
    PORT
      LAYER METAL1 ;
        POLYGON 3.3 5.44 3.3 4.64 2.4 4.64 2.4 4.465 2.06 4.465 2.06 4.64 0 4.64 0 5.44 ;
    END
  END VDD
  PIN VSS
    DIRECTION INPUT ;
    USE GROUND ;
    PORT
      LAYER METAL1 ;
        POLYGON 2.52 0.575 2.52 0.4 3.3 0.4 3.3 -0.4 0 -0.4 0 0.4 0.22 0.4 0.22 0.575 0.56 0.575 0.56 0.4 2.18 0.4 2.18 0.575 ;
    END
  END VSS
  OBS
    LAYER METAL1 ;
      POLYGON 0.52 3.605 0.52 3.265 0.37 3.265 0.37 1.8 0.52 1.8 0.52 1.465 2.07 1.465 2.07 2.32 2.33 2.32 2.33 2.43 2.67 2.43 2.67 2.09 2.3 2.09 2.3 1.235 1.82 1.235 1.82 0.805 1.48 0.805 1.48 1.235 0.14 1.235 0.14 3.605 ;
  END
END OR3XL

MACRO AOI211X4
  CLASS CORE ;
  FOREIGN AOI211X4 ;
  ORIGIN 0 0 ;
  SIZE 6.6 BY 5.04 ;
  SYMMETRY X Y ;
  SITE unit ;
  PIN A0
    DIRECTION INPUT ;
    USE SIGNAL ;
    PORT
      LAYER METAL1 ;
        RECT 0.8 1.775 1.44 2.1 ;
    END
  END A0
  PIN A1
    DIRECTION INPUT ;
    USE SIGNAL ;
    PORT
      LAYER METAL1 ;
        RECT 0.215 1.285 0.495 2.1 ;
    END
  END A1
  PIN B0
    DIRECTION INPUT ;
    USE SIGNAL ;
    PORT
      LAYER METAL1 ;
        RECT 2.78 2.415 3.16 3.22 ;
    END
  END B0
  PIN C0
    DIRECTION INPUT ;
    USE SIGNAL ;
    PORT
      LAYER METAL1 ;
        RECT 1.305 2.38 2.07 2.71 ;
    END
  END C0
  PIN Y
    DIRECTION OUTPUT ;
    USE SIGNAL ;
    PORT
      LAYER METAL1 ;
        POLYGON 5.195 3.08 5.195 2.74 5.14 2.74 5.14 1.585 5.325 1.585 5.325 0.76 5.095 0.76 5.095 1.26 4.76 1.26 4.76 2.66 4.855 2.66 4.855 3.08 ;
    END
  END Y
  PIN VDD
    DIRECTION INPUT ;
    USE POWER ;
    PORT
      LAYER METAL1 ;
        POLYGON 6.6 5.44 6.6 4.64 5.835 4.64 5.835 4.01 5.495 4.01 5.495 4.64 4.555 4.64 4.555 3.815 4.215 3.815 4.215 4.64 1.085 4.64 1.085 4.465 0.745 4.465 0.745 4.64 0 4.64 0 5.44 ;
    END
  END VDD
  PIN VSS
    DIRECTION INPUT ;
    USE GROUND ;
    PORT
      LAYER METAL1 ;
        POLYGON 6.1 1.42 6.1 0.4 6.6 0.4 6.6 -0.4 0 -0.4 0 0.4 0.18 0.4 0.18 0.895 0.52 0.895 0.52 0.4 2 0.4 2 0.575 2.34 0.575 2.34 0.4 4.32 0.4 4.32 0.895 4.66 0.895 4.66 0.4 5.76 0.4 5.76 1.42 ;
    END
  END VSS
  OBS
    LAYER METAL1 ;
      POLYGON 3.835 3.875 3.835 3.58 5.83 3.58 5.83 2.18 5.6 2.18 5.6 3.35 4.315 3.35 4.315 1.135 3.885 1.135 3.885 0.88 3.655 0.88 3.655 1.365 4.085 1.365 4.085 3.055 3.495 3.055 3.495 3.875 ;
      POLYGON 3.13 3.695 3.13 3.465 2.53 3.465 2.53 1.965 3.85 1.965 3.85 1.735 3.295 1.735 3.295 1.13 1.5 1.13 1.5 1.36 3.065 1.36 3.065 1.735 2.3 1.735 2.3 3.695 ;
      RECT 0.18 3.235 1.85 3.465 ;
  END
END AOI211X4

MACRO OAI31XL
  CLASS CORE ;
  FOREIGN OAI31XL ;
  ORIGIN 0 0 ;
  SIZE 3.96 BY 5.04 ;
  SYMMETRY X Y ;
  SITE unit ;
  PIN A0
    DIRECTION INPUT ;
    USE SIGNAL ;
    PORT
      LAYER METAL1 ;
        POLYGON 2.105 2.635 2.105 1.735 1.84 1.735 1.84 2.405 1.535 2.405 1.535 2.635 ;
    END
  END A0
  PIN A1
    DIRECTION INPUT ;
    USE SIGNAL ;
    PORT
      LAYER METAL1 ;
        RECT 0.71 1.705 1.325 2.12 ;
    END
  END A1
  PIN A2
    DIRECTION INPUT ;
    USE SIGNAL ;
    PORT
      LAYER METAL1 ;
        RECT 0.14 2.38 0.53 3.07 ;
    END
  END A2
  PIN B0
    DIRECTION INPUT ;
    USE SIGNAL ;
    PORT
      LAYER METAL1 ;
        RECT 2.59 2.38 3.16 2.89 ;
    END
  END B0
  PIN Y
    DIRECTION OUTPUT ;
    USE SIGNAL ;
    PORT
      LAYER METAL1 ;
        POLYGON 3.745 3.4 3.745 1.255 2.78 1.255 2.78 1.485 3.515 1.485 3.515 3.17 1.86 3.17 1.86 3.4 ;
    END
  END Y
  PIN VDD
    DIRECTION INPUT ;
    USE POWER ;
    PORT
      LAYER METAL1 ;
        POLYGON 3.96 5.44 3.96 4.64 2.96 4.64 2.96 4.465 2.62 4.465 2.62 4.64 0.52 4.64 0.52 4.465 0.18 4.465 0.18 4.64 0 4.64 0 5.44 ;
    END
  END VDD
  PIN VSS
    DIRECTION INPUT ;
    USE GROUND ;
    PORT
      LAYER METAL1 ;
        POLYGON 1.64 0.575 1.64 0.4 3.96 0.4 3.96 -0.4 0 -0.4 0 0.4 0.18 0.4 0.18 0.575 0.52 0.575 0.52 0.4 1.3 0.4 1.3 0.575 ;
    END
  END VSS
  OBS
    LAYER METAL1 ;
      RECT 0.74 1.245 2.4 1.475 ;
  END
END OAI31XL

MACRO BUFX1
  CLASS CORE ;
  FOREIGN BUFX1 ;
  ORIGIN 0 0 ;
  SIZE 2.64 BY 5.04 ;
  SYMMETRY X Y ;
  SITE unit ;
  PIN A
    DIRECTION INPUT ;
    USE SIGNAL ;
    PORT
      LAYER METAL1 ;
        RECT 0.14 1.755 0.81 2.245 ;
    END
  END A
  PIN Y
    DIRECTION OUTPUT ;
    USE SIGNAL ;
    PORT
      LAYER METAL1 ;
        POLYGON 1.84 3.16 1.84 3.05 2.425 3.05 2.425 1.15 1.88 1.15 1.88 1.04 1.54 1.04 1.54 1.38 2.195 1.38 2.195 2.635 2.12 2.635 2.12 2.82 1.5 2.82 1.5 3.16 ;
    END
  END Y
  PIN VDD
    DIRECTION INPUT ;
    USE POWER ;
    PORT
      LAYER METAL1 ;
        POLYGON 2.64 5.44 2.64 4.64 1.18 4.64 1.18 4.465 0.84 4.465 0.84 4.64 0 4.64 0 5.44 ;
    END
  END VDD
  PIN VSS
    DIRECTION INPUT ;
    USE GROUND ;
    PORT
      LAYER METAL1 ;
        POLYGON 1.12 0.575 1.12 0.4 2.64 0.4 2.64 -0.4 0 -0.4 0 0.4 0.78 0.4 0.78 0.575 ;
    END
  END VSS
  OBS
    LAYER METAL1 ;
      POLYGON 0.52 3.1 0.52 2.99 1.27 2.99 1.27 2.4 1.52 2.4 1.52 2.06 1.27 2.06 1.27 1.22 0.52 1.22 0.52 1.11 0.18 1.11 0.18 1.45 1.04 1.45 1.04 2.76 0.18 2.76 0.18 3.1 ;
  END
END BUFX1

MACRO BUFX8
  CLASS CORE ;
  FOREIGN BUFX8 ;
  ORIGIN 0 0 ;
  SIZE 5.94 BY 5.04 ;
  SYMMETRY X Y ;
  SITE unit ;
  PIN A
    DIRECTION INPUT ;
    USE SIGNAL ;
    PORT
      LAYER METAL1 ;
        POLYGON 1.38 2.33 1.38 1.99 1.105 1.99 1.105 1.845 0.875 1.845 0.875 1.99 0.57 1.99 0.57 2.33 ;
    END
  END A
  PIN Y
    DIRECTION OUTPUT ;
    USE SIGNAL ;
    PORT
      LAYER METAL1 ;
        POLYGON 4.53 3.25 4.53 3.22 5.065 3.22 5.065 1.82 4.2 1.82 4.2 1.29 2.26 1.29 2.26 1.77 3.44 1.77 3.44 1.85 3.515 1.85 3.515 2.63 3.44 2.63 3.44 2.77 2.18 2.77 2.18 3.25 ;
    END
  END Y
  PIN VDD
    DIRECTION INPUT ;
    USE POWER ;
    PORT
      LAYER METAL1 ;
        POLYGON 5.94 5.44 5.94 4.64 4.44 4.64 4.44 3.62 4.1 3.62 4.1 4.64 3.16 4.64 3.16 3.62 2.82 3.62 2.82 4.64 1.88 4.64 1.88 3.705 1.54 3.705 1.54 4.64 0.6 4.64 0.6 3.705 0.26 3.705 0.26 4.64 0 4.64 0 5.44 ;
    END
  END VDD
  PIN VSS
    DIRECTION INPUT ;
    USE GROUND ;
    PORT
      LAYER METAL1 ;
        POLYGON 4.52 0.95 4.52 0.4 5.94 0.4 5.94 -0.4 0 -0.4 0 0.4 0.18 0.4 0.18 0.95 0.52 0.95 0.52 0.4 1.62 0.4 1.62 0.895 1.96 0.895 1.96 0.4 2.9 0.4 2.9 0.95 3.24 0.95 3.24 0.4 4.18 0.4 4.18 0.95 ;
    END
  END VSS
  OBS
    LAYER METAL1 ;
      POLYGON 1.95 3.1 1.95 2.52 3.21 2.52 3.21 2.18 1.95 2.18 1.95 1.15 0.9 1.15 0.9 1.49 1.61 1.49 1.61 2.76 0.9 2.76 0.9 3.1 ;
  END
END BUFX8

MACRO BUFX12
  CLASS CORE ;
  FOREIGN BUFX12 ;
  ORIGIN 0 0 ;
  SIZE 6.6 BY 5.04 ;
  SYMMETRY X Y ;
  SITE unit ;
  PIN A
    DIRECTION INPUT ;
    USE SIGNAL ;
    PORT
      LAYER METAL1 ;
        POLYGON 2.03 2.33 2.03 1.99 1.105 1.99 1.105 1.845 0.875 1.845 0.875 1.99 0.71 1.99 0.71 2.33 ;
    END
  END A
  PIN Y
    DIRECTION OUTPUT ;
    USE SIGNAL ;
    PORT
      LAYER METAL1 ;
        POLYGON 6.385 3.22 6.385 1.26 4.835 1.26 4.835 1.35 2.82 1.35 2.82 1.69 4.76 1.69 4.76 1.85 4.835 1.85 4.835 2.63 4.76 2.63 4.76 2.84 2.74 2.84 2.74 3.18 4.835 3.18 4.835 3.22 ;
    END
  END Y
  PIN VDD
    DIRECTION INPUT ;
    USE POWER ;
    PORT
      LAYER METAL1 ;
        POLYGON 6.6 5.44 6.6 4.64 6.42 4.64 6.42 4.02 6.08 4.02 6.08 4.64 5.05 4.64 5.05 4.02 4.71 4.02 4.71 4.64 3.72 4.64 3.72 4.02 3.38 4.02 3.38 4.64 2.44 4.64 2.44 3.705 2.1 3.705 2.1 4.64 1.16 4.64 1.16 3.705 0.82 3.705 0.82 4.64 0 4.64 0 5.44 ;
    END
  END VDD
  PIN VSS
    DIRECTION INPUT ;
    USE GROUND ;
    PORT
      LAYER METAL1 ;
        POLYGON 3.8 0.965 3.8 0.4 4.74 0.4 4.74 0.95 5.08 0.95 5.08 0.4 6.02 0.4 6.02 0.95 6.36 0.95 6.36 0.4 6.6 0.4 6.6 -0.4 0 -0.4 0 0.4 0.86 0.4 0.86 0.575 1.2 0.575 1.2 0.4 2.18 0.4 2.18 0.965 2.52 0.965 2.52 0.4 3.46 0.4 3.46 0.965 ;
    END
  END VSS
  OBS
    LAYER METAL1 ;
      POLYGON 1.8 3.1 1.8 2.99 2.51 2.99 2.51 2.52 4.375 2.52 4.375 2.18 2.51 2.18 2.51 1.45 1.88 1.45 1.88 1.34 0.29 1.34 0.29 1.405 0.18 1.405 0.18 1.635 0.52 1.635 0.52 1.57 1.54 1.57 1.54 1.68 2.28 1.68 2.28 2.76 0.18 2.76 0.18 3.1 0.52 3.1 0.52 2.99 1.46 2.99 1.46 3.1 ;
  END
END BUFX12

MACRO BUFX16
  CLASS CORE ;
  FOREIGN BUFX16 ;
  ORIGIN 0 0 ;
  SIZE 8.58 BY 5.04 ;
  SYMMETRY X Y ;
  SITE unit ;
  PIN A
    DIRECTION INPUT ;
    USE SIGNAL ;
    PORT
      LAYER METAL1 ;
        POLYGON 1.765 2.635 1.765 2.53 2.04 2.53 2.04 2.19 0.58 2.19 0.58 2.53 1.535 2.53 1.535 2.635 ;
    END
  END A
  PIN Y
    DIRECTION OUTPUT ;
    USE SIGNAL ;
    PORT
      LAYER METAL1 ;
        POLYGON 8.365 3.84 8.365 1.125 2.78 1.125 2.78 1.925 6.815 1.925 6.815 2.625 6.74 2.625 6.74 2.725 3.42 2.725 3.42 3.525 6.815 3.525 6.815 3.84 ;
    END
  END Y
  PIN VDD
    DIRECTION INPUT ;
    USE POWER ;
    PORT
      LAYER METAL1 ;
        POLYGON 8.58 5.44 8.58 4.64 8.4 4.64 8.4 4.465 8.06 4.465 8.06 4.64 7.04 4.64 7.04 4.465 6.7 4.465 6.7 4.64 5.68 4.64 5.68 4.02 5.34 4.02 5.34 4.64 4.4 4.64 4.4 4.02 4.06 4.02 4.06 4.64 3.12 4.64 3.12 4.02 2.78 4.02 2.78 4.64 1.8 4.64 1.8 3.395 1.46 3.395 1.46 4.64 0.52 4.64 0.52 3.395 0.18 3.395 0.18 4.64 0 4.64 0 5.44 ;
    END
  END VDD
  PIN VSS
    DIRECTION INPUT ;
    USE GROUND ;
    PORT
      LAYER METAL1 ;
        POLYGON 2.44 0.97 2.44 0.4 3.42 0.4 3.42 0.895 3.76 0.895 3.76 0.4 4.7 0.4 4.7 0.895 5.04 0.895 5.04 0.4 6.02 0.4 6.02 0.895 6.36 0.895 6.36 0.4 7.38 0.4 7.38 0.575 7.72 0.575 7.72 0.4 8.58 0.4 8.58 -0.4 0 -0.4 0 0.4 0.82 0.4 0.82 0.965 1.16 0.965 1.16 0.4 2.1 0.4 2.1 0.97 ;
    END
  END VSS
  OBS
    LAYER METAL1 ;
      POLYGON 2.505 3.12 2.505 2.495 6.51 2.495 6.51 2.155 2.505 2.155 2.505 1.405 0.18 1.405 0.18 1.745 2.275 1.745 2.275 2.76 2.1 2.76 2.1 2.89 1.16 2.89 1.16 2.76 0.82 2.76 0.82 3.12 ;
  END
END BUFX16

MACRO AND3XL
  CLASS CORE ;
  FOREIGN AND3XL ;
  ORIGIN 0 0 ;
  SIZE 3.3 BY 5.04 ;
  SYMMETRY X Y ;
  SITE unit ;
  PIN A
    DIRECTION INPUT ;
    USE SIGNAL ;
    PORT
      LAYER METAL1 ;
        RECT 0.14 1.79 0.58 2.3 ;
    END
  END A
  PIN B
    DIRECTION INPUT ;
    USE SIGNAL ;
    PORT
      LAYER METAL1 ;
        RECT 0.63 2.845 1.135 3.3 ;
    END
  END B
  PIN C
    DIRECTION INPUT ;
    USE SIGNAL ;
    PORT
      LAYER METAL1 ;
        RECT 1.455 1.715 1.975 2.145 ;
    END
  END C
  PIN Y
    DIRECTION OUTPUT ;
    USE SIGNAL ;
    PORT
      LAYER METAL1 ;
        POLYGON 3.16 4.24 3.16 3.495 3.15 3.495 3.15 1.15 2.78 1.15 2.78 1.49 2.92 1.49 2.92 3.495 2.74 3.495 2.74 4.24 ;
    END
  END Y
  PIN VDD
    DIRECTION INPUT ;
    USE POWER ;
    PORT
      LAYER METAL1 ;
        POLYGON 3.3 5.44 3.3 4.64 2.465 4.64 2.465 3.125 2.69 3.125 2.69 2.62 2.235 2.62 2.235 4.64 1.34 4.64 1.34 4.465 1.335 4.465 1.335 4.41 1.01 4.41 1.01 4.465 1 4.465 1 4.64 0 4.64 0 5.44 ;
    END
  END VDD
  PIN VSS
    DIRECTION INPUT ;
    USE GROUND ;
    PORT
      LAYER METAL1 ;
        POLYGON 2.34 0.575 2.34 0.4 3.3 0.4 3.3 -0.4 0 -0.4 0 0.4 2 0.4 2 0.575 ;
    END
  END VSS
  OBS
    LAYER METAL1 ;
      POLYGON 0.54 4.355 0.54 4.18 1.75 4.18 1.75 2.38 1.055 2.38 1.055 1.355 2.32 1.355 2.32 2.1 2.69 2.1 2.69 1.75 2.55 1.75 2.55 1.125 0.52 1.125 0.52 1.07 0.18 1.07 0.18 1.41 0.52 1.41 0.52 1.355 0.825 1.355 0.825 2.61 1.465 2.61 1.465 3.125 1.52 3.125 1.52 3.95 0.2 3.95 0.2 4.355 ;
  END
END AND3XL

MACRO AND4XL
  CLASS CORE ;
  FOREIGN AND4XL ;
  ORIGIN 0 0 ;
  SIZE 3.96 BY 5.04 ;
  SYMMETRY X Y ;
  SITE unit ;
  PIN A
    DIRECTION INPUT ;
    USE SIGNAL ;
    PORT
      LAYER METAL1 ;
        RECT 0.14 2.545 0.52 3.22 ;
    END
  END A
  PIN B
    DIRECTION INPUT ;
    USE SIGNAL ;
    PORT
      LAYER METAL1 ;
        RECT 0.8 2.135 1.18 2.89 ;
    END
  END B
  PIN C
    DIRECTION INPUT ;
    USE SIGNAL ;
    PORT
      LAYER METAL1 ;
        RECT 1.46 2.135 1.84 2.89 ;
    END
  END C
  PIN D
    DIRECTION INPUT ;
    USE SIGNAL ;
    PORT
      LAYER METAL1 ;
        RECT 2.54 2.405 3.105 2.89 ;
    END
  END D
  PIN Y
    DIRECTION OUTPUT ;
    USE SIGNAL ;
    PORT
      LAYER METAL1 ;
        POLYGON 3.82 3.78 3.82 3.19 3.705 3.19 3.705 1.015 3.475 1.015 3.475 3.19 3.42 3.19 3.42 3.78 ;
    END
  END Y
  PIN VDD
    DIRECTION INPUT ;
    USE POWER ;
    PORT
      LAYER METAL1 ;
        POLYGON 3.96 5.44 3.96 4.64 3.1 4.64 3.1 4.465 0.93 4.465 0.93 4.64 0 4.64 0 5.44 ;
    END
  END VDD
  PIN VSS
    DIRECTION INPUT ;
    USE GROUND ;
    PORT
      LAYER METAL1 ;
        POLYGON 3 0.575 3 0.4 3.96 0.4 3.96 -0.4 0 -0.4 0 0.4 2.66 0.4 2.66 0.575 ;
    END
  END VSS
  OBS
    LAYER METAL1 ;
      POLYGON 2.26 3.725 2.26 3.46 2.3 3.46 2.3 1.91 3.225 1.91 3.225 1.54 2.3 1.54 2.3 0.975 0.18 0.975 0.18 1.315 0.52 1.315 0.52 1.205 2.07 1.205 2.07 3.155 1.92 3.155 1.92 3.495 0.52 3.495 0.52 3.725 ;
  END
END AND4XL

MACRO BUFX2
  CLASS CORE ;
  FOREIGN BUFX2 ;
  ORIGIN 0 0 ;
  SIZE 2.64 BY 5.04 ;
  SYMMETRY X Y ;
  SITE unit ;
  PIN A
    DIRECTION INPUT ;
    USE SIGNAL ;
    PORT
      LAYER METAL1 ;
        RECT 0.14 1.755 0.89 2.26 ;
    END
  END A
  PIN Y
    DIRECTION OUTPUT ;
    USE SIGNAL ;
    PORT
      LAYER METAL1 ;
        POLYGON 1.94 3.09 1.94 2.98 2.35 2.98 2.35 2.075 2.425 2.075 2.425 1.845 2.35 1.845 2.35 1.5 1.98 1.5 1.98 1.39 1.64 1.39 1.64 1.73 2.12 1.73 2.12 2.75 1.6 2.75 1.6 3.09 ;
    END
  END Y
  PIN VDD
    DIRECTION INPUT ;
    USE POWER ;
    PORT
      LAYER METAL1 ;
        POLYGON 2.64 5.44 2.64 4.64 1.18 4.64 1.18 4.465 1.125 4.465 1.125 4.41 0.895 4.41 0.895 4.465 0.84 4.465 0.84 4.64 0 4.64 0 5.44 ;
    END
  END VDD
  PIN VSS
    DIRECTION INPUT ;
    USE GROUND ;
    PORT
      LAYER METAL1 ;
        POLYGON 1.22 0.575 1.22 0.4 2.64 0.4 2.64 -0.4 0 -0.4 0 0.4 0.88 0.4 0.88 0.575 ;
    END
  END VSS
  OBS
    LAYER METAL1 ;
      POLYGON 0.62 3.1 0.62 2.99 1.37 2.99 1.37 2.4 1.62 2.4 1.62 2.06 1.37 2.06 1.37 1.265 0.62 1.265 0.62 1.155 0.28 1.155 0.28 1.495 1.14 1.495 1.14 2.76 0.28 2.76 0.28 3.1 ;
  END
END BUFX2

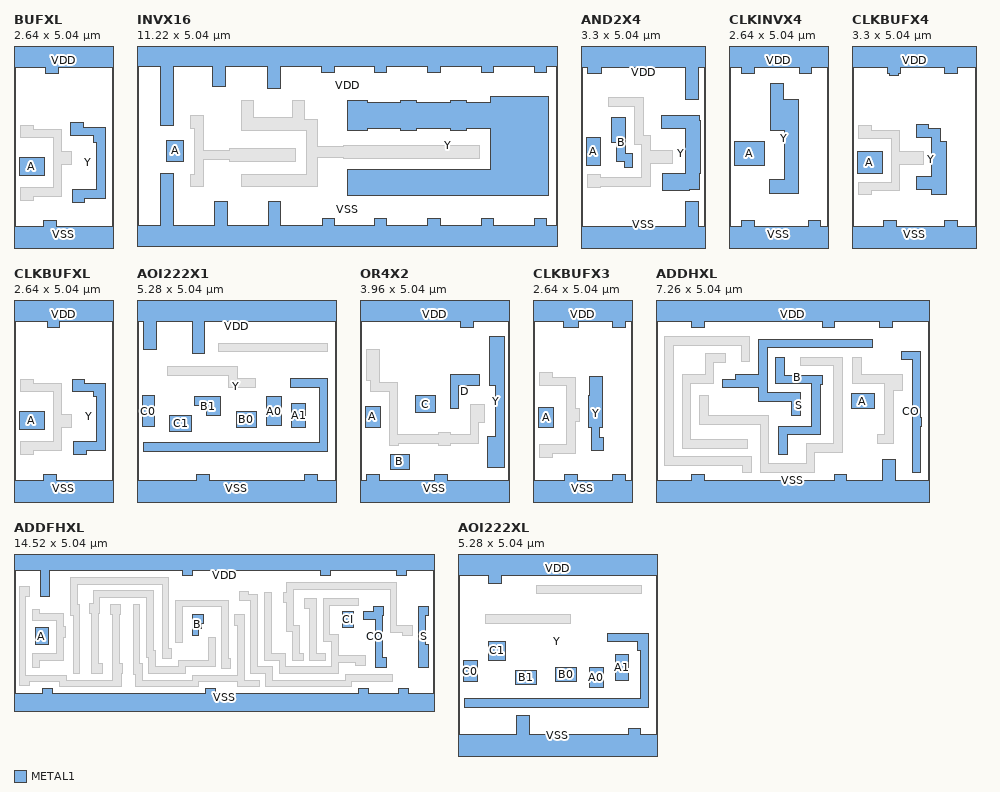
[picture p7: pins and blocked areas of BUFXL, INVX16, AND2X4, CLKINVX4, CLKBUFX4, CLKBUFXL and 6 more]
MACRO BUFXL
  CLASS CORE ;
  FOREIGN BUFXL ;
  ORIGIN 0 0 ;
  SIZE 2.64 BY 5.04 ;
  SYMMETRY X Y ;
  SITE unit ;
  PIN A
    DIRECTION INPUT ;
    USE SIGNAL ;
    PORT
      LAYER METAL1 ;
        RECT 0.14 1.755 0.81 2.245 ;
    END
  END A
  PIN Y
    DIRECTION OUTPUT ;
    USE SIGNAL ;
    PORT
      LAYER METAL1 ;
        POLYGON 1.84 3.16 1.84 3.05 2.425 3.05 2.425 1.15 1.88 1.15 1.88 1.04 1.54 1.04 1.54 1.38 2.195 1.38 2.195 2.635 2.12 2.635 2.12 2.82 1.5 2.82 1.5 3.16 ;
    END
  END Y
  PIN VDD
    DIRECTION INPUT ;
    USE POWER ;
    PORT
      LAYER METAL1 ;
        POLYGON 2.64 5.44 2.64 4.64 1.18 4.64 1.18 4.465 0.84 4.465 0.84 4.64 0 4.64 0 5.44 ;
    END
  END VDD
  PIN VSS
    DIRECTION INPUT ;
    USE GROUND ;
    PORT
      LAYER METAL1 ;
        POLYGON 1.12 0.575 1.12 0.4 2.64 0.4 2.64 -0.4 0 -0.4 0 0.4 0.78 0.4 0.78 0.575 ;
    END
  END VSS
  OBS
    LAYER METAL1 ;
      POLYGON 0.52 3.1 0.52 2.99 1.27 2.99 1.27 2.4 1.52 2.4 1.52 2.06 1.27 2.06 1.27 1.22 0.52 1.22 0.52 1.11 0.18 1.11 0.18 1.45 1.04 1.45 1.04 2.76 0.18 2.76 0.18 3.1 ;
  END
END BUFXL

MACRO INVX16
  CLASS CORE ;
  FOREIGN INVX16 ;
  ORIGIN 0 0 ;
  SIZE 11.22 BY 5.04 ;
  SYMMETRY X Y ;
  SITE unit ;
  PIN A
    DIRECTION INPUT ;
    USE SIGNAL ;
    PORT
      LAYER METAL1 ;
        RECT 0.8 2.1 1.255 2.66 ;
    END
  END A
  PIN Y
    DIRECTION OUTPUT ;
    USE SIGNAL ;
    PORT
      LAYER METAL1 ;
        POLYGON 11.005 3.84 11.005 1.2 7.215 1.2 7.215 1.195 5.625 1.195 5.625 1.875 6.875 1.875 6.875 1.88 9.455 1.88 9.455 2.99 8.815 2.99 8.815 2.925 8.365 2.925 8.365 2.99 7.475 2.99 7.475 2.925 7.045 2.925 7.045 2.99 6.155 2.99 6.155 2.925 5.625 2.925 5.625 3.735 6.155 3.735 6.155 3.67 7.045 3.67 7.045 3.735 7.475 3.735 7.475 3.67 8.365 3.67 8.365 3.735 8.815 3.735 8.815 3.67 9.455 3.67 9.455 3.84 ;
    END
  END Y
  PIN VDD
    DIRECTION INPUT ;
    USE POWER ;
    PORT
      LAYER METAL1 ;
        POLYGON 11.22 5.44 11.22 4.64 10.95 4.64 10.95 4.465 10.61 4.465 10.61 4.64 9.53 4.64 9.53 4.465 9.19 4.465 9.19 4.64 8.095 4.64 8.095 4.465 7.755 4.465 7.755 4.64 6.675 4.64 6.675 4.465 6.335 4.465 6.335 4.64 5.27 4.64 5.27 4.465 4.93 4.465 4.93 4.64 3.835 4.64 3.835 4.06 3.495 4.06 3.495 4.64 2.365 4.64 2.365 4.09 2.025 4.09 2.025 4.64 0.965 4.64 0.965 3.05 0.625 3.05 0.625 4.64 0 4.64 0 5.44 ;
    END
  END VDD
  PIN VSS
    DIRECTION INPUT ;
    USE GROUND ;
    PORT
      LAYER METAL1 ;
        POLYGON 0.965 1.78 0.965 0.4 2.075 0.4 2.075 1.02 2.415 1.02 2.415 0.4 3.5 0.4 3.5 1.02 3.84 1.02 3.84 0.4 4.945 0.4 4.945 0.575 5.285 0.575 5.285 0.4 6.335 0.4 6.335 0.575 6.675 0.575 6.675 0.4 7.76 0.4 7.76 0.575 8.1 0.575 8.1 0.4 9.19 0.4 9.19 0.575 9.53 0.575 9.53 0.4 10.61 0.4 10.61 0.575 10.95 0.575 10.95 0.4 11.22 0.4 11.22 -0.4 0 -0.4 0 0.4 0.625 0.4 0.625 1.78 ;
    END
  END VSS
  OBS
    LAYER METAL1 ;
      POLYGON 4.485 3.735 4.485 3.225 4.82 3.225 4.82 2.51 5.52 2.51 5.52 2.53 9.15 2.53 9.15 2.19 5.52 2.19 5.52 2.21 4.82 2.21 4.82 1.42 2.79 1.42 2.79 1.76 4.52 1.76 4.52 2.925 2.785 2.925 2.785 3.735 3.125 3.735 3.125 3.265 4.145 3.265 4.145 3.735 ;
      POLYGON 1.775 3.315 1.775 2.385 2.48 2.385 2.48 2.44 4.23 2.44 4.23 2.1 2.48 2.1 2.48 2.155 1.775 2.155 1.775 1.42 1.435 1.42 1.435 1.76 1.545 1.76 1.545 2.975 1.435 2.975 1.435 3.315 ;
  END
END INVX16

MACRO AND2X4
  CLASS CORE ;
  FOREIGN AND2X4 ;
  ORIGIN 0 0 ;
  SIZE 3.3 BY 5.04 ;
  SYMMETRY X Y ;
  SITE unit ;
  PIN A
    DIRECTION INPUT ;
    USE SIGNAL ;
    PORT
      LAYER METAL1 ;
        POLYGON 0.52 2.77 0.52 2.41 0.53 2.41 0.53 2.025 0.14 2.025 0.14 2.77 ;
    END
  END A
  PIN B
    DIRECTION INPUT ;
    USE SIGNAL ;
    PORT
      LAYER METAL1 ;
        POLYGON 1.18 3.3 1.18 2.36 1.375 2.36 1.375 1.98 1.145 1.98 1.145 2.13 0.95 2.13 0.95 2.635 0.8 2.635 0.8 3.3 ;
    END
  END B
  PIN Y
    DIRECTION OUTPUT ;
    USE SIGNAL ;
    PORT
      LAYER METAL1 ;
        POLYGON 3.155 3.35 3.155 3.22 3.16 3.22 3.16 1.82 3.155 1.82 3.155 1.39 2.875 1.39 2.875 1.37 2.17 1.37 2.17 1.82 2.78 1.82 2.78 3.01 2.125 3.01 2.125 3.35 ;
    END
  END Y
  PIN VDD
    DIRECTION INPUT ;
    USE POWER ;
    PORT
      LAYER METAL1 ;
        POLYGON 3.3 5.44 3.3 4.64 3.11 4.64 3.11 3.775 2.77 3.775 2.77 4.64 1.785 4.64 1.785 4.465 1.445 4.465 1.445 4.64 0.535 4.64 0.535 4.465 0.17 4.465 0.17 4.64 0 4.64 0 5.44 ;
    END
  END VDD
  PIN VSS
    DIRECTION INPUT ;
    USE GROUND ;
    PORT
      LAYER METAL1 ;
        POLYGON 3.11 1.085 3.11 0.4 3.3 0.4 3.3 -0.4 0 -0.4 0 0.4 1.42 0.4 1.42 0.575 1.76 0.575 1.76 0.4 2.77 0.4 2.77 1.085 ;
    END
  END VSS
  OBS
    LAYER METAL1 ;
      POLYGON 1.645 3.82 1.645 2.82 1.845 2.82 1.845 2.43 2.43 2.43 2.43 2.09 1.845 2.09 1.845 1.485 0.52 1.485 0.52 1.44 0.18 1.44 0.18 1.78 0.52 1.78 0.52 1.715 1.615 1.715 1.615 2.59 1.415 2.59 1.415 3.59 0.74 3.59 0.74 3.82 ;
  END
END AND2X4

MACRO CLKINVX4
  CLASS CORE ;
  FOREIGN CLKINVX4 ;
  ORIGIN 0 0 ;
  SIZE 2.64 BY 5.04 ;
  SYMMETRY X Y ;
  SITE unit ;
  PIN A
    DIRECTION INPUT ;
    USE SIGNAL ;
    PORT
      LAYER METAL1 ;
        RECT 0.14 2.02 0.95 2.66 ;
    END
  END A
  PIN Y
    DIRECTION OUTPUT ;
    USE SIGNAL ;
    PORT
      LAYER METAL1 ;
        POLYGON 1.44 4.205 1.44 3.78 1.84 3.78 1.84 1.29 1.08 1.29 1.08 1.67 1.46 1.67 1.46 2.965 1.1 2.965 1.1 4.205 ;
    END
  END Y
  PIN VDD
    DIRECTION INPUT ;
    USE POWER ;
    PORT
      LAYER METAL1 ;
        POLYGON 2.64 5.44 2.64 4.64 2.2 4.64 2.2 4.465 1.86 4.465 1.86 4.64 0.68 4.64 0.68 4.465 0.34 4.465 0.34 4.64 0 4.64 0 5.44 ;
    END
  END VDD
  PIN VSS
    DIRECTION INPUT ;
    USE GROUND ;
    PORT
      LAYER METAL1 ;
        POLYGON 2.44 0.575 2.44 0.4 2.64 0.4 2.64 -0.4 0 -0.4 0 0.4 0.34 0.4 0.34 0.575 0.68 0.575 0.68 0.4 2.1 0.4 2.1 0.575 ;
    END
  END VSS
END CLKINVX4

MACRO CLKBUFX4
  CLASS CORE ;
  FOREIGN CLKBUFX4 ;
  ORIGIN 0 0 ;
  SIZE 3.3 BY 5.04 ;
  SYMMETRY X Y ;
  SITE unit ;
  PIN A
    DIRECTION INPUT ;
    USE SIGNAL ;
    PORT
      LAYER METAL1 ;
        RECT 0.14 1.82 0.81 2.395 ;
    END
  END A
  PIN Y
    DIRECTION OUTPUT ;
    USE SIGNAL ;
    PORT
      LAYER METAL1 ;
        POLYGON 2.04 3.11 2.04 3 2.35 3 2.35 2.66 2.5 2.66 2.5 1.26 2.12 1.26 2.12 1.39 1.7 1.39 1.7 1.73 2.12 1.73 2.12 2.77 1.7 2.77 1.7 3.11 ;
    END
  END Y
  PIN VDD
    DIRECTION INPUT ;
    USE POWER ;
    PORT
      LAYER METAL1 ;
        POLYGON 3.3 5.44 3.3 4.64 2.8 4.64 2.8 4.465 2.46 4.465 2.46 4.64 1.28 4.64 1.28 4.465 1.225 4.465 1.225 4.41 0.995 4.41 0.995 4.465 0.94 4.465 0.94 4.64 0 4.64 0 5.44 ;
    END
  END VDD
  PIN VSS
    DIRECTION INPUT ;
    USE GROUND ;
    PORT
      LAYER METAL1 ;
        POLYGON 2.8 0.575 2.8 0.4 3.3 0.4 3.3 -0.4 0 -0.4 0 0.4 0.84 0.4 0.84 0.575 1.18 0.575 1.18 0.4 2.46 0.4 2.46 0.575 ;
    END
  END VSS
  OBS
    LAYER METAL1 ;
      POLYGON 0.52 3.08 0.52 2.97 1.27 2.97 1.27 2.4 1.89 2.4 1.89 2.06 1.27 2.06 1.27 1.36 0.52 1.36 0.52 1.25 0.18 1.25 0.18 1.59 1.04 1.59 1.04 2.74 0.18 2.74 0.18 3.08 ;
  END
END CLKBUFX4

MACRO CLKBUFXL
  CLASS CORE ;
  FOREIGN CLKBUFXL ;
  ORIGIN 0 0 ;
  SIZE 2.64 BY 5.04 ;
  SYMMETRY X Y ;
  SITE unit ;
  PIN A
    DIRECTION INPUT ;
    USE SIGNAL ;
    PORT
      LAYER METAL1 ;
        RECT 0.14 1.755 0.81 2.245 ;
    END
  END A
  PIN Y
    DIRECTION OUTPUT ;
    USE SIGNAL ;
    PORT
      LAYER METAL1 ;
        POLYGON 1.88 3.1 1.88 2.99 2.425 2.99 2.425 1.22 1.92 1.22 1.92 1.11 1.58 1.11 1.58 1.45 2.195 1.45 2.195 2.635 2.12 2.635 2.12 2.76 1.54 2.76 1.54 3.1 ;
    END
  END Y
  PIN VDD
    DIRECTION INPUT ;
    USE POWER ;
    PORT
      LAYER METAL1 ;
        POLYGON 2.64 5.44 2.64 4.64 1.22 4.64 1.22 4.465 0.88 4.465 0.88 4.64 0 4.64 0 5.44 ;
    END
  END VDD
  PIN VSS
    DIRECTION INPUT ;
    USE GROUND ;
    PORT
      LAYER METAL1 ;
        POLYGON 1.12 0.575 1.12 0.4 2.64 0.4 2.64 -0.4 0 -0.4 0 0.4 0.78 0.4 0.78 0.575 ;
    END
  END VSS
  OBS
    LAYER METAL1 ;
      POLYGON 0.52 3.1 0.52 2.99 1.27 2.99 1.27 2.16 1.52 2.16 1.52 1.82 1.27 1.82 1.27 1.22 0.52 1.22 0.52 1.11 0.18 1.11 0.18 1.45 1.04 1.45 1.04 2.76 0.18 2.76 0.18 3.1 ;
  END
END CLKBUFXL

MACRO AOI222X1
  CLASS CORE ;
  FOREIGN AOI222X1 ;
  ORIGIN 0 0 ;
  SIZE 5.28 BY 5.04 ;
  SYMMETRY X Y ;
  SITE unit ;
  PIN A0
    DIRECTION INPUT ;
    USE SIGNAL ;
    PORT
      LAYER METAL1 ;
        RECT 3.44 1.865 3.82 2.635 ;
    END
  END A0
  PIN A1
    DIRECTION INPUT ;
    USE SIGNAL ;
    PORT
      LAYER METAL1 ;
        RECT 4.1 1.82 4.48 2.465 ;
    END
  END A1
  PIN B0
    DIRECTION INPUT ;
    USE SIGNAL ;
    PORT
      LAYER METAL1 ;
        RECT 2.645 1.82 3.16 2.245 ;
    END
  END B0
  PIN B1
    DIRECTION INPUT ;
    USE SIGNAL ;
    PORT
      LAYER METAL1 ;
        POLYGON 2.21 2.635 2.21 2.125 1.84 2.125 1.84 2.405 1.535 2.405 1.535 2.635 ;
    END
  END B1
  PIN C0
    DIRECTION INPUT ;
    USE SIGNAL ;
    PORT
      LAYER METAL1 ;
        RECT 0.14 1.845 0.46 2.66 ;
    END
  END C0
  PIN C1
    DIRECTION INPUT ;
    USE SIGNAL ;
    PORT
      LAYER METAL1 ;
        RECT 0.875 1.7 1.435 2.13 ;
    END
  END C1
  PIN Y
    DIRECTION OUTPUT ;
    USE SIGNAL ;
    PORT
      LAYER METAL1 ;
        POLYGON 5.065 3.12 5.065 1.18 0.18 1.18 0.18 1.41 4.835 1.41 4.835 2.89 4.085 2.89 4.085 3.12 ;
    END
  END Y
  PIN VDD
    DIRECTION INPUT ;
    USE POWER ;
    PORT
      LAYER METAL1 ;
        POLYGON 5.28 5.44 5.28 4.64 1.8 4.64 1.8 3.79 1.46 3.79 1.46 4.64 0.52 4.64 0.52 3.89 0.18 3.89 0.18 4.64 0 4.64 0 5.44 ;
    END
  END VDD
  PIN VSS
    DIRECTION INPUT ;
    USE GROUND ;
    PORT
      LAYER METAL1 ;
        POLYGON 4.785 0.575 4.785 0.4 5.28 0.4 5.28 -0.4 0 -0.4 0 0.4 1.575 0.4 1.575 0.575 1.915 0.575 1.915 0.4 4.445 0.4 4.445 0.575 ;
    END
  END VSS
  OBS
    LAYER METAL1 ;
      RECT 2.165 3.82 5.065 4.05 ;
      POLYGON 2.665 3.43 2.665 3.105 3.145 3.105 3.145 2.875 2.435 2.875 2.435 3.2 0.82 3.2 0.82 3.43 ;
  END
END AOI222X1

MACRO OR4X2
  CLASS CORE ;
  FOREIGN OR4X2 ;
  ORIGIN 0 0 ;
  SIZE 3.96 BY 5.04 ;
  SYMMETRY X Y ;
  SITE unit ;
  PIN A
    DIRECTION INPUT ;
    USE SIGNAL ;
    PORT
      LAYER METAL1 ;
        RECT 0.14 1.82 0.545 2.38 ;
    END
  END A
  PIN B
    DIRECTION INPUT ;
    USE SIGNAL ;
    PORT
      LAYER METAL1 ;
        RECT 0.8 0.7 1.31 1.11 ;
    END
  END B
  PIN C
    DIRECTION INPUT ;
    USE SIGNAL ;
    PORT
      LAYER METAL1 ;
        RECT 1.46 2.215 2 2.66 ;
    END
  END C
  PIN D
    DIRECTION INPUT ;
    USE SIGNAL ;
    PORT
      LAYER METAL1 ;
        POLYGON 3.16 3.22 3.16 2.94 2.62 2.94 2.62 2.32 2.39 2.32 2.39 3.22 ;
    END
  END D
  PIN Y
    DIRECTION OUTPUT ;
    USE SIGNAL ;
    PORT
      LAYER METAL1 ;
        POLYGON 3.82 4.24 3.82 0.765 3.39 0.765 3.39 1.575 3.59 1.575 3.59 2.94 3.43 2.94 3.43 4.24 ;
    END
  END Y
  PIN VDD
    DIRECTION INPUT ;
    USE POWER ;
    PORT
      LAYER METAL1 ;
        POLYGON 3.96 5.44 3.96 4.64 3.01 4.64 3.01 4.465 2.67 4.465 2.67 4.64 0 4.64 0 5.44 ;
    END
  END VDD
  PIN VSS
    DIRECTION INPUT ;
    USE GROUND ;
    PORT
      LAYER METAL1 ;
        POLYGON 2.325 0.575 2.325 0.4 3.96 0.4 3.96 -0.4 0 -0.4 0 0.4 0.18 0.4 0.18 0.575 0.52 0.575 0.52 0.4 1.985 0.4 1.985 0.575 ;
    END
  END VSS
  OBS
    LAYER METAL1 ;
      POLYGON 0.52 3.88 0.52 3.01 1.005 3.01 1.005 1.63 2.07 1.63 2.07 1.685 2.41 1.685 2.41 1.63 2.925 1.63 2.925 2.42 3.305 2.42 3.305 1.94 3.155 1.94 3.155 1.4 2.41 1.4 2.41 1.345 2.07 1.345 2.07 1.4 1.025 1.4 1.025 1.345 0.775 1.345 0.775 2.78 0.29 2.78 0.29 3.07 0.18 3.07 0.18 3.88 ;
  END
END OR4X2

MACRO CLKBUFX3
  CLASS CORE ;
  FOREIGN CLKBUFX3 ;
  ORIGIN 0 0 ;
  SIZE 2.64 BY 5.04 ;
  SYMMETRY X Y ;
  SITE unit ;
  PIN A
    DIRECTION INPUT ;
    USE SIGNAL ;
    PORT
      LAYER METAL1 ;
        RECT 0.14 1.82 0.555 2.36 ;
    END
  END A
  PIN Y
    DIRECTION OUTPUT ;
    USE SIGNAL ;
    PORT
      LAYER METAL1 ;
        POLYGON 1.84 3.16 1.84 1.82 1.77 1.82 1.77 1.545 1.88 1.545 1.88 1.205 1.54 1.205 1.54 1.82 1.46 1.82 1.46 2.66 1.5 2.66 1.5 3.16 ;
    END
  END Y
  PIN VDD
    DIRECTION INPUT ;
    USE POWER ;
    PORT
      LAYER METAL1 ;
        POLYGON 2.64 5.44 2.64 4.64 2.46 4.64 2.46 4.465 2.12 4.465 2.12 4.64 1.195 4.64 1.195 4.465 0.81 4.465 0.81 4.64 0 4.64 0 5.44 ;
    END
  END VDD
  PIN VSS
    DIRECTION INPUT ;
    USE GROUND ;
    PORT
      LAYER METAL1 ;
        POLYGON 2.46 0.575 2.46 0.4 2.64 0.4 2.64 -0.4 0 -0.4 0 0.4 0.84 0.4 0.84 0.575 1.18 0.575 1.18 0.4 2.12 0.4 2.12 0.575 ;
    END
  END VSS
  OBS
    LAYER METAL1 ;
      POLYGON 0.52 3.265 0.52 3.155 1.115 3.155 1.115 2.315 1.225 2.315 1.225 1.975 1.115 1.975 1.115 1.135 0.52 1.135 0.52 1.025 0.18 1.025 0.18 1.365 0.885 1.365 0.885 2.925 0.18 2.925 0.18 3.265 ;
  END
END CLKBUFX3

MACRO ADDHXL
  CLASS CORE ;
  FOREIGN ADDHXL ;
  ORIGIN 0 0 ;
  SIZE 7.26 BY 5.04 ;
  SYMMETRY X Y ;
  SITE unit ;
  PIN A
    DIRECTION INPUT ;
    USE SIGNAL ;
    PORT
      LAYER METAL1 ;
        RECT 5.18 2.31 5.8 2.73 ;
    END
  END A
  PIN B
    DIRECTION INPUT ;
    USE SIGNAL ;
    PORT
      LAYER METAL1 ;
        POLYGON 5.745 4.16 5.745 3.93 2.95 3.93 2.95 2.74 3.835 2.74 3.835 2.135 3.605 2.135 3.605 2.51 2.72 2.51 2.72 2.865 1.775 2.865 1.775 3.095 2.12 3.095 2.12 3.22 2.72 3.22 2.72 4.16 ;
    END
  END B
  PIN CO
    DIRECTION OUTPUT ;
    USE SIGNAL ;
    PORT
      LAYER METAL1 ;
        POLYGON 7.025 3.845 7.025 2.075 7.045 2.075 7.045 1.845 7.025 1.845 7.025 0.63 6.795 0.63 6.795 3.615 6.5 3.615 6.5 3.845 ;
    END
  END CO
  PIN S
    DIRECTION OUTPUT ;
    USE SIGNAL ;
    PORT
      LAYER METAL1 ;
        POLYGON 3.41 3.685 3.41 3.205 4.405 3.205 4.405 2.965 4.355 2.965 4.355 1.625 3.49 1.625 3.49 1.095 3.26 1.095 3.26 1.855 4.125 1.855 4.125 2.975 3.18 2.975 3.18 3.685 ;
    END
  END S
  PIN VDD
    DIRECTION INPUT ;
    USE POWER ;
    PORT
      LAYER METAL1 ;
        POLYGON 7.26 5.44 7.26 4.64 6.275 4.64 6.275 4.465 5.935 4.465 5.935 4.64 4.745 4.64 4.745 4.465 4.405 4.465 4.405 4.64 1.28 4.64 1.28 4.465 0.94 4.465 0.94 4.64 0 4.64 0 5.44 ;
    END
  END VDD
  PIN VSS
    DIRECTION INPUT ;
    USE GROUND ;
    PORT
      LAYER METAL1 ;
        POLYGON 6.36 0.97 6.36 0.4 7.26 0.4 7.26 -0.4 0 -0.4 0 0.4 0.94 0.4 0.94 0.575 1.28 0.575 1.28 0.4 4.725 0.4 4.725 0.575 5.065 0.575 5.065 0.4 6.02 0.4 6.02 0.97 ;
    END
  END VSS
  OBS
    LAYER METAL1 ;
      POLYGON 2.485 4.235 2.485 3.58 2.255 3.58 2.255 4.005 0.465 4.005 0.465 1.035 2.53 1.035 2.53 0.635 2.3 0.635 2.3 0.805 0.235 0.805 0.235 4.235 ;
      POLYGON 1.84 3.775 1.84 3.545 1.535 3.545 1.535 2.985 0.925 2.985 0.925 1.495 2.425 1.495 2.425 1.265 0.695 1.265 0.695 3.215 1.305 3.215 1.305 3.775 ;
      POLYGON 5.45 3.685 5.45 3.215 6.54 3.215 6.54 2.81 6.3 2.81 6.3 1.39 5.885 1.39 5.885 1.62 6.07 1.62 6.07 2.985 5.22 2.985 5.22 3.685 ;
      POLYGON 4.94 3.685 4.94 1.155 4.21 1.155 4.21 0.63 2.765 0.63 2.765 1.905 1.16 1.905 1.16 2.67 1.39 2.67 1.39 2.135 2.995 2.135 2.995 0.86 3.98 0.86 3.98 1.385 4.71 1.385 4.71 3.455 3.845 3.455 3.845 3.685 ;
  END
END ADDHXL

MACRO ADDFHXL
  CLASS CORE ;
  FOREIGN ADDFHXL ;
  ORIGIN 0 0 ;
  SIZE 14.52 BY 5.04 ;
  SYMMETRY X Y ;
  SITE unit ;
  PIN A
    DIRECTION INPUT ;
    USE SIGNAL ;
    PORT
      LAYER METAL1 ;
        RECT 0.75 2.085 1.18 2.67 ;
    END
  END A
  PIN B
    DIRECTION INPUT ;
    USE SIGNAL ;
    PORT
      LAYER METAL1 ;
        POLYGON 6.54 3.145 6.54 2.805 6.49 2.805 6.49 2.66 6.385 2.66 6.385 2.405 6.155 2.405 6.155 3.145 ;
    END
  END B
  PIN CI
    DIRECTION INPUT ;
    USE SIGNAL ;
    PORT
      LAYER METAL1 ;
        RECT 11.36 2.675 11.745 3.22 ;
    END
  END CI
  PIN CO
    DIRECTION OUTPUT ;
    USE SIGNAL ;
    PORT
      LAYER METAL1 ;
        POLYGON 12.78 3.42 12.78 3.08 12.725 3.08 12.725 1.625 12.865 1.625 12.865 1.285 12.495 1.285 12.495 2.94 12.09 2.94 12.09 3.22 12.44 3.22 12.44 3.42 ;
    END
  END CO
  PIN S
    DIRECTION OUTPUT ;
    USE SIGNAL ;
    PORT
      LAYER METAL1 ;
        POLYGON 14.34 3.42 14.34 3.08 14.23 3.08 14.23 2.1 14.34 2.1 14.34 1.285 14 1.285 14 3.42 ;
    END
  END S
  PIN VDD
    DIRECTION INPUT ;
    USE POWER ;
    PORT
      LAYER METAL1 ;
        POLYGON 14.52 5.44 14.52 4.64 13.56 4.64 13.56 4.465 13.22 4.465 13.22 4.64 10.94 4.64 10.94 4.465 10.6 4.465 10.6 4.64 6.16 4.64 6.16 4.465 5.82 4.465 5.82 4.64 1.24 4.64 1.24 3.76 0.9 3.76 0.9 4.64 0 4.64 0 5.44 ;
    END
  END VDD
  PIN VSS
    DIRECTION INPUT ;
    USE GROUND ;
    PORT
      LAYER METAL1 ;
        POLYGON 13.625 0.575 13.625 0.4 14.52 0.4 14.52 -0.4 0 -0.4 0 0.4 0.98 0.4 0.98 0.575 1.32 0.575 1.32 0.4 6.615 0.4 6.615 0.575 6.955 0.575 6.955 0.4 11.915 0.4 11.915 0.575 12.255 0.575 12.255 0.4 13.285 0.4 13.285 0.575 ;
    END
  END VSS
  OBS
    LAYER METAL1 ;
      POLYGON 5.35 4.41 5.35 1.94 5.46 1.94 5.46 1.6 5.12 1.6 5.12 4.18 2.19 4.18 2.19 3.475 2.27 3.475 2.27 1.09 2.04 1.09 2.04 3.1 1.96 3.1 1.96 4.41 ;
      POLYGON 13.24 4.23 13.24 2.74 13.76 2.74 13.76 2.4 13.42 2.4 13.42 2.51 13.01 2.51 13.01 4 9.66 4 9.66 2.76 9.86 2.76 9.86 1.78 9.995 1.78 9.995 1.55 9.63 1.55 9.63 2.53 9.43 2.53 9.43 3.545 9.32 3.545 9.32 3.885 9.43 3.885 9.43 4.23 ;
      POLYGON 0.52 4.1 0.52 3.76 0.41 3.76 0.41 1.035 1.81 1.035 1.81 0.86 3.4 0.86 3.4 3.125 3.345 3.125 3.345 3.465 3.685 3.465 3.685 3.125 3.63 3.125 3.63 1.43 3.765 1.43 3.765 1.09 3.71 1.09 3.71 0.63 1.58 0.63 1.58 0.805 0.52 0.805 0.52 0.665 0.18 0.665 0.18 4.1 ;
      POLYGON 4.81 3.95 4.81 1.885 4.89 1.885 4.89 1.32 5.69 1.32 5.69 1.555 6.72 1.555 6.72 2.34 6.95 2.34 6.95 1.325 5.92 1.325 5.92 1.09 4.66 1.09 4.66 1.655 4.58 1.655 4.58 3.72 2.965 3.72 2.965 3.18 2.91 3.18 2.91 1.43 3.045 1.43 3.045 1.09 2.68 1.09 2.68 3.18 2.625 3.18 2.625 3.52 2.735 3.52 2.735 3.95 ;
      POLYGON 8.12 3.94 8.12 3.83 8.42 3.83 8.42 1.32 8.94 1.32 8.94 0.86 11.45 0.86 11.45 1.04 13.085 1.04 13.085 0.81 11.68 0.81 11.68 0.63 8.71 0.63 8.71 1.09 8.19 1.09 8.19 3.6 7.78 3.6 7.78 3.94 ;
      POLYGON 8.885 3.885 8.885 1.78 9.4 1.78 9.4 1.32 10.99 1.32 10.99 2.195 10.69 2.195 10.69 3.68 11.915 3.68 11.915 3.45 10.92 3.45 10.92 2.425 11.22 2.425 11.22 1.695 12.16 1.695 12.16 1.355 11.82 1.355 11.82 1.465 11.22 1.465 11.22 1.09 9.17 1.09 9.17 1.55 8.655 1.55 8.655 3.885 ;
      POLYGON 10.46 3.675 10.46 1.78 10.76 1.78 10.76 1.55 10.23 1.55 10.23 3.335 10.04 3.335 10.04 3.675 ;
      POLYGON 7.41 3.62 7.41 1.605 7.5 1.605 7.5 1.265 7.18 1.265 7.18 3.39 5.815 3.39 5.815 2.175 5.585 2.175 5.585 3.62 ;
      POLYGON 4.35 3.465 4.35 1.42 4.43 1.42 4.43 0.86 6.155 0.86 6.155 1.035 7.73 1.035 7.73 2.755 7.64 2.755 7.64 3.13 7.96 3.13 7.96 0.86 8.475 0.86 8.475 0.63 7.73 0.63 7.73 0.805 6.385 0.805 6.385 0.63 4.2 0.63 4.2 1.04 4.12 1.04 4.12 3.465 ;
      POLYGON 0.87 3.3 0.87 3.165 1.715 3.165 1.715 2.715 1.78 2.715 1.78 2.345 1.715 2.345 1.715 1.555 0.87 1.555 0.87 1.31 0.64 1.31 0.64 1.785 1.485 1.785 1.485 2.935 0.64 2.935 0.64 3.3 ;
  END
END ADDFHXL

MACRO AOI222XL
  CLASS CORE ;
  FOREIGN AOI222XL ;
  ORIGIN 0 0 ;
  SIZE 5.28 BY 5.04 ;
  SYMMETRY X Y ;
  SITE unit ;
  PIN A0
    DIRECTION INPUT ;
    USE SIGNAL ;
    PORT
      LAYER METAL1 ;
        RECT 3.475 1.645 3.855 2.195 ;
    END
  END A0
  PIN A1
    DIRECTION INPUT ;
    USE SIGNAL ;
    PORT
      LAYER METAL1 ;
        RECT 4.17 1.845 4.52 2.54 ;
    END
  END A1
  PIN B0
    DIRECTION INPUT ;
    USE SIGNAL ;
    PORT
      LAYER METAL1 ;
        RECT 2.595 1.82 3.145 2.2 ;
    END
  END B0
  PIN B1
    DIRECTION INPUT ;
    USE SIGNAL ;
    PORT
      LAYER METAL1 ;
        RECT 1.525 1.725 2.075 2.1 ;
    END
  END B1
  PIN C0
    DIRECTION INPUT ;
    USE SIGNAL ;
    PORT
      LAYER METAL1 ;
        RECT 0.14 1.82 0.52 2.37 ;
    END
  END C0
  PIN C1
    DIRECTION INPUT ;
    USE SIGNAL ;
    PORT
      LAYER METAL1 ;
        RECT 0.8 2.385 1.27 2.885 ;
    END
  END C1
  PIN Y
    DIRECTION OUTPUT ;
    USE SIGNAL ;
    PORT
      LAYER METAL1 ;
        POLYGON 5.065 3.095 5.065 1.135 0.18 1.135 0.18 1.365 4.835 1.365 4.835 2.635 4.76 2.635 4.76 2.865 3.965 2.865 3.965 3.095 ;
    END
  END Y
  PIN VDD
    DIRECTION INPUT ;
    USE POWER ;
    PORT
      LAYER METAL1 ;
        POLYGON 5.28 5.44 5.28 4.64 1.16 4.64 1.16 4.41 0.82 4.41 0.82 4.64 0 4.64 0 5.44 ;
    END
  END VDD
  PIN VSS
    DIRECTION INPUT ;
    USE GROUND ;
    PORT
      LAYER METAL1 ;
        POLYGON 1.885 0.905 1.885 0.4 4.51 0.4 4.51 0.575 4.85 0.575 4.85 0.4 5.28 0.4 5.28 -0.4 0 -0.4 0 0.4 1.545 0.4 1.545 0.905 ;
    END
  END VSS
  OBS
    LAYER METAL1 ;
      RECT 2.08 4.145 4.865 4.375 ;
      RECT 0.74 3.365 2.98 3.595 ;
  END
END AOI222XL

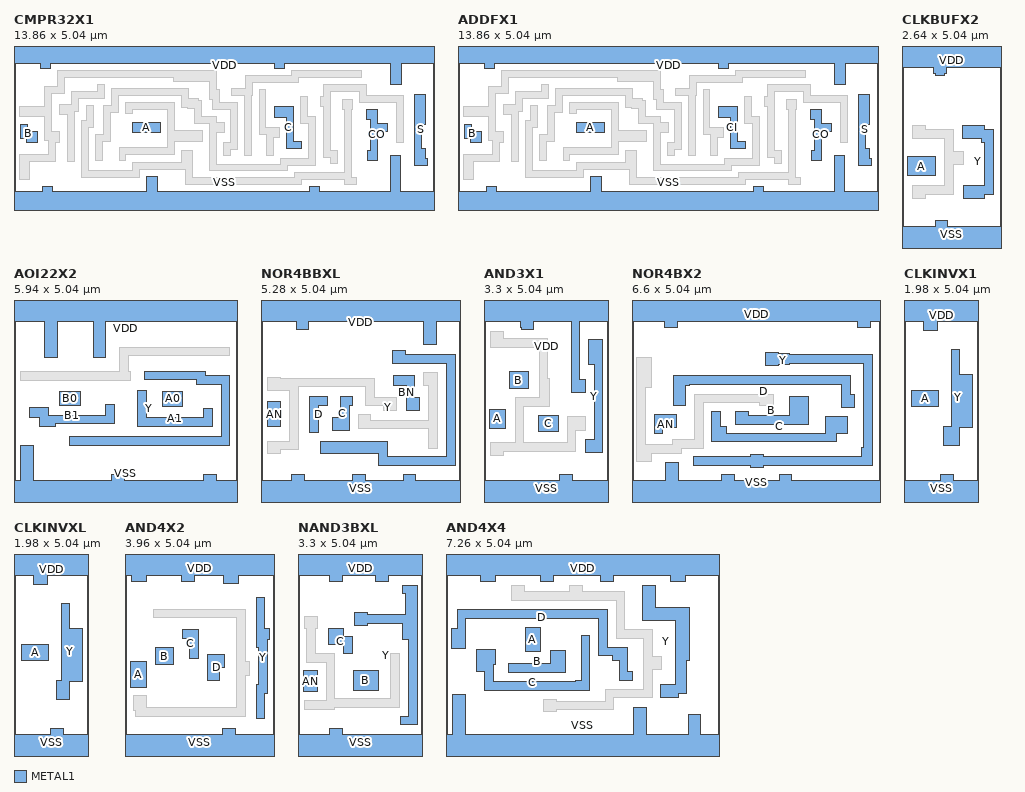
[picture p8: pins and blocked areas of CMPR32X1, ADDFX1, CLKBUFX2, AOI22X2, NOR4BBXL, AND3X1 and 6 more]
MACRO CMPR32X1
  CLASS CORE ;
  FOREIGN CMPR32X1 ;
  ORIGIN 0 0 ;
  SIZE 13.86 BY 5.04 ;
  SYMMETRY X Y ;
  SITE unit ;
  PIN A
    DIRECTION INPUT ;
    USE SIGNAL ;
    PORT
      LAYER METAL1 ;
        RECT 3.895 2.35 4.835 2.69 ;
    END
  END A
  PIN B
    DIRECTION INPUT ;
    USE SIGNAL ;
    PORT
      LAYER METAL1 ;
        POLYGON 0.445 2.635 0.445 2.38 0.76 2.38 0.76 2.04 0.42 2.04 0.42 2.15 0.215 2.15 0.215 2.635 ;
    END
  END B
  PIN C
    DIRECTION INPUT ;
    USE SIGNAL ;
    PORT
      LAYER METAL1 ;
        POLYGON 9.22 3.22 9.22 2.05 9.485 2.05 9.485 1.82 8.99 1.82 8.99 2.865 8.6 2.865 8.6 3.22 ;
    END
  END C
  PIN CO
    DIRECTION OUTPUT ;
    USE SIGNAL ;
    PORT
      LAYER METAL1 ;
        POLYGON 11.985 3.135 11.985 2.66 12.325 2.66 12.325 2.38 12.005 2.38 12.005 1.43 11.665 1.43 11.665 1.77 11.755 1.77 11.755 2.795 11.645 2.795 11.645 3.135 ;
    END
  END CO
  PIN S
    DIRECTION OUTPUT ;
    USE SIGNAL ;
    PORT
      LAYER METAL1 ;
        POLYGON 13.57 3.605 13.57 2.635 13.46 2.635 13.46 1.845 13.57 1.845 13.57 1.515 13.645 1.515 13.645 1.285 13.23 1.285 13.23 3.605 ;
    END
  END S
  PIN VDD
    DIRECTION INPUT ;
    USE POWER ;
    PORT
      LAYER METAL1 ;
        POLYGON 13.86 5.44 13.86 4.64 12.775 4.64 12.775 3.93 12.435 3.93 12.435 4.64 8.935 4.64 8.935 4.465 8.595 4.465 8.595 4.64 1.2 4.64 1.2 4.465 0.86 4.465 0.86 4.64 0 4.64 0 5.44 ;
    END
  END VDD
  PIN VSS
    DIRECTION INPUT ;
    USE GROUND ;
    PORT
      LAYER METAL1 ;
        POLYGON 12.77 1.615 12.77 0.4 13.86 0.4 13.86 -0.4 0 -0.4 0 0.4 0.945 0.4 0.945 0.575 1.285 0.575 1.285 0.4 4.385 0.4 4.385 0.9 4.725 0.9 4.725 0.4 9.74 0.4 9.74 0.575 10.08 0.575 10.08 0.4 12.43 0.4 12.43 1.615 ;
    END
  END VSS
  OBS
    LAYER METAL1 ;
      POLYGON 11.455 4.41 11.455 4.18 9.395 4.18 9.395 4.005 7.855 4.005 7.855 3.58 7.85 3.58 7.85 1.585 7.62 1.585 7.62 3.58 7.175 3.58 7.175 3.81 7.625 3.81 7.625 4.235 9.165 4.235 9.165 4.41 ;
      POLYGON 6.685 4.41 6.685 3.78 6.795 3.78 6.795 3.35 7.39 3.35 7.39 1.79 7.13 1.79 7.13 1.585 6.9 1.585 6.9 2.02 7.16 2.02 7.16 3.12 6.565 3.12 6.565 3.44 6.455 3.44 6.455 4.055 5.255 4.055 5.255 4.18 1.66 4.18 1.66 3.655 1.235 3.655 1.235 2.38 1.49 2.38 1.49 2.04 1.38 2.04 1.38 1.395 0.52 1.395 0.52 0.815 0.18 0.815 0.18 1.625 1.15 1.625 1.15 2.095 1.005 2.095 1.005 2.89 0.18 2.89 0.18 3.23 1.005 3.23 1.005 3.885 1.43 3.885 1.43 4.41 ;
      POLYGON 2.98 3.95 2.98 3.495 2.125 3.495 2.125 3.05 1.99 3.05 1.99 1.395 1.76 1.395 1.76 2.94 1.505 2.94 1.505 3.28 1.895 3.28 1.895 3.725 2.75 3.725 2.75 3.95 ;
      POLYGON 11.645 3.945 11.645 3.595 12.865 3.595 12.865 2.015 12.635 2.015 12.635 3.365 11.415 3.365 11.415 3.715 10.455 3.715 10.455 1.77 10.68 1.77 10.68 1.345 10.45 1.345 10.45 1.54 10.225 1.54 10.225 3.215 10.115 3.215 10.115 3.555 10.225 3.555 10.225 3.945 ;
      POLYGON 5.765 3.825 5.765 3.48 6.075 3.48 6.075 3.425 6.175 3.425 6.175 2.89 6.67 2.89 6.67 2.7 6.93 2.7 6.93 2.36 6.67 2.36 6.67 1.32 8.805 1.32 8.805 1.5 9.73 1.5 9.73 2.645 9.45 2.645 9.45 3.555 9.68 3.555 9.68 2.875 9.96 2.875 9.96 1.27 9.035 1.27 9.035 1.09 6.44 1.09 6.44 2.655 5.945 2.655 5.945 3.14 5.735 3.14 5.735 3.195 5.535 3.195 5.535 3.595 3.44 3.595 3.44 3.03 3.18 3.03 3.18 2.075 2.91 2.075 2.91 1.42 2.68 1.42 2.68 2.305 2.95 2.305 2.95 3.26 3.21 3.26 3.21 3.825 ;
      POLYGON 8.315 3.77 8.315 2.535 8.76 2.535 8.76 2.195 8.57 2.195 8.57 1.585 8.34 1.585 8.34 2.305 8.085 2.305 8.085 3.77 ;
      POLYGON 11.175 3.46 11.175 3.12 11.14 3.12 11.14 0.86 11.295 0.86 11.295 0.63 10.9 0.63 10.9 0.81 9.495 0.81 9.495 0.63 5.65 0.63 5.65 1.135 4.155 1.135 4.155 0.875 2.22 0.875 2.22 2.765 2.39 2.765 2.39 3.265 2.62 3.265 2.62 2.535 2.45 2.535 2.45 1.105 3.925 1.105 3.925 1.365 5.54 1.365 5.54 1.75 5.88 1.75 5.88 0.86 9.265 0.86 9.265 1.04 10.91 1.04 10.91 3.12 10.835 3.12 10.835 3.46 ;
      POLYGON 5.3 3.365 5.3 2.42 6.21 2.42 6.21 2.07 5.3 2.07 5.3 1.635 3.695 1.635 3.695 1.44 3.465 1.44 3.465 1.865 5.07 1.865 5.07 3.135 3.9 3.135 3.9 2.98 3.67 2.98 3.67 3.365 ;
  END
END CMPR32X1

MACRO ADDFX1
  CLASS CORE ;
  FOREIGN ADDFX1 ;
  ORIGIN 0 0 ;
  SIZE 13.86 BY 5.04 ;
  SYMMETRY X Y ;
  SITE unit ;
  PIN A
    DIRECTION INPUT ;
    USE SIGNAL ;
    PORT
      LAYER METAL1 ;
        RECT 3.895 2.35 4.835 2.69 ;
    END
  END A
  PIN B
    DIRECTION INPUT ;
    USE SIGNAL ;
    PORT
      LAYER METAL1 ;
        POLYGON 0.445 2.635 0.445 2.38 0.76 2.38 0.76 2.04 0.42 2.04 0.42 2.15 0.215 2.15 0.215 2.635 ;
    END
  END B
  PIN CI
    DIRECTION INPUT ;
    USE SIGNAL ;
    PORT
      LAYER METAL1 ;
        POLYGON 9.22 3.22 9.22 2.05 9.485 2.05 9.485 1.82 8.99 1.82 8.99 2.865 8.6 2.865 8.6 3.22 ;
    END
  END CI
  PIN CO
    DIRECTION OUTPUT ;
    USE SIGNAL ;
    PORT
      LAYER METAL1 ;
        POLYGON 11.985 3.135 11.985 2.66 12.325 2.66 12.325 2.38 12.005 2.38 12.005 1.43 11.665 1.43 11.665 1.77 11.755 1.77 11.755 2.795 11.645 2.795 11.645 3.135 ;
    END
  END CO
  PIN S
    DIRECTION OUTPUT ;
    USE SIGNAL ;
    PORT
      LAYER METAL1 ;
        POLYGON 13.57 3.605 13.57 2.635 13.46 2.635 13.46 1.845 13.57 1.845 13.57 1.515 13.645 1.515 13.645 1.285 13.23 1.285 13.23 3.605 ;
    END
  END S
  PIN VDD
    DIRECTION INPUT ;
    USE POWER ;
    PORT
      LAYER METAL1 ;
        POLYGON 13.86 5.44 13.86 4.64 12.775 4.64 12.775 3.93 12.435 3.93 12.435 4.64 8.935 4.64 8.935 4.465 8.595 4.465 8.595 4.64 1.2 4.64 1.2 4.465 0.86 4.465 0.86 4.64 0 4.64 0 5.44 ;
    END
  END VDD
  PIN VSS
    DIRECTION INPUT ;
    USE GROUND ;
    PORT
      LAYER METAL1 ;
        POLYGON 12.77 1.615 12.77 0.4 13.86 0.4 13.86 -0.4 0 -0.4 0 0.4 0.945 0.4 0.945 0.575 1.285 0.575 1.285 0.4 4.385 0.4 4.385 0.9 4.725 0.9 4.725 0.4 9.74 0.4 9.74 0.575 10.08 0.575 10.08 0.4 12.43 0.4 12.43 1.615 ;
    END
  END VSS
  OBS
    LAYER METAL1 ;
      POLYGON 11.455 4.41 11.455 4.18 9.395 4.18 9.395 4.005 7.855 4.005 7.855 3.58 7.85 3.58 7.85 1.585 7.62 1.585 7.62 3.58 7.175 3.58 7.175 3.81 7.625 3.81 7.625 4.235 9.165 4.235 9.165 4.41 ;
      POLYGON 6.685 4.41 6.685 3.78 6.795 3.78 6.795 3.35 7.39 3.35 7.39 1.79 7.13 1.79 7.13 1.585 6.9 1.585 6.9 2.02 7.16 2.02 7.16 3.12 6.565 3.12 6.565 3.44 6.455 3.44 6.455 4.055 5.255 4.055 5.255 4.18 1.66 4.18 1.66 3.655 1.235 3.655 1.235 2.38 1.49 2.38 1.49 2.04 1.38 2.04 1.38 1.395 0.52 1.395 0.52 0.815 0.18 0.815 0.18 1.625 1.15 1.625 1.15 2.095 1.005 2.095 1.005 2.89 0.18 2.89 0.18 3.23 1.005 3.23 1.005 3.885 1.43 3.885 1.43 4.41 ;
      POLYGON 2.98 3.95 2.98 3.495 2.125 3.495 2.125 3.05 1.99 3.05 1.99 1.395 1.76 1.395 1.76 2.94 1.505 2.94 1.505 3.28 1.895 3.28 1.895 3.725 2.75 3.725 2.75 3.95 ;
      POLYGON 11.645 3.945 11.645 3.595 12.865 3.595 12.865 2.015 12.635 2.015 12.635 3.365 11.415 3.365 11.415 3.715 10.455 3.715 10.455 1.77 10.68 1.77 10.68 1.345 10.45 1.345 10.45 1.54 10.225 1.54 10.225 3.215 10.115 3.215 10.115 3.555 10.225 3.555 10.225 3.945 ;
      POLYGON 5.765 3.825 5.765 3.48 6.075 3.48 6.075 3.425 6.175 3.425 6.175 2.89 6.67 2.89 6.67 2.7 6.93 2.7 6.93 2.36 6.67 2.36 6.67 1.32 8.805 1.32 8.805 1.5 9.73 1.5 9.73 2.645 9.45 2.645 9.45 3.555 9.68 3.555 9.68 2.875 9.96 2.875 9.96 1.27 9.035 1.27 9.035 1.09 6.44 1.09 6.44 2.655 5.945 2.655 5.945 3.14 5.735 3.14 5.735 3.195 5.535 3.195 5.535 3.595 3.44 3.595 3.44 3.03 3.18 3.03 3.18 2.075 2.91 2.075 2.91 1.42 2.68 1.42 2.68 2.305 2.95 2.305 2.95 3.26 3.21 3.26 3.21 3.825 ;
      POLYGON 8.315 3.77 8.315 2.535 8.76 2.535 8.76 2.195 8.57 2.195 8.57 1.585 8.34 1.585 8.34 2.305 8.085 2.305 8.085 3.77 ;
      POLYGON 11.175 3.46 11.175 3.12 11.14 3.12 11.14 0.86 11.295 0.86 11.295 0.63 10.9 0.63 10.9 0.81 9.495 0.81 9.495 0.63 5.65 0.63 5.65 1.135 4.155 1.135 4.155 0.875 2.22 0.875 2.22 2.765 2.39 2.765 2.39 3.265 2.62 3.265 2.62 2.535 2.45 2.535 2.45 1.105 3.925 1.105 3.925 1.365 5.54 1.365 5.54 1.75 5.88 1.75 5.88 0.86 9.265 0.86 9.265 1.04 10.91 1.04 10.91 3.12 10.835 3.12 10.835 3.46 ;
      POLYGON 5.3 3.365 5.3 2.42 6.21 2.42 6.21 2.07 5.3 2.07 5.3 1.635 3.695 1.635 3.695 1.44 3.465 1.44 3.465 1.865 5.07 1.865 5.07 3.135 3.9 3.135 3.9 2.98 3.67 2.98 3.67 3.365 ;
  END
END ADDFX1

MACRO CLKBUFX2
  CLASS CORE ;
  FOREIGN CLKBUFX2 ;
  ORIGIN 0 0 ;
  SIZE 2.64 BY 5.04 ;
  SYMMETRY X Y ;
  SITE unit ;
  PIN A
    DIRECTION INPUT ;
    USE SIGNAL ;
    PORT
      LAYER METAL1 ;
        RECT 0.14 1.755 0.9 2.26 ;
    END
  END A
  PIN Y
    DIRECTION OUTPUT ;
    USE SIGNAL ;
    PORT
      LAYER METAL1 ;
        POLYGON 2.195 3.09 2.195 2.98 2.425 2.98 2.425 1.265 2.2 1.265 2.2 1.155 1.64 1.155 1.64 1.495 2.195 1.495 2.195 2.635 2.12 2.635 2.12 2.75 1.6 2.75 1.6 3.09 ;
    END
  END Y
  PIN VDD
    DIRECTION INPUT ;
    USE POWER ;
    PORT
      LAYER METAL1 ;
        POLYGON 2.64 5.44 2.64 4.64 1.18 4.64 1.18 4.465 1.125 4.465 1.125 4.41 0.895 4.41 0.895 4.465 0.84 4.465 0.84 4.64 0 4.64 0 5.44 ;
    END
  END VDD
  PIN VSS
    DIRECTION INPUT ;
    USE GROUND ;
    PORT
      LAYER METAL1 ;
        POLYGON 1.22 0.575 1.22 0.4 2.64 0.4 2.64 -0.4 0 -0.4 0 0.4 0.88 0.4 0.88 0.575 ;
    END
  END VSS
  OBS
    LAYER METAL1 ;
      POLYGON 0.62 3.09 0.62 2.98 1.37 2.98 1.37 2.4 1.62 2.4 1.62 2.06 1.37 2.06 1.37 1.265 0.62 1.265 0.62 1.155 0.28 1.155 0.28 1.495 1.14 1.495 1.14 2.75 0.28 2.75 0.28 3.09 ;
  END
END CLKBUFX2

MACRO AOI22X2
  CLASS CORE ;
  FOREIGN AOI22X2 ;
  ORIGIN 0 0 ;
  SIZE 5.94 BY 5.04 ;
  SYMMETRY X Y ;
  SITE unit ;
  PIN A0
    DIRECTION INPUT ;
    USE SIGNAL ;
    PORT
      LAYER METAL1 ;
        RECT 3.94 2.38 4.48 2.775 ;
    END
  END A0
  PIN A1
    DIRECTION INPUT ;
    USE SIGNAL ;
    PORT
      LAYER METAL1 ;
        POLYGON 3.505 2.79 3.505 2.075 3.745 2.075 3.745 2.07 5.035 2.07 5.035 2.315 5.265 2.315 5.265 1.84 3.275 1.84 3.275 2.79 ;
    END
  END A1
  PIN B0
    DIRECTION INPUT ;
    USE SIGNAL ;
    PORT
      LAYER METAL1 ;
        RECT 1.22 2.405 1.765 2.785 ;
    END
  END B0
  PIN B1
    DIRECTION INPUT ;
    USE SIGNAL ;
    PORT
      LAYER METAL1 ;
        POLYGON 2.655 2.415 2.655 1.915 1.105 1.915 1.105 1.845 0.685 1.845 0.685 2.07 0.42 2.07 0.42 2.36 0.915 2.36 0.915 2.145 2.425 2.145 2.425 2.415 ;
    END
  END B1
  PIN Y
    DIRECTION OUTPUT ;
    USE SIGNAL ;
    PORT
      LAYER METAL1 ;
        POLYGON 5.08 3.315 5.08 3.195 5.725 3.195 5.725 1.35 1.46 1.35 1.46 1.58 5.495 1.58 5.495 2.965 4.835 2.965 4.835 3.085 3.46 3.085 3.46 3.315 ;
    END
  END Y
  PIN VDD
    DIRECTION INPUT ;
    USE POWER ;
    PORT
      LAYER METAL1 ;
        POLYGON 5.94 5.44 5.94 4.64 2.44 4.64 2.44 3.665 2.1 3.665 2.1 4.64 1.16 4.64 1.16 3.665 0.82 3.665 0.82 4.64 0 4.64 0 5.44 ;
    END
  END VDD
  PIN VSS
    DIRECTION INPUT ;
    USE GROUND ;
    PORT
      LAYER METAL1 ;
        POLYGON 0.52 1.345 0.52 0.4 2.58 0.4 2.58 0.575 2.92 0.575 2.92 0.4 5.02 0.4 5.02 0.575 5.36 0.575 5.36 0.4 5.94 0.4 5.94 -0.4 0 -0.4 0 0.4 0.18 0.4 0.18 1.345 ;
    END
  END VSS
  OBS
    LAYER METAL1 ;
      POLYGON 5.72 3.95 5.72 3.72 3.025 3.72 3.025 3.305 3.08 3.305 3.08 3.075 0.18 3.075 0.18 3.305 2.795 3.305 2.795 3.95 ;
  END
END AOI22X2

MACRO NOR4BBXL
  CLASS CORE ;
  FOREIGN NOR4BBXL ;
  ORIGIN 0 0 ;
  SIZE 5.28 BY 5.04 ;
  SYMMETRY X Y ;
  SITE unit ;
  PIN AN
    DIRECTION INPUT ;
    USE SIGNAL ;
    PORT
      LAYER METAL1 ;
        RECT 0.175 1.84 0.515 2.5 ;
    END
  END AN
  PIN BN
    DIRECTION INPUT ;
    USE SIGNAL ;
    PORT
      LAYER METAL1 ;
        POLYGON 4.085 3.195 4.085 2.615 4.205 2.615 4.205 2.275 3.855 2.275 3.855 2.94 3.515 2.94 3.515 3.195 ;
    END
  END BN
  PIN C
    DIRECTION INPUT ;
    USE SIGNAL ;
    PORT
      LAYER METAL1 ;
        POLYGON 2.425 2.635 2.425 2.405 2.34 2.405 2.34 1.73 1.905 1.73 1.905 2.07 2.11 2.07 2.11 2.635 ;
    END
  END C
  PIN D
    DIRECTION INPUT ;
    USE SIGNAL ;
    PORT
      LAYER METAL1 ;
        POLYGON 1.765 2.635 1.765 2.405 1.52 2.405 1.52 1.69 1.29 1.69 1.29 2.635 ;
    END
  END D
  PIN Y
    DIRECTION OUTPUT ;
    USE SIGNAL ;
    PORT
      LAYER METAL1 ;
        POLYGON 3.825 3.865 3.825 3.755 5.16 3.755 5.16 0.805 3.125 0.805 3.125 1.115 1.575 1.115 1.575 1.455 3.35 1.455 3.35 1.4 3.355 1.4 3.355 1.035 4.93 1.035 4.93 3.525 3.485 3.525 3.485 3.865 ;
    END
  END Y
  PIN VDD
    DIRECTION INPUT ;
    USE POWER ;
    PORT
      LAYER METAL1 ;
        POLYGON 5.28 5.44 5.28 4.64 4.655 4.64 4.655 4.015 4.315 4.015 4.315 4.64 1.27 4.64 1.27 4.41 0.93 4.41 0.93 4.64 0 4.64 0 5.44 ;
    END
  END VDD
  PIN VSS
    DIRECTION INPUT ;
    USE GROUND ;
    PORT
      LAYER METAL1 ;
        POLYGON 4.11 0.575 4.11 0.4 5.28 0.4 5.28 -0.4 0 -0.4 0 0.4 0.815 0.4 0.815 0.575 1.155 0.575 1.155 0.4 2.43 0.4 2.43 0.575 2.77 0.575 2.77 0.4 3.77 0.4 3.77 0.575 ;
    END
  END VSS
  OBS
    LAYER METAL1 ;
      POLYGON 4.685 3.27 4.685 1.265 4.455 1.265 4.455 1.78 2.575 1.78 2.575 2.16 2.915 2.16 2.915 2.01 4.455 2.01 4.455 2.93 4.315 2.93 4.315 3.27 ;
      POLYGON 0.52 3.145 0.52 3.125 3.005 3.125 3.005 2.62 3.585 2.62 3.585 2.275 3.245 2.275 3.245 2.39 2.775 2.39 2.775 2.895 0.99 2.895 0.99 1.225 0.52 1.225 0.52 1.115 0.18 1.115 0.18 1.455 0.76 1.455 0.76 2.805 0.18 2.805 0.18 3.145 ;
  END
END NOR4BBXL

MACRO AND3X1
  CLASS CORE ;
  FOREIGN AND3X1 ;
  ORIGIN 0 0 ;
  SIZE 3.3 BY 5.04 ;
  SYMMETRY X Y ;
  SITE unit ;
  PIN A
    DIRECTION INPUT ;
    USE SIGNAL ;
    PORT
      LAYER METAL1 ;
        RECT 0.14 1.79 0.58 2.3 ;
    END
  END A
  PIN B
    DIRECTION INPUT ;
    USE SIGNAL ;
    PORT
      LAYER METAL1 ;
        RECT 0.675 2.845 1.18 3.3 ;
    END
  END B
  PIN C
    DIRECTION INPUT ;
    USE SIGNAL ;
    PORT
      LAYER METAL1 ;
        RECT 1.455 1.715 1.975 2.145 ;
    END
  END C
  PIN Y
    DIRECTION OUTPUT ;
    USE SIGNAL ;
    PORT
      LAYER METAL1 ;
        POLYGON 3.15 4.155 3.15 1.15 2.69 1.15 2.69 1.49 2.92 1.49 2.92 3.48 2.78 3.48 2.78 4.155 ;
    END
  END Y
  PIN VDD
    DIRECTION INPUT ;
    USE POWER ;
    PORT
      LAYER METAL1 ;
        POLYGON 3.3 5.44 3.3 4.64 2.545 4.64 2.545 3.095 2.69 3.095 2.69 2.755 2.315 2.755 2.315 4.64 1.32 4.64 1.32 4.465 1.315 4.465 1.315 4.41 0.99 4.41 0.99 4.465 0.98 4.465 0.98 4.64 0 4.64 0 5.44 ;
    END
  END VDD
  PIN VSS
    DIRECTION INPUT ;
    USE GROUND ;
    PORT
      LAYER METAL1 ;
        POLYGON 2.34 0.575 2.34 0.4 3.3 0.4 3.3 -0.4 0 -0.4 0 0.4 2 0.4 2 0.575 ;
    END
  END VSS
  OBS
    LAYER METAL1 ;
      POLYGON 0.52 4.36 0.52 4.18 1.695 4.18 1.695 3.125 1.75 3.125 1.75 2.38 1.055 2.38 1.055 1.42 2.205 1.42 2.205 2.115 2.69 2.115 2.69 1.75 2.435 1.75 2.435 1.19 0.52 1.19 0.52 1.08 0.18 1.08 0.18 1.42 0.825 1.42 0.825 2.61 1.465 2.61 1.465 3.95 0.18 3.95 0.18 4.36 ;
  END
END AND3X1

MACRO NOR4BX2
  CLASS CORE ;
  FOREIGN NOR4BX2 ;
  ORIGIN 0 0 ;
  SIZE 6.6 BY 5.04 ;
  SYMMETRY X Y ;
  SITE unit ;
  PIN AN
    DIRECTION INPUT ;
    USE SIGNAL ;
    PORT
      LAYER METAL1 ;
        POLYGON 1.18 2.155 1.18 1.82 0.815 1.82 0.815 1.66 0.585 1.66 0.585 2.155 ;
    END
  END AN
  PIN B
    DIRECTION INPUT ;
    USE SIGNAL ;
    PORT
      LAYER METAL1 ;
        POLYGON 4.68 2.635 4.68 1.9 2.74 1.9 2.74 2.24 3.08 2.24 3.08 2.13 4.175 2.13 4.175 2.635 ;
    END
  END B
  PIN C
    DIRECTION INPUT ;
    USE SIGNAL ;
    PORT
      LAYER METAL1 ;
        POLYGON 2.35 2.24 2.35 1.845 2.5 1.845 2.5 1.67 5.135 1.67 5.135 2.1 5.725 2.1 5.725 1.665 5.425 1.665 5.425 1.44 2.12 1.44 2.12 2.24 ;
    END
  END C
  PIN D
    DIRECTION INPUT ;
    USE SIGNAL ;
    PORT
      LAYER METAL1 ;
        POLYGON 5.795 3.195 5.795 2.68 5.91 2.68 5.91 2.34 5.57 2.34 5.57 2.395 5.565 2.395 5.565 2.965 1.535 2.965 1.535 2.94 1.43 2.94 1.43 2.39 1.09 2.39 1.09 3.195 ;
    END
  END D
  PIN Y
    DIRECTION OUTPUT ;
    USE SIGNAL ;
    PORT
      LAYER METAL1 ;
        POLYGON 3.88 3.81 3.88 3.78 4.18 3.78 4.18 3.755 6.37 3.755 6.37 0.805 3.48 0.805 3.48 0.75 3.14 0.75 3.14 0.805 1.62 0.805 1.62 1.035 3.14 1.035 3.14 1.09 3.48 1.09 3.48 1.035 6.08 1.035 6.08 1.285 6.14 1.285 6.14 3.525 4.18 3.525 4.18 3.5 3.88 3.5 3.88 3.47 3.54 3.47 3.54 3.81 ;
    END
  END Y
  PIN VDD
    DIRECTION INPUT ;
    USE POWER ;
    PORT
      LAYER METAL1 ;
        POLYGON 6.6 5.44 6.6 4.64 6.32 4.64 6.32 4.465 5.98 4.465 5.98 4.64 1.2 4.64 1.2 4.465 0.86 4.465 0.86 4.64 0 4.64 0 5.44 ;
    END
  END VDD
  PIN VSS
    DIRECTION INPUT ;
    USE GROUND ;
    PORT
      LAYER METAL1 ;
        POLYGON 1.24 0.895 1.24 0.4 2.38 0.4 2.38 0.575 2.72 0.575 2.72 0.4 3.9 0.4 3.9 0.575 4.24 0.575 4.24 0.4 6.6 0.4 6.6 -0.4 0 -0.4 0 0.4 0.9 0.4 0.9 0.895 ;
    END
  END VSS
  OBS
    LAYER METAL1 ;
      POLYGON 0.52 3.68 0.52 2.87 0.355 2.87 0.355 1.355 1.085 1.355 1.085 1.495 1.66 1.495 1.66 2.7 3.75 2.7 3.75 2.395 3.395 2.395 3.395 2.47 1.89 2.47 1.89 1.265 1.315 1.265 1.315 1.125 0.52 1.125 0.52 0.91 0.125 0.91 0.125 3.68 ;
  END
END NOR4BX2

MACRO CLKINVX1
  CLASS CORE ;
  FOREIGN CLKINVX1 ;
  ORIGIN 0 0 ;
  SIZE 1.98 BY 5.04 ;
  SYMMETRY X Y ;
  SITE unit ;
  PIN A
    DIRECTION INPUT ;
    USE SIGNAL ;
    PORT
      LAYER METAL1 ;
        RECT 0.19 2.38 0.925 2.81 ;
    END
  END A
  PIN Y
    DIRECTION OUTPUT ;
    USE SIGNAL ;
    PORT
      LAYER METAL1 ;
        POLYGON 1.485 3.885 1.485 3.22 1.83 3.22 1.83 1.82 1.485 1.82 1.485 1.35 1.04 1.35 1.04 1.855 1.255 1.855 1.255 3.885 ;
    END
  END Y
  PIN VDD
    DIRECTION INPUT ;
    USE POWER ;
    PORT
      LAYER METAL1 ;
        POLYGON 1.98 5.44 1.98 4.64 0.89 4.64 0.89 4.395 0.525 4.395 0.525 4.64 0 4.64 0 5.44 ;
    END
  END VDD
  PIN VSS
    DIRECTION INPUT ;
    USE GROUND ;
    PORT
      LAYER METAL1 ;
        POLYGON 1.32 0.575 1.32 0.4 1.98 0.4 1.98 -0.4 0 -0.4 0 0.4 0.98 0.4 0.98 0.575 ;
    END
  END VSS
END CLKINVX1

MACRO CLKINVXL
  CLASS CORE ;
  FOREIGN CLKINVXL ;
  ORIGIN 0 0 ;
  SIZE 1.98 BY 5.04 ;
  SYMMETRY X Y ;
  SITE unit ;
  PIN A
    DIRECTION INPUT ;
    USE SIGNAL ;
    PORT
      LAYER METAL1 ;
        RECT 0.19 2.38 0.925 2.81 ;
    END
  END A
  PIN Y
    DIRECTION OUTPUT ;
    USE SIGNAL ;
    PORT
      LAYER METAL1 ;
        POLYGON 1.485 3.885 1.485 3.22 1.83 3.22 1.83 1.82 1.485 1.82 1.485 1.35 1.12 1.35 1.12 1.85 1.255 1.85 1.255 3.885 ;
    END
  END Y
  PIN VDD
    DIRECTION INPUT ;
    USE POWER ;
    PORT
      LAYER METAL1 ;
        POLYGON 1.98 5.44 1.98 4.64 0.89 4.64 0.89 4.395 0.525 4.395 0.525 4.64 0 4.64 0 5.44 ;
    END
  END VDD
  PIN VSS
    DIRECTION INPUT ;
    USE GROUND ;
    PORT
      LAYER METAL1 ;
        POLYGON 1.32 0.575 1.32 0.4 1.98 0.4 1.98 -0.4 0 -0.4 0 0.4 0.98 0.4 0.98 0.575 ;
    END
  END VSS
END CLKINVXL

MACRO AND4X2
  CLASS CORE ;
  FOREIGN AND4X2 ;
  ORIGIN 0 0 ;
  SIZE 3.96 BY 5.04 ;
  SYMMETRY X Y ;
  SITE unit ;
  PIN A
    DIRECTION INPUT ;
    USE SIGNAL ;
    PORT
      LAYER METAL1 ;
        RECT 0.14 1.67 0.565 2.335 ;
    END
  END A
  PIN B
    DIRECTION INPUT ;
    USE SIGNAL ;
    PORT
      LAYER METAL1 ;
        POLYGON 1.29 2.715 1.29 2.255 0.8 2.255 0.8 2.71 1.005 2.71 1.005 2.715 ;
    END
  END B
  PIN C
    DIRECTION INPUT ;
    USE SIGNAL ;
    PORT
      LAYER METAL1 ;
        POLYGON 1.95 3.195 1.95 2.44 1.72 2.44 1.72 2.965 1.535 2.965 1.535 3.195 ;
    END
  END C
  PIN D
    DIRECTION INPUT ;
    USE SIGNAL ;
    PORT
      LAYER METAL1 ;
        POLYGON 2.64 2.545 2.64 2.2 2.5 2.2 2.5 1.845 2.195 1.845 2.195 2.545 ;
    END
  END D
  PIN Y
    DIRECTION OUTPUT ;
    USE SIGNAL ;
    PORT
      LAYER METAL1 ;
        POLYGON 3.71 4.05 3.71 3.22 3.82 3.22 3.82 2.94 3.775 2.94 3.775 1.505 3.71 1.505 3.71 0.835 3.48 0.835 3.48 1.735 3.545 1.735 3.545 2.72 3.48 2.72 3.48 4.05 ;
    END
  END Y
  PIN VDD
    DIRECTION INPUT ;
    USE POWER ;
    PORT
      LAYER METAL1 ;
        POLYGON 3.96 5.44 3.96 4.64 3.015 4.64 3.015 4.405 2.605 4.405 2.605 4.64 1.85 4.64 1.85 4.465 1.51 4.465 1.51 4.64 0.57 4.64 0.57 4.465 0.175 4.465 0.175 4.64 0 4.64 0 5.44 ;
    END
  END VDD
  PIN VSS
    DIRECTION INPUT ;
    USE GROUND ;
    PORT
      LAYER METAL1 ;
        POLYGON 2.935 0.575 2.935 0.4 3.96 0.4 3.96 -0.4 0 -0.4 0 0.4 2.595 0.4 2.595 0.575 ;
    END
  END VSS
  OBS
    LAYER METAL1 ;
      POLYGON 3.2 3.735 3.2 2.335 3.31 2.335 3.31 1.985 3.2 1.985 3.2 0.885 0.275 0.885 0.275 1.05 0.22 1.05 0.22 1.44 0.56 1.44 0.56 1.115 2.97 1.115 2.97 3.505 0.75 3.505 0.75 3.735 ;
  END
END AND4X2

MACRO NAND3BXL
  CLASS CORE ;
  FOREIGN NAND3BXL ;
  ORIGIN 0 0 ;
  SIZE 3.3 BY 5.04 ;
  SYMMETRY X Y ;
  SITE unit ;
  PIN AN
    DIRECTION INPUT ;
    USE SIGNAL ;
    PORT
      LAYER METAL1 ;
        RECT 0.14 1.54 0.52 2.1 ;
    END
  END AN
  PIN B
    DIRECTION INPUT ;
    USE SIGNAL ;
    PORT
      LAYER METAL1 ;
        RECT 1.46 1.59 2.13 2.1 ;
    END
  END B
  PIN C
    DIRECTION INPUT ;
    USE SIGNAL ;
    PORT
      LAYER METAL1 ;
        POLYGON 1.215 3.22 1.215 3.02 1.44 3.02 1.44 2.55 1.21 2.55 1.21 2.79 0.8 2.79 0.8 3.22 ;
    END
  END C
  PIN Y
    DIRECTION OUTPUT ;
    USE SIGNAL ;
    PORT
      LAYER METAL1 ;
        POLYGON 3.16 4.375 3.16 0.665 2.72 0.665 2.72 0.895 2.93 0.895 2.93 2.94 2.78 2.94 2.78 3.355 1.84 3.355 1.84 3.3 1.5 3.3 1.5 3.64 1.84 3.64 1.84 3.585 2.855 3.585 2.855 4.145 2.76 4.145 2.76 4.375 ;
    END
  END Y
  PIN VDD
    DIRECTION INPUT ;
    USE POWER ;
    PORT
      LAYER METAL1 ;
        POLYGON 3.3 5.44 3.3 4.64 2.4 4.64 2.4 4.465 2.06 4.465 2.06 4.64 1.18 4.64 1.18 4.465 0.84 4.465 0.84 4.64 0 4.64 0 5.44 ;
    END
  END VDD
  PIN VSS
    DIRECTION INPUT ;
    USE GROUND ;
    PORT
      LAYER METAL1 ;
        POLYGON 1.18 0.575 1.18 0.4 3.3 0.4 3.3 -0.4 0 -0.4 0 0.4 0.84 0.4 0.84 0.575 ;
    END
  END VSS
  OBS
    LAYER METAL1 ;
      POLYGON 0.52 3.55 0.52 3.21 0.465 3.21 0.465 2.56 0.98 2.56 0.98 1.355 2.465 1.355 2.465 2.55 2.695 2.55 2.695 1.125 0.98 1.125 0.98 1.08 0.18 1.08 0.18 1.31 0.75 1.31 0.75 2.33 0.235 2.33 0.235 3.21 0.18 3.21 0.18 3.55 ;
  END
END NAND3BXL

MACRO AND4X4
  CLASS CORE ;
  FOREIGN AND4X4 ;
  ORIGIN 0 0 ;
  SIZE 7.26 BY 5.04 ;
  SYMMETRY X Y ;
  SITE unit ;
  PIN A
    DIRECTION INPUT ;
    USE SIGNAL ;
    PORT
      LAYER METAL1 ;
        RECT 2.1 2.625 2.5 3.245 ;
    END
  END A
  PIN B
    DIRECTION INPUT ;
    USE SIGNAL ;
    PORT
      LAYER METAL1 ;
        POLYGON 3.16 2.64 3.16 2.055 1.67 2.055 1.67 2.285 2.78 2.285 2.78 2.64 ;
    END
  END B
  PIN C
    DIRECTION INPUT ;
    USE SIGNAL ;
    PORT
      LAYER METAL1 ;
        POLYGON 3.815 3.03 3.815 1.59 1.02 1.59 1.02 2.07 0.8 2.07 0.8 2.67 1.32 2.67 1.32 2.265 1.25 2.265 1.25 1.82 3.44 1.82 3.44 1.845 3.585 1.845 3.585 3.03 ;
    END
  END C
  PIN D
    DIRECTION INPUT ;
    USE SIGNAL ;
    PORT
      LAYER METAL1 ;
        POLYGON 4.275 3.73 4.275 2.73 4.82 2.73 4.82 2.075 4.95 2.075 4.95 1.845 4.59 1.845 4.59 2.38 4.405 2.38 4.405 2.5 4.045 2.5 4.045 3.5 0.525 3.5 0.525 3.22 0.53 3.22 0.53 2.69 0.14 2.69 0.14 3.22 0.295 3.22 0.295 3.73 ;
    END
  END D
  PIN Y
    DIRECTION OUTPUT ;
    USE SIGNAL ;
    PORT
      LAYER METAL1 ;
        POLYGON 5.56 4.365 5.56 3.78 6.46 3.78 6.46 2.38 6.385 2.38 6.385 1.495 6.155 1.495 6.155 1.39 5.7 1.39 5.7 1.73 6.08 1.73 6.08 1.845 6.085 1.845 6.085 2.38 6.08 2.38 6.08 3.425 5.22 3.425 5.22 4.365 ;
    END
  END Y
  PIN VDD
    DIRECTION INPUT ;
    USE POWER ;
    PORT
      LAYER METAL1 ;
        POLYGON 7.26 5.44 7.26 4.64 6.355 4.64 6.355 4.465 5.965 4.465 5.965 4.64 4.445 4.64 4.445 4.465 4.105 4.465 4.105 4.64 2.84 4.64 2.84 4.465 2.5 4.465 2.5 4.64 1.3 4.64 1.3 4.465 0.91 4.465 0.91 4.64 0 4.64 0 5.44 ;
    END
  END VDD
  PIN VSS
    DIRECTION INPUT ;
    USE GROUND ;
    PORT
      LAYER METAL1 ;
        POLYGON 0.52 1.465 0.52 0.4 4.98 0.4 4.98 1.115 5.32 1.115 5.32 0.4 6.42 0.4 6.42 0.95 6.76 0.95 6.76 0.4 7.26 0.4 7.26 -0.4 0 -0.4 0 0.4 0.18 0.4 0.18 1.465 ;
    END
  END VSS
  OBS
    LAYER METAL1 ;
      POLYGON 3.625 4.365 3.625 4.195 4.74 4.195 4.74 3.195 5.47 3.195 5.47 2.47 5.715 2.47 5.715 2.13 5.47 2.13 5.47 1.38 4.455 1.38 4.455 1.065 2.92 1.065 2.92 1.01 2.58 1.01 2.58 1.35 2.92 1.35 2.92 1.295 4.225 1.295 4.225 1.61 5.24 1.61 5.24 2.965 4.51 2.965 4.51 3.965 1.74 3.965 1.74 4.365 2.08 4.365 2.08 4.195 3.285 4.195 3.285 4.365 ;
  END
END AND4X4

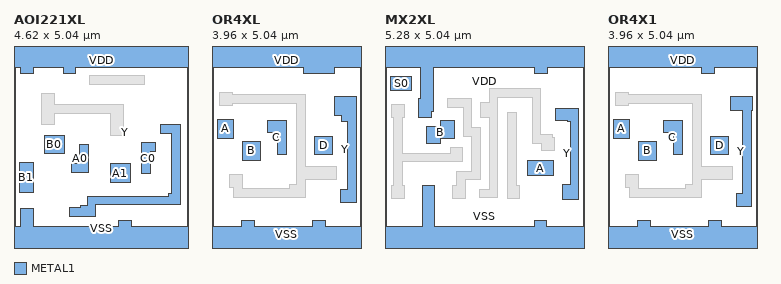
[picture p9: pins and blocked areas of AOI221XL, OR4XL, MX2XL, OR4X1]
MACRO AOI221XL
  CLASS CORE ;
  FOREIGN AOI221XL ;
  ORIGIN 0 0 ;
  SIZE 4.62 BY 5.04 ;
  SYMMETRY X Y ;
  SITE unit ;
  PIN A0
    DIRECTION INPUT ;
    USE SIGNAL ;
    PORT
      LAYER METAL1 ;
        POLYGON 1.965 2.575 1.965 1.845 1.535 1.845 1.535 2.075 1.735 2.075 1.735 2.575 ;
    END
  END A0
  PIN A1
    DIRECTION INPUT ;
    USE SIGNAL ;
    PORT
      LAYER METAL1 ;
        RECT 2.565 1.57 3.085 2.075 ;
    END
  END A1
  PIN B0
    DIRECTION INPUT ;
    USE SIGNAL ;
    PORT
      LAYER METAL1 ;
        RECT 0.8 2.36 1.34 2.82 ;
    END
  END B0
  PIN B1
    DIRECTION INPUT ;
    USE SIGNAL ;
    PORT
      LAYER METAL1 ;
        RECT 0.14 1.315 0.52 2.1 ;
    END
  END B1
  PIN C0
    DIRECTION INPUT ;
    USE SIGNAL ;
    PORT
      LAYER METAL1 ;
        POLYGON 3.745 2.635 3.745 2.405 3.62 2.405 3.62 1.82 3.39 1.82 3.39 2.635 ;
    END
  END C0
  PIN Y
    DIRECTION OUTPUT ;
    USE SIGNAL ;
    PORT
      LAYER METAL1 ;
        POLYGON 4.405 3.12 4.405 0.99 2.175 0.99 2.175 0.675 1.46 0.675 1.46 0.905 1.765 0.905 1.765 0.98 1.945 0.98 1.945 1.22 4.1 1.22 4.1 1.285 4.175 1.285 4.175 2.89 3.88 2.89 3.88 3.12 ;
    END
  END Y
  PIN VDD
    DIRECTION INPUT ;
    USE POWER ;
    PORT
      LAYER METAL1 ;
        POLYGON 4.62 5.44 4.62 4.64 1.64 4.64 1.64 4.465 1.3 4.465 1.3 4.64 0.52 4.64 0.52 4.465 0.18 4.465 0.18 4.64 0 4.64 0 5.44 ;
    END
  END VDD
  PIN VSS
    DIRECTION INPUT ;
    USE GROUND ;
    PORT
      LAYER METAL1 ;
        POLYGON 0.52 0.895 0.52 0.4 2.78 0.4 2.78 0.575 3.12 0.575 3.12 0.4 4.62 0.4 4.62 -0.4 0 -0.4 0 0.4 0.18 0.4 0.18 0.895 ;
    END
  END VSS
  OBS
    LAYER METAL1 ;
      RECT 2 4.18 3.46 4.41 ;
      POLYGON 1.08 3.93 1.08 3.64 2.9 3.64 2.9 2.82 2.56 2.82 2.56 3.41 1.08 3.41 1.08 3.11 0.74 3.11 0.74 3.93 ;
  END
END AOI221XL

MACRO OR4XL
  CLASS CORE ;
  FOREIGN OR4XL ;
  ORIGIN 0 0 ;
  SIZE 3.96 BY 5.04 ;
  SYMMETRY X Y ;
  SITE unit ;
  PIN A
    DIRECTION INPUT ;
    USE SIGNAL ;
    PORT
      LAYER METAL1 ;
        RECT 0.14 2.755 0.56 3.245 ;
    END
  END A
  PIN B
    DIRECTION INPUT ;
    USE SIGNAL ;
    PORT
      LAYER METAL1 ;
        RECT 0.8 2.17 1.28 2.665 ;
    END
  END B
  PIN C
    DIRECTION INPUT ;
    USE SIGNAL ;
    PORT
      LAYER METAL1 ;
        POLYGON 1.98 3.22 1.98 2.33 1.75 2.33 1.75 2.91 1.46 2.91 1.46 3.22 ;
    END
  END C
  PIN D
    DIRECTION INPUT ;
    USE SIGNAL ;
    PORT
      LAYER METAL1 ;
        RECT 2.715 2.33 3.19 2.795 ;
    END
  END D
  PIN Y
    DIRECTION OUTPUT ;
    USE SIGNAL ;
    PORT
      LAYER METAL1 ;
        POLYGON 3.82 3.87 3.82 1.06 3.42 1.06 3.42 1.4 3.59 1.4 3.59 3.195 3.44 3.195 3.44 3.365 3.24 3.365 3.24 3.87 ;
    END
  END Y
  PIN VDD
    DIRECTION INPUT ;
    USE POWER ;
    PORT
      LAYER METAL1 ;
        POLYGON 3.96 5.44 3.96 4.64 3.245 4.64 3.245 4.465 2.435 4.465 2.435 4.64 0 4.64 0 5.44 ;
    END
  END VDD
  PIN VSS
    DIRECTION INPUT ;
    USE GROUND ;
    PORT
      LAYER METAL1 ;
        POLYGON 3 0.575 3 0.4 3.96 0.4 3.96 -0.4 0 -0.4 0 0.4 0.78 0.4 0.78 0.575 1.12 0.575 1.12 0.4 2.66 0.4 2.66 0.575 ;
    END
  END VSS
  OBS
    LAYER METAL1 ;
      POLYGON 0.54 3.97 0.54 3.915 2.48 3.915 2.48 2.005 3.295 2.005 3.295 1.655 2.48 1.655 2.48 1.18 0.57 1.18 0.57 1.44 0.46 1.44 0.46 1.78 0.8 1.78 0.8 1.41 2.06 1.41 2.06 1.52 2.25 1.52 2.25 3.685 0.54 3.685 0.54 3.63 0.2 3.63 0.2 3.97 ;
  END
END OR4XL

MACRO MX2XL
  CLASS CORE ;
  FOREIGN MX2XL ;
  ORIGIN 0 0 ;
  SIZE 5.28 BY 5.04 ;
  SYMMETRY X Y ;
  SITE unit ;
  PIN A
    DIRECTION INPUT ;
    USE SIGNAL ;
    PORT
      LAYER METAL1 ;
        RECT 3.77 1.76 4.48 2.155 ;
    END
  END A
  PIN B
    DIRECTION INPUT ;
    USE SIGNAL ;
    PORT
      LAYER METAL1 ;
        POLYGON 1.84 3.22 1.84 2.745 1.46 2.745 1.46 2.6 1.1 2.6 1.1 3.065 1.46 3.065 1.46 3.22 ;
    END
  END B
  PIN S0
    DIRECTION INPUT ;
    USE SIGNAL ;
    PORT
      LAYER METAL1 ;
        RECT 0.14 4.025 0.71 4.4 ;
    END
  END S0
  PIN Y
    DIRECTION OUTPUT ;
    USE SIGNAL ;
    PORT
      LAYER METAL1 ;
        POLYGON 5.14 3.55 5.14 1.125 4.705 1.125 4.705 1.515 4.91 1.515 4.91 3.195 4.835 3.195 4.835 3.21 4.52 3.21 4.52 3.55 ;
    END
  END Y
  PIN VDD
    DIRECTION INPUT ;
    USE POWER ;
    PORT
      LAYER METAL1 ;
        POLYGON 5.28 5.44 5.28 4.64 4.3 4.64 4.3 4.465 3.96 4.465 3.96 4.64 1.285 4.64 1.285 3.455 1.23 3.455 1.23 3.295 0.9 3.295 0.9 3.795 0.945 3.795 0.945 4.64 0 4.64 0 5.44 ;
    END
  END VDD
  PIN VSS
    DIRECTION INPUT ;
    USE GROUND ;
    PORT
      LAYER METAL1 ;
        POLYGON 1.325 1.5 1.325 1.16 1.315 1.16 1.315 0.4 3.955 0.4 3.955 0.575 4.295 0.575 4.295 0.4 5.28 0.4 5.28 -0.4 0 -0.4 0 0.4 0.995 0.4 0.995 1.16 0.985 1.16 0.985 1.5 ;
    END
  END VSS
  OBS
    LAYER METAL1 ;
      POLYGON 4.135 4.065 4.135 2.84 4.445 2.84 4.445 2.77 4.5 2.77 4.5 2.43 4.16 2.43 4.16 2.61 3.905 2.61 3.905 3.835 2.99 3.835 2.99 1.175 2.505 1.175 2.505 1.405 2.76 1.405 2.76 3.315 2.53 3.315 2.53 3.705 2.76 3.705 2.76 4.065 ;
      POLYGON 2.3 3.805 2.3 3.025 2.53 3.025 2.53 1.65 2.125 1.65 2.125 1.155 1.785 1.155 1.785 1.495 1.895 1.495 1.895 1.88 2.3 1.88 2.3 2.795 2.07 2.795 2.07 3.575 1.66 3.575 1.66 3.805 ;
      POLYGON 0.52 3.65 0.52 3.31 0.465 3.31 0.465 2.36 1.735 2.36 1.735 2.515 2.06 2.515 2.06 2.13 0.465 2.13 0.465 1.5 0.52 1.5 0.52 1.16 0.18 1.16 0.18 1.5 0.235 1.5 0.235 3.31 0.18 3.31 0.18 3.65 ;
      POLYGON 3.48 3.44 3.48 1.505 3.56 1.505 3.56 1.16 3.25 1.16 3.25 3.44 ;
  END
END MX2XL

MACRO OR4X1
  CLASS CORE ;
  FOREIGN OR4X1 ;
  ORIGIN 0 0 ;
  SIZE 3.96 BY 5.04 ;
  SYMMETRY X Y ;
  SITE unit ;
  PIN A
    DIRECTION INPUT ;
    USE SIGNAL ;
    PORT
      LAYER METAL1 ;
        RECT 0.14 2.755 0.56 3.245 ;
    END
  END A
  PIN B
    DIRECTION INPUT ;
    USE SIGNAL ;
    PORT
      LAYER METAL1 ;
        RECT 0.8 2.17 1.28 2.665 ;
    END
  END B
  PIN C
    DIRECTION INPUT ;
    USE SIGNAL ;
    PORT
      LAYER METAL1 ;
        POLYGON 1.98 3.22 1.98 2.33 1.75 2.33 1.75 2.91 1.46 2.91 1.46 3.22 ;
    END
  END C
  PIN D
    DIRECTION INPUT ;
    USE SIGNAL ;
    PORT
      LAYER METAL1 ;
        RECT 2.715 2.33 3.19 2.795 ;
    END
  END D
  PIN Y
    DIRECTION OUTPUT ;
    USE SIGNAL ;
    PORT
      LAYER METAL1 ;
        POLYGON 3.82 3.87 3.82 3.5 3.8 3.5 3.8 0.95 3.42 0.95 3.42 1.29 3.57 1.29 3.57 3.5 3.24 3.5 3.24 3.87 ;
    END
  END Y
  PIN VDD
    DIRECTION INPUT ;
    USE POWER ;
    PORT
      LAYER METAL1 ;
        POLYGON 3.96 5.44 3.96 4.64 2.82 4.64 2.82 4.465 2.48 4.465 2.48 4.64 0 4.64 0 5.44 ;
    END
  END VDD
  PIN VSS
    DIRECTION INPUT ;
    USE GROUND ;
    PORT
      LAYER METAL1 ;
        POLYGON 3 0.575 3 0.4 3.96 0.4 3.96 -0.4 0 -0.4 0 0.4 0.78 0.4 0.78 0.575 1.12 0.575 1.12 0.4 2.66 0.4 2.66 0.575 ;
    END
  END VSS
  OBS
    LAYER METAL1 ;
      POLYGON 0.54 3.97 0.54 3.915 2.48 3.915 2.48 2.005 3.295 2.005 3.295 1.655 2.48 1.655 2.48 1.18 0.57 1.18 0.57 1.44 0.46 1.44 0.46 1.78 0.8 1.78 0.8 1.41 2.06 1.41 2.06 1.52 2.25 1.52 2.25 3.685 0.54 3.685 0.54 3.63 0.2 3.63 0.2 3.97 ;
  END
END OR4X1

END LIBRARY
